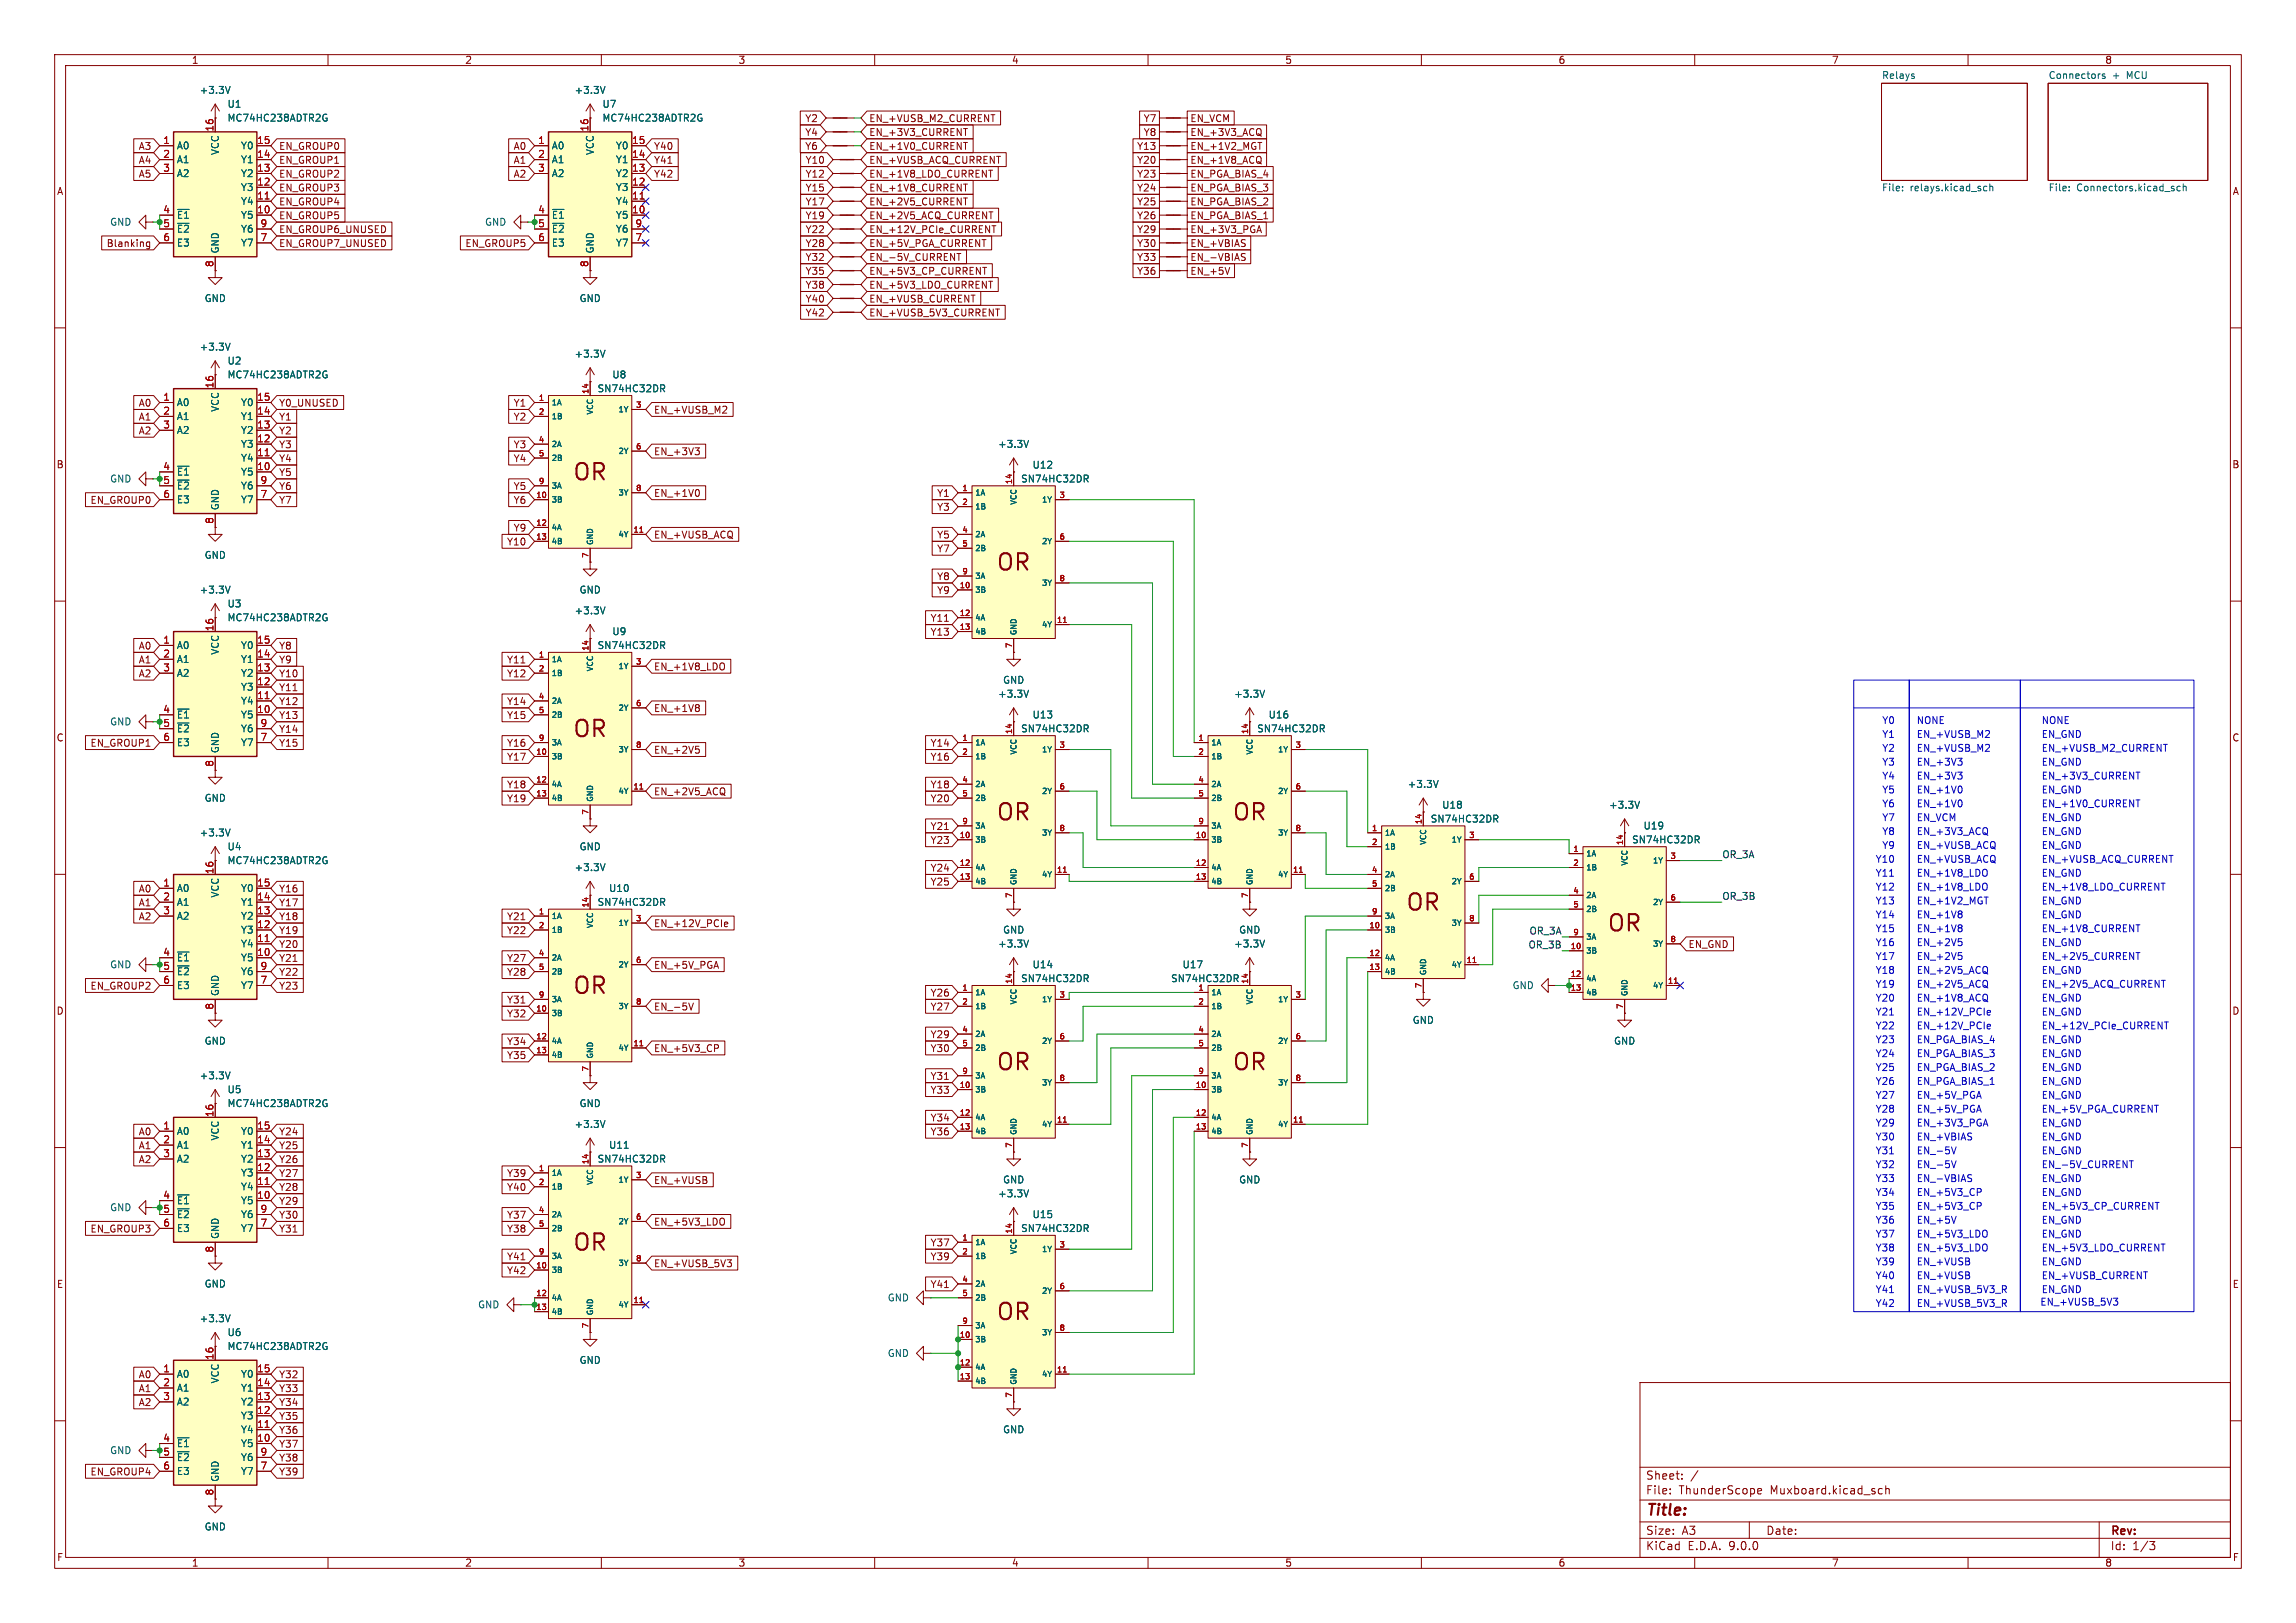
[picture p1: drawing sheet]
<svg xmlns="http://www.w3.org/2000/svg" width="420mm" height="297mm" viewBox="0 0 420 297" stroke-linecap="round" stroke-linejoin="round" font-family="sans-serif">
<defs><g id="words">
<g font-size="4.2" fill="#840000">
<text x="103.3" y="88.4">OR</text>
<text x="180.8" y="104.9">OR</text>
<text x="103.3" y="135.4">OR</text>
<text x="180.8" y="150.7">OR</text>
<text x="224" y="150.7">OR</text>
<text x="255.7" y="167.2">OR</text>
<text x="292.6" y="171">OR</text>
<text x="103.3" y="182.4">OR</text>
<text x="180.8" y="196.4">OR</text>
<text x="224" y="196.4">OR</text>
<text x="103.3" y="229.4">OR</text>
<text x="180.8" y="242.1">OR</text>
</g>
<text font-size="2.8" fill="#840000" x="301" y="277.9">Title:</text>
<g font-size="2.1" fill="#840000">
<text x="301" y="273.7">File:</text>
<text x="301" y="271">Sheet:</text>
<text x="307.1" y="273.7">ThunderScope</text>
<text x="323.9" y="273.7">Muxboard.kicad_sch</text>
<text x="301" y="281.1">Size:</text>
<text x="307.6" y="281.1">A3</text>
<text x="323" y="281.1">Date:</text>
<text x="386" y="281.3">Rev:</text>
<text x="301" y="283.9">KiCad</text>
<text x="308.7" y="283.9">E.D.A.</text>
<text x="316.3" y="283.9">9.0.0</text>
<text x="386" y="283.9">Id:</text>
<text x="390.1" y="283.9">1/3</text>
</g>
<g font-size="1.8" fill="#840000">
<text x="35" y="11.9">1</text>
<text x="85" y="11.9">2</text>
<text x="135" y="11.9">3</text>
<text x="185" y="11.9">4</text>
<text x="235" y="11.9">5</text>
<text x="285" y="11.9">6</text>
<text x="335" y="11.9">7</text>
<text x="385" y="11.9">8</text>
<text x="147.2" y="22.5">Y2</text>
<text x="158.9" y="22.5">EN_+VUSB_M2_CURRENT</text>
<text x="209.1" y="22.5">Y7</text>
<text x="217.6" y="22.5">EN_VCM</text>
<text x="25.3" y="27.6">A3</text>
<text x="51" y="27.6">EN_GROUP0</text>
<text x="93.9" y="27.6">A0</text>
<text x="119.5" y="27.6">Y40</text>
<text x="147.2" y="27.6">Y6</text>
<text x="147.2" y="25.1">Y4</text>
<text x="158.9" y="27.6">EN_+1V0_CURRENT</text>
<text x="158.9" y="25.1">EN_+3V3_CURRENT</text>
<text x="207.9" y="27.6">Y13</text>
<text x="209.1" y="25.1">Y8</text>
<text x="217.6" y="27.6">EN_+1V2_MGT</text>
<text x="217.6" y="25.1">EN_+3V3_ACQ</text>
<text x="10.3" y="35.9">A</text>
<text x="25.3" y="30.2">A4</text>
<text x="25.3" y="32.7">A5</text>
<text x="51" y="32.7">EN_GROUP2</text>
<text x="51" y="35.2">EN_GROUP3</text>
<text x="51" y="30.2">EN_GROUP1</text>
<text x="93.9" y="30.2">A1</text>
<text x="93.9" y="32.7">A2</text>
<text x="119.5" y="30.2">Y41</text>
<text x="119.5" y="32.7">Y42</text>
<text x="147.3" y="32.7">Y12</text>
<text x="147.3" y="30.2">Y10</text>
<text x="147.3" y="35.2">Y15</text>
<text x="158.9" y="32.7">EN_+1V8_LDO_CURRENT</text>
<text x="158.9" y="35.2">EN_+1V8_CURRENT</text>
<text x="158.9" y="30.2">EN_+VUSB_ACQ_CURRENT</text>
<text x="207.9" y="30.2">Y20</text>
<text x="207.9" y="32.7">Y23</text>
<text x="207.9" y="35.2">Y24</text>
<text x="217.6" y="30.2">EN_+1V8_ACQ</text>
<text x="217.6" y="35.2">EN_PGA_BIAS_3</text>
<text x="217.6" y="32.7">EN_PGA_BIAS_4</text>
<text x="408.3" y="35.9">A</text>
<text x="51" y="40.3">EN_GROUP5</text>
<text x="51" y="37.8">EN_GROUP4</text>
<text x="147.3" y="40.3">Y19</text>
<text x="147.3" y="37.8">Y17</text>
<text x="158.9" y="37.8">EN_+2V5_CURRENT</text>
<text x="158.9" y="40.3">EN_+2V5_ACQ_CURRENT</text>
<text x="207.9" y="37.8">Y25</text>
<text x="207.9" y="40.3">Y26</text>
<text x="217.6" y="37.8">EN_PGA_BIAS_2</text>
<text x="217.6" y="40.3">EN_PGA_BIAS_1</text>
<text x="19.4" y="45.4">Blanking</text>
<text x="51" y="42.9">EN_GROUP6_UNUSED</text>
<text x="51" y="45.4">EN_GROUP7_UNUSED</text>
<text x="85" y="45.4">EN_GROUP5</text>
<text x="147.3" y="42.9">Y22</text>
<text x="147.3" y="47.9">Y32</text>
<text x="147.3" y="45.4">Y28</text>
<text x="158.9" y="42.9">EN_+12V_PCIe_CURRENT</text>
<text x="158.9" y="47.9">EN_-5V_CURRENT</text>
<text x="158.9" y="45.4">EN_+5V_PGA_CURRENT</text>
<text x="207.9" y="45.4">Y30</text>
<text x="207.9" y="47.9">Y33</text>
<text x="207.9" y="42.9">Y29</text>
<text x="217.6" y="45.4">EN_+VBIAS</text>
<text x="217.6" y="42.9">EN_+3V3_PGA</text>
<text x="217.6" y="47.9">EN_-VBIAS</text>
<text x="147.3" y="50.5">Y35</text>
<text x="147.3" y="53">Y38</text>
<text x="158.9" y="50.5">EN_+5V3_CP_CURRENT</text>
<text x="158.9" y="53">EN_+5V3_LDO_CURRENT</text>
<text x="207.9" y="50.5">Y36</text>
<text x="217.6" y="50.5">EN_+5V</text>
<text x="147.3" y="55.6">Y40</text>
<text x="147.3" y="58.1">Y42</text>
<text x="158.9" y="55.6">EN_+VUSB_CURRENT</text>
<text x="158.9" y="58.1">EN_+VUSB_5V3_CURRENT</text>
<text x="25.3" y="74.6">A0</text>
<text x="25.3" y="77.2">A1</text>
<text x="51" y="77.2">Y1</text>
<text x="51" y="74.6">Y0_UNUSED</text>
<text x="93.9" y="77.2">Y2</text>
<text x="93.9" y="74.6">Y1</text>
<text x="119.5" y="75.9">EN_+VUSB_M2</text>
<text x="25.3" y="79.7">A2</text>
<text x="51" y="82.2">Y3</text>
<text x="51" y="79.7">Y2</text>
<text x="93.9" y="82.2">Y3</text>
<text x="119.5" y="83.5">EN_+3V3</text>
<text x="10.3" y="85.9">B</text>
<text x="51" y="89.9">Y6</text>
<text x="51" y="87.3">Y5</text>
<text x="51" y="84.8">Y4</text>
<text x="93.9" y="84.8">Y4</text>
<text x="93.9" y="89.9">Y5</text>
<text x="408.2" y="85.9">B</text>
<text x="16.5" y="92.4">EN_GROUP0</text>
<text x="51" y="92.4">Y7</text>
<text x="93.9" y="92.4">Y6</text>
<text x="119.5" y="91.1">EN_+1V0</text>
<text x="171.3" y="93.7">Y3</text>
<text x="171.3" y="91.1">Y1</text>
<text x="92.7" y="100">Y10</text>
<text x="93.9" y="97.5">Y9</text>
<text x="119.5" y="98.7">EN_+VUSB_ACQ</text>
<text x="171.3" y="101.3">Y7</text>
<text x="171.3" y="98.7">Y5</text>
<text x="171.3" y="106.4">Y8</text>
<text x="170.1" y="114">Y11</text>
<text x="171.3" y="108.9">Y9</text>
<text x="25.3" y="119.1">A0</text>
<text x="51" y="119.1">Y8</text>
<text x="170.1" y="116.5">Y13</text>
<text x="25.3" y="124.1">A2</text>
<text x="25.3" y="121.6">A1</text>
<text x="51" y="121.6">Y9</text>
<text x="51" y="124.1">Y10</text>
<text x="92.7" y="121.6">Y11</text>
<text x="92.7" y="124.1">Y12</text>
<text x="119.5" y="122.9">EN_+1V8_LDO</text>
<text x="51" y="126.7">Y11</text>
<text x="51" y="131.8">Y13</text>
<text x="51" y="129.2">Y12</text>
<text x="92.7" y="131.8">Y15</text>
<text x="92.7" y="129.2">Y14</text>
<text x="119.5" y="130.5">EN_+1V8</text>
<text x="10.3" y="135.9">C</text>
<text x="16.5" y="136.8">EN_GROUP1</text>
<text x="51" y="136.8">Y15</text>
<text x="51" y="134.3">Y14</text>
<text x="92.7" y="136.8">Y16</text>
<text x="170.1" y="136.8">Y14</text>
<text x="408.2" y="135.9">C</text>
<text x="92.7" y="139.4">Y17</text>
<text x="119.5" y="138.1">EN_+2V5</text>
<text x="170.1" y="139.4">Y16</text>
<text x="92.7" y="147">Y19</text>
<text x="92.7" y="144.5">Y18</text>
<text x="119.5" y="145.7">EN_+2V5_ACQ</text>
<text x="170.1" y="147">Y20</text>
<text x="170.1" y="144.5">Y18</text>
<text x="170.1" y="152.1">Y21</text>
<text x="170.1" y="154.6">Y23</text>
<text x="170.1" y="159.7">Y24</text>
<text x="25.3" y="166.1">A1</text>
<text x="25.3" y="163.5">A0</text>
<text x="51" y="166.1">Y17</text>
<text x="51" y="163.5">Y16</text>
<text x="170.1" y="162.2">Y25</text>
<text x="25.3" y="168.6">A2</text>
<text x="51" y="168.6">Y18</text>
<text x="51" y="171.1">Y19</text>
<text x="51" y="173.7">Y20</text>
<text x="92.7" y="168.6">Y21</text>
<text x="92.7" y="171.1">Y22</text>
<text x="119.5" y="169.9">EN_+12V_PCIe</text>
<text x="308.8" y="173.7">EN_GND</text>
<text x="51" y="176.2">Y21</text>
<text x="51" y="178.8">Y22</text>
<text x="92.7" y="176.2">Y27</text>
<text x="92.7" y="178.8">Y28</text>
<text x="119.5" y="177.5">EN_+5V_PGA</text>
<text x="10.3" y="185.9">D</text>
<text x="16.5" y="181.3">EN_GROUP2</text>
<text x="51" y="181.3">Y23</text>
<text x="92.7" y="183.8">Y31</text>
<text x="119.5" y="185.1">EN_-5V</text>
<text x="170.1" y="185.1">Y27</text>
<text x="170.1" y="182.6">Y26</text>
<text x="408.2" y="185.9">D</text>
<text x="92.7" y="191.5">Y34</text>
<text x="92.7" y="186.4">Y32</text>
<text x="170.1" y="190.2">Y29</text>
<text x="92.7" y="194">Y35</text>
<text x="119.5" y="192.7">EN_+5V3_CP</text>
<text x="170.1" y="192.7">Y30</text>
<text x="170.1" y="197.8">Y31</text>
<text x="170.1" y="200.3">Y33</text>
<text x="25.3" y="208">A0</text>
<text x="51" y="208">Y24</text>
<text x="170.1" y="205.4">Y34</text>
<text x="170.1" y="208">Y36</text>
<text x="25.3" y="210.5">A1</text>
<text x="25.3" y="213">A2</text>
<text x="51" y="215.6">Y27</text>
<text x="51" y="210.5">Y25</text>
<text x="51" y="213">Y26</text>
<text x="92.7" y="215.6">Y39</text>
<text x="51" y="220.7">Y29</text>
<text x="51" y="218.1">Y28</text>
<text x="92.7" y="218.1">Y40</text>
<text x="119.5" y="216.9">EN_+VUSB</text>
<text x="16.5" y="225.7">EN_GROUP3</text>
<text x="51" y="223.2">Y30</text>
<text x="51" y="225.7">Y31</text>
<text x="92.7" y="223.2">Y37</text>
<text x="92.7" y="225.7">Y38</text>
<text x="119.5" y="224.5">EN_+5V3_LDO</text>
<text x="92.7" y="233.4">Y42</text>
<text x="92.7" y="230.8">Y41</text>
<text x="119.5" y="232.1">EN_+VUSB_5V3</text>
<text x="170.1" y="228.3">Y37</text>
<text x="170.1" y="230.8">Y39</text>
<text x="10.3" y="235.9">E</text>
<text x="170.1" y="235.9">Y41</text>
<text x="408.3" y="235.9">E</text>
<text x="25.3" y="257.5">A2</text>
<text x="25.3" y="255">A1</text>
<text x="25.3" y="252.4">A0</text>
<text x="51" y="257.5">Y34</text>
<text x="51" y="255">Y33</text>
<text x="51" y="252.4">Y32</text>
<text x="51" y="260">Y35</text>
<text x="51" y="262.6">Y36</text>
<text x="51" y="265.1">Y37</text>
<text x="51" y="267.7">Y38</text>
<text x="16.5" y="270.2">EN_GROUP4</text>
<text x="51" y="270.2">Y39</text>
<text x="10.3" y="285.9">F</text>
<text x="35" y="286.9">1</text>
<text x="85" y="286.9">2</text>
<text x="135" y="286.9">3</text>
<text x="185" y="286.9">4</text>
<text x="235" y="286.9">5</text>
<text x="285" y="286.9">6</text>
<text x="335" y="286.9">7</text>
<text x="385" y="286.9">8</text>
<text x="408.3" y="285.9">F</text>
</g>
<g font-size="1.8" fill="#006464">
<text x="36.4" y="17.4">+3.3V</text>
<text x="105" y="17.4">+3.3V</text>
<text x="344.2" y="14.5">Relays</text>
<text x="374.6" y="14.5">Connectors</text>
<text x="386.4" y="14.5">+</text>
<text x="389.1" y="14.5">MCU</text>
<text x="41.5" y="22.5">MC74HC238ADTR2G</text>
<text x="41.5" y="19.9">U1</text>
<text x="110.1" y="22.5">MC74HC238ADTR2G</text>
<text x="110.1" y="19.9">U7</text>
<text x="32.3" y="27.5">A0</text>
<text x="40.2" y="28.5" transform="rotate(-90 40.2 28.5)">VCC</text>
<text x="44" y="27.5">Y0</text>
<text x="100.8" y="27.5">A0</text>
<text x="108.8" y="28.5" transform="rotate(-90 108.8 28.5)">VCC</text>
<text x="112.6" y="27.5">Y0</text>
<text x="32.3" y="30.1">A1</text>
<text x="32.3" y="32.6">A2</text>
<text x="44" y="30.1">Y1</text>
<text x="44" y="32.6">Y2</text>
<text x="44" y="35.2">Y3</text>
<text x="100.8" y="30.1">A1</text>
<text x="100.8" y="32.6">A2</text>
<text x="112.6" y="30.1">Y1</text>
<text x="112.6" y="32.6">Y2</text>
<text x="112.6" y="35.2">Y3</text>
<text x="344.2" y="35.3">File:</text>
<text x="349.4" y="35.3">relays.kicad_sch</text>
<text x="374.6" y="35.3">File:</text>
<text x="379.9" y="35.3">Connectors.kicad_sch</text>
<text x="20" y="41.5">GND</text>
<text x="32.3" y="40.2">~{E1}</text>
<text x="44" y="37.7">Y4</text>
<text x="44" y="40.2">Y5</text>
<text x="88.6" y="41.5">GND</text>
<text x="100.8" y="40.2">~{E1}</text>
<text x="112.6" y="37.7">Y4</text>
<text x="112.6" y="40.2">Y5</text>
<text x="32.3" y="42.8">~{E2}</text>
<text x="32.3" y="45.3">E3</text>
<text x="40.2" y="46.5" transform="rotate(-90 40.2 46.5)">GND</text>
<text x="44" y="42.8">Y6</text>
<text x="44" y="45.3">Y7</text>
<text x="100.8" y="42.8">~{E2}</text>
<text x="100.8" y="45.3">E3</text>
<text x="108.8" y="46.5" transform="rotate(-90 108.8 46.5)">GND</text>
<text x="112.6" y="42.8">Y6</text>
<text x="112.6" y="45.3">Y7</text>
<text x="37.3" y="55.5">GND</text>
<text x="105.9" y="55.5">GND</text>
<text x="36.4" y="64.4">+3.3V</text>
<text x="105" y="65.6">+3.3V</text>
<text x="41.5" y="69.4">MC74HC238ADTR2G</text>
<text x="41.5" y="66.9">U2</text>
<text x="109.2" y="72">SN74HC32DR</text>
<text x="111.9" y="69.4">U8</text>
<text x="32.3" y="74.5">A0</text>
<text x="32.3" y="77.1">A1</text>
<text x="40.2" y="75.5" transform="rotate(-90 40.2 75.5)">VCC</text>
<text x="44" y="74.5">Y0</text>
<text x="44" y="77.1">Y1</text>
<text x="32.3" y="79.6">A2</text>
<text x="44" y="79.6">Y2</text>
<text x="44" y="82.1">Y3</text>
<text x="182.5" y="82.1">+3.3V</text>
<text x="20" y="88.5">GND</text>
<text x="32.3" y="87.2">~{E1}</text>
<text x="32.3" y="89.8">~{E2}</text>
<text x="44" y="84.7">Y4</text>
<text x="44" y="87.2">Y5</text>
<text x="44" y="89.8">Y6</text>
<text x="186.7" y="88.5">SN74HC32DR</text>
<text x="188.8" y="86">U12</text>
<text x="32.3" y="92.3">E3</text>
<text x="40.2" y="93.5" transform="rotate(-90 40.2 93.5)">GND</text>
<text x="44" y="92.3">Y7</text>
<text x="37.3" y="102.5">GND</text>
<text x="36.4" y="108.8">+3.3V</text>
<text x="41.5" y="113.9">MC74HC238ADTR2G</text>
<text x="41.5" y="111.4">U3</text>
<text x="105" y="112.6">+3.3V</text>
<text x="105.9" y="108.8">GND</text>
<text x="32.3" y="119">A0</text>
<text x="40.2" y="119.9" transform="rotate(-90 40.2 119.9)">VCC</text>
<text x="44" y="119">Y0</text>
<text x="109.2" y="119">SN74HC32DR</text>
<text x="111.9" y="116.4">U9</text>
<text x="32.3" y="121.5">A1</text>
<text x="32.3" y="124.1">A2</text>
<text x="44" y="121.5">Y1</text>
<text x="44" y="124.1">Y2</text>
<text x="183.4" y="125.3">GND</text>
<text x="32.3" y="131.7">~{E1}</text>
<text x="44" y="126.6">Y3</text>
<text x="44" y="129.1">Y4</text>
<text x="44" y="131.7">Y5</text>
<text x="182.5" y="127.9">+3.3V</text>
<text x="188.8" y="131.7">U13</text>
<text x="225.7" y="127.9">+3.3V</text>
<text x="232" y="131.7">U16</text>
<text x="20" y="132.9">GND</text>
<text x="32.3" y="134.2">~{E2}</text>
<text x="32.3" y="136.8">E3</text>
<text x="40.2" y="137.9" transform="rotate(-90 40.2 137.9)">GND</text>
<text x="44" y="134.2">Y6</text>
<text x="44" y="136.8">Y7</text>
<text x="186.7" y="134.2">SN74HC32DR</text>
<text x="229.9" y="134.2">SN74HC32DR</text>
<text x="37.3" y="146.9">GND</text>
<text x="257.4" y="144.4">+3.3V</text>
<text x="263.7" y="148.2">U18</text>
<text x="294.2" y="148.2">+3.3V</text>
<text x="36.4" y="153.3">+3.3V</text>
<text x="41.5" y="155.8">U4</text>
<text x="105.9" y="155.8">GND</text>
<text x="261.6" y="150.7">SN74HC32DR</text>
<text x="298.4" y="154.5">SN74HC32DR</text>
<text x="300.5" y="152">U19</text>
<text x="41.5" y="158.3">MC74HC238ADTR2G</text>
<text x="105" y="159.6">+3.3V</text>
<text x="32.3" y="163.4">A0</text>
<text x="32.3" y="166">A1</text>
<text x="40.2" y="164.4" transform="rotate(-90 40.2 164.4)">VCC</text>
<text x="44" y="163.4">Y0</text>
<text x="44" y="166">Y1</text>
<text x="109.2" y="166">SN74HC32DR</text>
<text x="111.3" y="163.4">U10</text>
<text x="32.3" y="168.5">A2</text>
<text x="44" y="168.5">Y2</text>
<text x="44" y="171">Y3</text>
<text x="44" y="173.6">Y4</text>
<text x="182.5" y="173.6">+3.3V</text>
<text x="183.4" y="171">GND</text>
<text x="225.7" y="173.6">+3.3V</text>
<text x="226.6" y="171">GND</text>
<text x="20" y="177.4">GND</text>
<text x="32.3" y="176.1">~{E1}</text>
<text x="32.3" y="178.7">~{E2}</text>
<text x="44" y="176.1">Y5</text>
<text x="44" y="178.7">Y6</text>
<text x="186.7" y="179.9">SN74HC32DR</text>
<text x="188.8" y="177.4">U14</text>
<text x="214.1" y="179.9">SN74HC32DR</text>
<text x="216.2" y="177.4">U17</text>
<text x="32.3" y="181.2">E3</text>
<text x="40.2" y="182.4" transform="rotate(-90 40.2 182.4)">GND</text>
<text x="44" y="181.2">Y7</text>
<text x="276.6" y="181.2">GND</text>
<text x="37.3" y="191.4">GND</text>
<text x="258.3" y="187.6">GND</text>
<text x="295.1" y="191.4">GND</text>
<text x="36.4" y="197.7">+3.3V</text>
<text x="41.5" y="202.8">MC74HC238ADTR2G</text>
<text x="41.5" y="200.3">U5</text>
<text x="105.9" y="202.8">GND</text>
<text x="32.3" y="207.9">A0</text>
<text x="40.2" y="208.8" transform="rotate(-90 40.2 208.8)">VCC</text>
<text x="44" y="207.9">Y0</text>
<text x="105" y="206.6">+3.3V</text>
<text x="32.3" y="210.4">A1</text>
<text x="32.3" y="213">A2</text>
<text x="44" y="210.4">Y1</text>
<text x="44" y="213">Y2</text>
<text x="44" y="215.5">Y3</text>
<text x="109.2" y="213">SN74HC32DR</text>
<text x="111.3" y="210.4">U11</text>
<text x="20" y="221.8">GND</text>
<text x="32.3" y="220.6">~{E1}</text>
<text x="44" y="218">Y4</text>
<text x="44" y="220.6">Y5</text>
<text x="182.5" y="219.3">+3.3V</text>
<text x="183.4" y="216.8">GND</text>
<text x="226.6" y="216.8">GND</text>
<text x="32.3" y="223.1">~{E2}</text>
<text x="32.3" y="225.7">E3</text>
<text x="40.2" y="226.8" transform="rotate(-90 40.2 226.8)">GND</text>
<text x="44" y="223.1">Y6</text>
<text x="44" y="225.7">Y7</text>
<text x="186.7" y="225.7">SN74HC32DR</text>
<text x="188.8" y="223.1">U15</text>
<text x="37.3" y="235.8">GND</text>
<text x="87.4" y="239.6">GND</text>
<text x="162.3" y="238.4">GND</text>
<text x="36.4" y="242.2">+3.3V</text>
<text x="41.5" y="244.7">U6</text>
<text x="41.5" y="247.2">MC74HC238ADTR2G</text>
<text x="105.9" y="249.8">GND</text>
<text x="162.3" y="248.5">GND</text>
<text x="32.3" y="252.3">A0</text>
<text x="32.3" y="254.9">A1</text>
<text x="32.3" y="257.4">A2</text>
<text x="40.2" y="253.3" transform="rotate(-90 40.2 253.3)">VCC</text>
<text x="44" y="252.3">Y0</text>
<text x="44" y="254.9">Y1</text>
<text x="44" y="257.4">Y2</text>
<text x="44" y="259.9">Y3</text>
<text x="44" y="262.5">Y4</text>
<text x="183.4" y="262.5">GND</text>
<text x="20" y="266.3">GND</text>
<text x="32.3" y="265">~{E1}</text>
<text x="32.3" y="267.6">~{E2}</text>
<text x="44" y="265">Y5</text>
<text x="44" y="267.6">Y6</text>
<text x="32.3" y="270.1">E3</text>
<text x="40.2" y="271.3" transform="rotate(-90 40.2 271.3)">GND</text>
<text x="44" y="270.1">Y7</text>
<text x="37.3" y="280.3">GND</text>
</g>
<g font-size="1.8" fill="#a90000">
<text x="29.8" y="26.4">1</text>
<text x="29.8" y="29">2</text>
<text x="39.1" y="24.2" transform="rotate(-90 39.1 24.2)">16</text>
<text x="46.9" y="26.4">15</text>
<text x="46.9" y="29">14</text>
<text x="98.4" y="26.4">1</text>
<text x="98.4" y="29">2</text>
<text x="107.7" y="24.2" transform="rotate(-90 107.7 24.2)">16</text>
<text x="115.5" y="26.4">15</text>
<text x="115.5" y="29">14</text>
<text x="29.8" y="31.5">3</text>
<text x="46.9" y="31.5">13</text>
<text x="46.9" y="34">12</text>
<text x="98.4" y="31.5">3</text>
<text x="115.5" y="31.5">13</text>
<text x="115.5" y="34">12</text>
<text x="29.8" y="39.1">4</text>
<text x="29.8" y="41.7">5</text>
<text x="46.9" y="36.6">11</text>
<text x="46.9" y="39.1">10</text>
<text x="47.6" y="41.7">9</text>
<text x="98.4" y="39.1">4</text>
<text x="98.4" y="41.7">5</text>
<text x="115.5" y="36.6">11</text>
<text x="115.5" y="39.1">10</text>
<text x="116.1" y="41.7">9</text>
<text x="29.8" y="44.2">6</text>
<text x="47.6" y="44.2">7</text>
<text x="98.4" y="44.2">6</text>
<text x="116.1" y="44.2">7</text>
<text x="39.1" y="49" transform="rotate(-90 39.1 49)">8</text>
<text x="107.7" y="49" transform="rotate(-90 107.7 49)">8</text>
<text x="39.1" y="71.2" transform="rotate(-90 39.1 71.2)">16</text>
<text x="29.8" y="73.4">1</text>
<text x="29.8" y="75.9">2</text>
<text x="46.9" y="73.4">15</text>
<text x="46.9" y="75.9">14</text>
<text x="29.8" y="78.5">3</text>
<text x="46.9" y="78.5">13</text>
<text x="46.9" y="81">12</text>
<text x="46.9" y="83.6">11</text>
<text x="29.8" y="86.1">4</text>
<text x="29.8" y="88.6">5</text>
<text x="46.9" y="86.1">10</text>
<text x="47.6" y="88.6">9</text>
<text x="29.8" y="91.2">6</text>
<text x="39.1" y="96" transform="rotate(-90 39.1 96)">8</text>
<text x="47.6" y="91.2">7</text>
<text x="29.8" y="117.9">1</text>
<text x="39.1" y="115.6" transform="rotate(-90 39.1 115.6)">16</text>
<text x="46.9" y="117.9">15</text>
<text x="29.8" y="120.4">2</text>
<text x="29.8" y="122.9">3</text>
<text x="46.9" y="120.4">14</text>
<text x="46.9" y="122.9">13</text>
<text x="46.9" y="125.5">12</text>
<text x="29.8" y="130.6">4</text>
<text x="46.9" y="128">11</text>
<text x="46.9" y="130.6">10</text>
<text x="29.8" y="133.1">5</text>
<text x="29.8" y="135.6">6</text>
<text x="47.6" y="133.1">9</text>
<text x="47.6" y="135.6">7</text>
<text x="39.1" y="140.4" transform="rotate(-90 39.1 140.4)">8</text>
<text x="39.1" y="160.1" transform="rotate(-90 39.1 160.1)">16</text>
<text x="29.8" y="162.3">1</text>
<text x="29.8" y="164.8">2</text>
<text x="29.8" y="167.4">3</text>
<text x="46.9" y="162.3">15</text>
<text x="46.9" y="164.8">14</text>
<text x="46.9" y="167.4">13</text>
<text x="46.9" y="169.9">12</text>
<text x="46.9" y="172.5">11</text>
<text x="29.8" y="175">4</text>
<text x="29.8" y="177.5">5</text>
<text x="46.9" y="175">10</text>
<text x="47.6" y="177.5">9</text>
<text x="29.8" y="180.1">6</text>
<text x="39.1" y="184.9" transform="rotate(-90 39.1 184.9)">8</text>
<text x="47.6" y="180.1">7</text>
<text x="29.8" y="206.8">1</text>
<text x="29.8" y="209.3">2</text>
<text x="39.1" y="204.5" transform="rotate(-90 39.1 204.5)">16</text>
<text x="46.9" y="206.8">15</text>
<text x="46.9" y="209.3">14</text>
<text x="29.8" y="211.8">3</text>
<text x="46.9" y="211.8">13</text>
<text x="46.9" y="214.4">12</text>
<text x="29.8" y="219.5">4</text>
<text x="29.8" y="222">5</text>
<text x="46.9" y="216.9">11</text>
<text x="46.9" y="219.5">10</text>
<text x="47.6" y="222">9</text>
<text x="29.8" y="224.5">6</text>
<text x="47.6" y="224.5">7</text>
<text x="39.1" y="229.3" transform="rotate(-90 39.1 229.3)">8</text>
<text x="29.8" y="251.2">1</text>
<text x="39.1" y="249" transform="rotate(-90 39.1 249)">16</text>
<text x="46.9" y="251.2">15</text>
<text x="29.8" y="253.7">2</text>
<text x="29.8" y="256.3">3</text>
<text x="46.9" y="253.7">14</text>
<text x="46.9" y="256.3">13</text>
<text x="29.8" y="263.9">4</text>
<text x="46.9" y="258.8">12</text>
<text x="46.9" y="261.4">11</text>
<text x="46.9" y="263.9">10</text>
<text x="29.8" y="266.4">5</text>
<text x="29.8" y="269">6</text>
<text x="47.6" y="266.4">9</text>
<text x="47.6" y="269">7</text>
<text x="39.1" y="273.8" transform="rotate(-90 39.1 273.8)">8</text>
</g>
<g font-size="1.8" fill="#0000c2">
<text x="344.2" y="135.2">Y1</text>
<text x="344.2" y="137.8">Y2</text>
<text x="344.2" y="132.7">Y0</text>
<text x="350.5" y="132.7">NONE</text>
<text x="350.5" y="135.2">EN_+VUSB_M2</text>
<text x="350.5" y="137.8">EN_+VUSB_M2</text>
<text x="373.4" y="137.8">EN_+VUSB_M2_CURRENT</text>
<text x="373.4" y="132.7">NONE</text>
<text x="373.4" y="135.2">EN_GND</text>
<text x="344.2" y="142.9">Y4</text>
<text x="344.2" y="140.3">Y3</text>
<text x="350.5" y="142.9">EN_+3V3</text>
<text x="350.5" y="140.3">EN_+3V3</text>
<text x="373.4" y="140.3">EN_GND</text>
<text x="373.4" y="142.9">EN_+3V3_CURRENT</text>
<text x="344.2" y="145.4">Y5</text>
<text x="344.2" y="147.9">Y6</text>
<text x="350.5" y="147.9">EN_+1V0</text>
<text x="350.5" y="145.4">EN_+1V0</text>
<text x="373.4" y="147.9">EN_+1V0_CURRENT</text>
<text x="373.4" y="145.4">EN_GND</text>
<text x="344.2" y="155.6">Y9</text>
<text x="344.2" y="153">Y8</text>
<text x="344.2" y="150.5">Y7</text>
<text x="350.5" y="155.6">EN_+VUSB_ACQ</text>
<text x="350.5" y="150.5">EN_VCM</text>
<text x="350.5" y="153">EN_+3V3_ACQ</text>
<text x="373.4" y="150.5">EN_GND</text>
<text x="373.4" y="155.6">EN_GND</text>
<text x="373.4" y="153">EN_GND</text>
<text x="343" y="158.1">Y10</text>
<text x="343" y="160.6">Y11</text>
<text x="350.5" y="158.1">EN_+VUSB_ACQ</text>
<text x="350.5" y="160.6">EN_+1V8_LDO</text>
<text x="373.4" y="158.1">EN_+VUSB_ACQ_CURRENT</text>
<text x="373.4" y="160.6">EN_GND</text>
<text x="343" y="163.2">Y12</text>
<text x="343" y="165.7">Y13</text>
<text x="350.5" y="163.2">EN_+1V8_LDO</text>
<text x="350.5" y="165.7">EN_+1V2_MGT</text>
<text x="373.4" y="163.2">EN_+1V8_LDO_CURRENT</text>
<text x="373.4" y="165.7">EN_GND</text>
<text x="343" y="168.3">Y14</text>
<text x="343" y="173.3">Y16</text>
<text x="343" y="170.8">Y15</text>
<text x="350.5" y="173.3">EN_+2V5</text>
<text x="350.5" y="168.3">EN_+1V8</text>
<text x="350.5" y="170.8">EN_+1V8</text>
<text x="373.4" y="173.3">EN_GND</text>
<text x="373.4" y="168.3">EN_GND</text>
<text x="373.4" y="170.8">EN_+1V8_CURRENT</text>
<text x="343" y="175.9">Y17</text>
<text x="343" y="178.4">Y18</text>
<text x="350.5" y="178.4">EN_+2V5_ACQ</text>
<text x="350.5" y="175.9">EN_+2V5</text>
<text x="373.4" y="178.4">EN_GND</text>
<text x="373.4" y="175.9">EN_+2V5_CURRENT</text>
<text x="343" y="181">Y19</text>
<text x="343" y="183.5">Y20</text>
<text x="350.5" y="181">EN_+2V5_ACQ</text>
<text x="350.5" y="183.5">EN_+1V8_ACQ</text>
<text x="373.4" y="183.5">EN_GND</text>
<text x="373.4" y="181">EN_+2V5_ACQ_CURRENT</text>
<text x="343" y="191.1">Y23</text>
<text x="343" y="186">Y21</text>
<text x="343" y="188.6">Y22</text>
<text x="350.5" y="188.6">EN_+12V_PCIe</text>
<text x="350.5" y="191.1">EN_PGA_BIAS_4</text>
<text x="350.5" y="186">EN_+12V_PCIe</text>
<text x="373.4" y="186">EN_GND</text>
<text x="373.4" y="188.6">EN_+12V_PCIe_CURRENT</text>
<text x="373.4" y="191.1">EN_GND</text>
<text x="343" y="193.7">Y24</text>
<text x="343" y="196.2">Y25</text>
<text x="350.5" y="193.7">EN_PGA_BIAS_3</text>
<text x="350.5" y="196.2">EN_PGA_BIAS_2</text>
<text x="373.4" y="196.2">EN_GND</text>
<text x="373.4" y="193.7">EN_GND</text>
<text x="343" y="198.7">Y26</text>
<text x="343" y="203.8">Y28</text>
<text x="343" y="201.3">Y27</text>
<text x="350.5" y="198.7">EN_PGA_BIAS_1</text>
<text x="350.5" y="203.8">EN_+5V_PGA</text>
<text x="350.5" y="201.3">EN_+5V_PGA</text>
<text x="373.4" y="198.7">EN_GND</text>
<text x="373.4" y="203.8">EN_+5V_PGA_CURRENT</text>
<text x="373.4" y="201.3">EN_GND</text>
<text x="343" y="208.9">Y30</text>
<text x="343" y="206.4">Y29</text>
<text x="350.5" y="208.9">EN_+VBIAS</text>
<text x="350.5" y="206.4">EN_+3V3_PGA</text>
<text x="373.4" y="208.9">EN_GND</text>
<text x="373.4" y="206.4">EN_GND</text>
<text x="343" y="214">Y32</text>
<text x="343" y="211.4">Y31</text>
<text x="350.5" y="214">EN_-5V</text>
<text x="350.5" y="211.4">EN_-5V</text>
<text x="373.4" y="214">EN_-5V_CURRENT</text>
<text x="373.4" y="211.4">EN_GND</text>
<text x="343" y="219.1">Y34</text>
<text x="343" y="216.5">Y33</text>
<text x="343" y="221.6">Y35</text>
<text x="350.5" y="219.1">EN_+5V3_CP</text>
<text x="350.5" y="216.5">EN_-VBIAS</text>
<text x="350.5" y="221.6">EN_+5V3_CP</text>
<text x="373.4" y="221.6">EN_+5V3_CP_CURRENT</text>
<text x="373.4" y="219.1">EN_GND</text>
<text x="373.4" y="216.5">EN_GND</text>
<text x="343" y="226.7">Y37</text>
<text x="343" y="224.1">Y36</text>
<text x="350.5" y="224.1">EN_+5V</text>
<text x="350.5" y="226.7">EN_+5V3_LDO</text>
<text x="373.4" y="224.1">EN_GND</text>
<text x="373.4" y="226.7">EN_GND</text>
<text x="343" y="231.8">Y39</text>
<text x="343" y="229.2">Y38</text>
<text x="350.5" y="229.2">EN_+5V3_LDO</text>
<text x="350.5" y="231.8">EN_+VUSB</text>
<text x="373.4" y="229.2">EN_+5V3_LDO_CURRENT</text>
<text x="373.4" y="231.8">EN_GND</text>
<text x="343" y="236.8">Y41</text>
<text x="343" y="234.3">Y40</text>
<text x="343" y="239.4">Y42</text>
<text x="350.5" y="236.8">EN_+VUSB_5V3_R</text>
<text x="350.5" y="234.3">EN_+VUSB</text>
<text x="350.5" y="239.4">EN_+VUSB_5V3_R</text>
<text x="373.1" y="239.1">EN_+VUSB_5V3</text>
<text x="373.4" y="234.3">EN_+VUSB_CURRENT</text>
<text x="373.4" y="236.8">EN_GND</text>
</g>
<g font-size="1.8" fill="#0f0f0f">
<text x="315" y="157.1">OR_3A</text>
<text x="315" y="164.8">OR_3B</text>
<text x="279.5" y="173.6">OR_3B</text>
<text x="279.7" y="171.1">OR_3A</text>
</g>
<g font-size="1.4" fill="#a90000">
<text x="98.5" y="73.4">1</text>
<text x="98.5" y="75.9">2</text>
<text x="107.7" y="72.2" transform="rotate(-90 107.7 72.2)">14</text>
<text x="116.2" y="74.7">3</text>
<text x="98.5" y="81">4</text>
<text x="98.5" y="83.6">5</text>
<text x="116.2" y="82.3">6</text>
<text x="98.5" y="88.6">9</text>
<text x="116.2" y="89.9">8</text>
<text x="175.9" y="89.9">1</text>
<text x="185.2" y="88.7" transform="rotate(-90 185.2 88.7)">14</text>
<text x="98" y="91.2">10</text>
<text x="175.9" y="92.5">2</text>
<text x="193.7" y="91.2">3</text>
<text x="98" y="96.3">12</text>
<text x="98" y="98.8">13</text>
<text x="115.8" y="97.5">11</text>
<text x="175.9" y="97.5">4</text>
<text x="175.9" y="100.1">5</text>
<text x="193.7" y="98.8">6</text>
<text x="107.7" y="102.2" transform="rotate(-90 107.7 102.2)">7</text>
<text x="175.4" y="107.7">10</text>
<text x="175.9" y="105.2">9</text>
<text x="193.7" y="106.4">8</text>
<text x="175.4" y="112.8">12</text>
<text x="107.7" y="119.2" transform="rotate(-90 107.7 119.2)">14</text>
<text x="175.4" y="115.3">13</text>
<text x="185.2" y="118.7" transform="rotate(-90 185.2 118.7)">7</text>
<text x="193.2" y="114">11</text>
<text x="98.5" y="120.4">1</text>
<text x="98.5" y="122.9">2</text>
<text x="116.2" y="121.7">3</text>
<text x="98.5" y="128">4</text>
<text x="98.5" y="130.6">5</text>
<text x="116.2" y="129.3">6</text>
<text x="98.5" y="135.6">9</text>
<text x="116.2" y="136.9">8</text>
<text x="175.9" y="135.6">1</text>
<text x="185.2" y="134.4" transform="rotate(-90 185.2 134.4)">14</text>
<text x="193.7" y="136.9">3</text>
<text x="219.1" y="135.6">1</text>
<text x="228.3" y="134.4" transform="rotate(-90 228.3 134.4)">14</text>
<text x="236.9" y="136.9">3</text>
<text x="98" y="138.2">10</text>
<text x="98" y="143.3">12</text>
<text x="175.9" y="138.2">2</text>
<text x="175.9" y="143.3">4</text>
<text x="219.1" y="138.2">2</text>
<text x="219.1" y="143.3">4</text>
<text x="98" y="145.8">13</text>
<text x="107.7" y="149.2" transform="rotate(-90 107.7 149.2)">7</text>
<text x="115.8" y="144.5">11</text>
<text x="175.9" y="145.8">5</text>
<text x="193.7" y="144.5">6</text>
<text x="219.1" y="145.8">5</text>
<text x="236.9" y="144.5">6</text>
<text x="175.4" y="153.4">10</text>
<text x="175.9" y="150.9">9</text>
<text x="193.7" y="152.1">8</text>
<text x="218.6" y="153.4">10</text>
<text x="219.1" y="150.9">9</text>
<text x="236.9" y="152.1">8</text>
<text x="250.9" y="152.1">1</text>
<text x="250.9" y="154.7">2</text>
<text x="260.1" y="150.9" transform="rotate(-90 260.1 150.9)">14</text>
<text x="268.6" y="153.4">3</text>
<text x="287.7" y="156">1</text>
<text x="296.9" y="154.8" transform="rotate(-90 296.9 154.8)">14</text>
<text x="175.4" y="158.5">12</text>
<text x="175.4" y="161">13</text>
<text x="193.2" y="159.8">11</text>
<text x="218.6" y="158.5">12</text>
<text x="218.6" y="161">13</text>
<text x="236.4" y="159.8">11</text>
<text x="250.9" y="159.8">4</text>
<text x="268.6" y="161">6</text>
<text x="287.7" y="158.5">2</text>
<text x="305.5" y="157.2">3</text>
<text x="98.5" y="167.4">1</text>
<text x="107.7" y="166.2" transform="rotate(-90 107.7 166.2)">14</text>
<text x="185.2" y="164.4" transform="rotate(-90 185.2 164.4)">7</text>
<text x="228.3" y="164.4" transform="rotate(-90 228.3 164.4)">7</text>
<text x="250.9" y="162.3">5</text>
<text x="250.9" y="167.4">9</text>
<text x="287.7" y="163.6">4</text>
<text x="287.7" y="166.1">5</text>
<text x="305.5" y="164.8">6</text>
<text x="98.5" y="169.9">2</text>
<text x="116.2" y="168.7">3</text>
<text x="250.4" y="169.9">10</text>
<text x="268.6" y="168.7">8</text>
<text x="287.2" y="173.7">10</text>
<text x="287.7" y="171.2">9</text>
<text x="305.5" y="172.5">8</text>
<text x="98.5" y="175">4</text>
<text x="98.5" y="177.5">5</text>
<text x="116.2" y="176.3">6</text>
<text x="250.4" y="175">12</text>
<text x="250.4" y="177.5">13</text>
<text x="268.2" y="176.3">11</text>
<text x="287.2" y="178.8">12</text>
<text x="98" y="185.2">10</text>
<text x="98.5" y="182.6">9</text>
<text x="116.2" y="183.9">8</text>
<text x="175.9" y="181.4">1</text>
<text x="175.9" y="183.9">2</text>
<text x="185.2" y="180.2" transform="rotate(-90 185.2 180.2)">14</text>
<text x="193.7" y="182.6">3</text>
<text x="219.1" y="181.4">1</text>
<text x="219.1" y="183.9">2</text>
<text x="228.3" y="180.2" transform="rotate(-90 228.3 180.2)">14</text>
<text x="236.9" y="182.6">3</text>
<text x="260.1" y="180.9" transform="rotate(-90 260.1 180.9)">7</text>
<text x="287.2" y="181.4">13</text>
<text x="296.9" y="184.8" transform="rotate(-90 296.9 184.8)">7</text>
<text x="305" y="180.1">11</text>
<text x="98" y="190.2">12</text>
<text x="115.8" y="191.5">11</text>
<text x="175.9" y="189">4</text>
<text x="175.9" y="191.5">5</text>
<text x="193.7" y="190.2">6</text>
<text x="219.1" y="189">4</text>
<text x="219.1" y="191.5">5</text>
<text x="236.9" y="190.2">6</text>
<text x="98" y="192.8">13</text>
<text x="107.7" y="196.2" transform="rotate(-90 107.7 196.2)">7</text>
<text x="175.9" y="196.6">9</text>
<text x="193.7" y="197.9">8</text>
<text x="219.1" y="196.6">9</text>
<text x="236.9" y="197.9">8</text>
<text x="175.4" y="199.1">10</text>
<text x="218.6" y="199.1">10</text>
<text x="175.4" y="204.2">12</text>
<text x="175.4" y="206.8">13</text>
<text x="193.2" y="205.5">11</text>
<text x="218.6" y="204.2">12</text>
<text x="218.6" y="206.8">13</text>
<text x="236.4" y="205.5">11</text>
<text x="98.5" y="214.4">1</text>
<text x="107.7" y="213.2" transform="rotate(-90 107.7 213.2)">14</text>
<text x="116.2" y="215.6">3</text>
<text x="185.2" y="210.2" transform="rotate(-90 185.2 210.2)">7</text>
<text x="228.3" y="210.2" transform="rotate(-90 228.3 210.2)">7</text>
<text x="98.5" y="216.9">2</text>
<text x="98.5" y="222">4</text>
<text x="98.5" y="224.5">5</text>
<text x="116.2" y="223.3">6</text>
<text x="175.9" y="227.1">1</text>
<text x="185.2" y="225.9" transform="rotate(-90 185.2 225.9)">14</text>
<text x="98" y="232.2">10</text>
<text x="98.5" y="229.6">9</text>
<text x="116.2" y="230.9">8</text>
<text x="175.9" y="229.6">2</text>
<text x="193.7" y="228.3">3</text>
<text x="98" y="237.2">12</text>
<text x="98" y="239.8">13</text>
<text x="115.8" y="238.5">11</text>
<text x="175.9" y="234.7">4</text>
<text x="175.9" y="237.2">5</text>
<text x="193.7" y="236">6</text>
<text x="107.7" y="243.2" transform="rotate(-90 107.7 243.2)">7</text>
<text x="175.4" y="244.9">10</text>
<text x="175.9" y="242.3">9</text>
<text x="193.7" y="243.6">8</text>
<text x="175.4" y="249.9">12</text>
<text x="193.2" y="251.2">11</text>
<text x="175.4" y="252.5">13</text>
<text x="185.2" y="255.9" transform="rotate(-90 185.2 255.9)">7</text>
</g>
<g font-size="1.4" fill="#006464">
<text x="100.8" y="74.4">1A</text>
<text x="100.8" y="76.9">1B</text>
<text x="108.7" y="76" transform="rotate(-90 108.7 76)">VCC</text>
<text x="113" y="75.7">1Y</text>
<text x="100.8" y="82">2A</text>
<text x="113" y="83.3">2Y</text>
<text x="100.8" y="84.5">2B</text>
<text x="100.8" y="89.6">3A</text>
<text x="100.8" y="92.2">3B</text>
<text x="113" y="90.9">3Y</text>
<text x="178.3" y="90.9">1A</text>
<text x="178.3" y="93.4">1B</text>
<text x="186.1" y="92.5" transform="rotate(-90 186.1 92.5)">VCC</text>
<text x="190.5" y="92.2">1Y</text>
<text x="100.8" y="97.2">4A</text>
<text x="100.8" y="99.8">4B</text>
<text x="108.7" y="99.8" transform="rotate(-90 108.7 99.8)">GND</text>
<text x="113" y="98.5">4Y</text>
<text x="178.3" y="98.5">2A</text>
<text x="178.3" y="101.1">2B</text>
<text x="190.5" y="99.8">2Y</text>
<text x="178.3" y="106.1">3A</text>
<text x="190.5" y="107.4">3Y</text>
<text x="178.3" y="108.7">3B</text>
<text x="178.3" y="113.8">4A</text>
<text x="178.3" y="116.3">4B</text>
<text x="186.1" y="116.3" transform="rotate(-90 186.1 116.3)">GND</text>
<text x="190.5" y="115">4Y</text>
<text x="100.8" y="121.4">1A</text>
<text x="100.8" y="123.9">1B</text>
<text x="108.7" y="123" transform="rotate(-90 108.7 123)">VCC</text>
<text x="113" y="122.6">1Y</text>
<text x="100.8" y="129">2A</text>
<text x="100.8" y="131.5">2B</text>
<text x="113" y="130.3">2Y</text>
<text x="100.8" y="136.6">3A</text>
<text x="113" y="137.9">3Y</text>
<text x="178.3" y="136.6">1A</text>
<text x="190.5" y="137.9">1Y</text>
<text x="221.5" y="136.6">1A</text>
<text x="233.6" y="137.9">1Y</text>
<text x="100.8" y="139.2">3B</text>
<text x="178.3" y="139.2">1B</text>
<text x="186.1" y="138.2" transform="rotate(-90 186.1 138.2)">VCC</text>
<text x="221.5" y="139.2">1B</text>
<text x="229.3" y="138.2" transform="rotate(-90 229.3 138.2)">VCC</text>
<text x="100.8" y="144.2">4A</text>
<text x="100.8" y="146.8">4B</text>
<text x="108.7" y="146.8" transform="rotate(-90 108.7 146.8)">GND</text>
<text x="113" y="145.5">4Y</text>
<text x="178.3" y="144.2">2A</text>
<text x="178.3" y="146.8">2B</text>
<text x="190.5" y="145.5">2Y</text>
<text x="221.5" y="144.2">2A</text>
<text x="221.5" y="146.8">2B</text>
<text x="233.6" y="145.5">2Y</text>
<text x="178.3" y="151.9">3A</text>
<text x="178.3" y="154.4">3B</text>
<text x="190.5" y="153.1">3Y</text>
<text x="221.5" y="151.9">3A</text>
<text x="221.5" y="154.4">3B</text>
<text x="233.6" y="153.1">3Y</text>
<text x="253.2" y="153.1">1A</text>
<text x="253.2" y="155.7">1B</text>
<text x="261.1" y="154.8" transform="rotate(-90 261.1 154.8)">VCC</text>
<text x="265.4" y="154.4">1Y</text>
<text x="178.3" y="159.5">4A</text>
<text x="190.5" y="160.7">4Y</text>
<text x="221.5" y="159.5">4A</text>
<text x="233.6" y="160.7">4Y</text>
<text x="253.2" y="160.7">2A</text>
<text x="290.1" y="156.9">1A</text>
<text x="290.1" y="159.5">1B</text>
<text x="297.9" y="158.6" transform="rotate(-90 297.9 158.6)">VCC</text>
<text x="302.2" y="158.2">1Y</text>
<text x="178.3" y="162">4B</text>
<text x="186.1" y="162.1" transform="rotate(-90 186.1 162.1)">GND</text>
<text x="221.5" y="162">4B</text>
<text x="229.3" y="162.1" transform="rotate(-90 229.3 162.1)">GND</text>
<text x="253.2" y="163.3">2B</text>
<text x="265.4" y="162">2Y</text>
<text x="290.1" y="164.6">2A</text>
<text x="290.1" y="167.1">2B</text>
<text x="302.2" y="165.8">2Y</text>
<text x="100.8" y="168.4">1A</text>
<text x="100.8" y="170.9">1B</text>
<text x="108.7" y="170" transform="rotate(-90 108.7 170)">VCC</text>
<text x="113" y="169.6">1Y</text>
<text x="253.2" y="168.4">3A</text>
<text x="253.2" y="170.9">3B</text>
<text x="265.4" y="169.6">3Y</text>
<text x="290.1" y="172.2">3A</text>
<text x="302.2" y="173.4">3Y</text>
<text x="100.8" y="176">2A</text>
<text x="100.8" y="178.5">2B</text>
<text x="113" y="177.3">2Y</text>
<text x="253.2" y="176">4A</text>
<text x="253.2" y="178.5">4B</text>
<text x="261.1" y="178.6" transform="rotate(-90 261.1 178.6)">GND</text>
<text x="265.4" y="177.3">4Y</text>
<text x="290.1" y="174.7">3B</text>
<text x="290.1" y="179.8">4A</text>
<text x="100.8" y="183.6">3A</text>
<text x="113" y="184.9">3Y</text>
<text x="178.3" y="182.3">1A</text>
<text x="178.3" y="184.9">1B</text>
<text x="186.1" y="184" transform="rotate(-90 186.1 184)">VCC</text>
<text x="190.5" y="183.6">1Y</text>
<text x="221.5" y="182.3">1A</text>
<text x="221.5" y="184.9">1B</text>
<text x="229.3" y="184" transform="rotate(-90 229.3 184)">VCC</text>
<text x="233.6" y="183.6">1Y</text>
<text x="290.1" y="182.3">4B</text>
<text x="297.9" y="182.4" transform="rotate(-90 297.9 182.4)">GND</text>
<text x="302.2" y="181.1">4Y</text>
<text x="100.8" y="186.1">3B</text>
<text x="100.8" y="191.2">4A</text>
<text x="178.3" y="190">2A</text>
<text x="190.5" y="191.2">2Y</text>
<text x="221.5" y="190">2A</text>
<text x="233.6" y="191.2">2Y</text>
<text x="100.8" y="193.8">4B</text>
<text x="108.7" y="193.8" transform="rotate(-90 108.7 193.8)">GND</text>
<text x="113" y="192.5">4Y</text>
<text x="178.3" y="192.5">2B</text>
<text x="178.3" y="197.6">3A</text>
<text x="221.5" y="192.5">2B</text>
<text x="221.5" y="197.6">3A</text>
<text x="178.3" y="200.1">3B</text>
<text x="190.5" y="198.8">3Y</text>
<text x="221.5" y="200.1">3B</text>
<text x="233.6" y="198.8">3Y</text>
<text x="178.3" y="205.2">4A</text>
<text x="178.3" y="207.7">4B</text>
<text x="186.1" y="207.8" transform="rotate(-90 186.1 207.8)">GND</text>
<text x="190.5" y="206.5">4Y</text>
<text x="221.5" y="205.2">4A</text>
<text x="221.5" y="207.7">4B</text>
<text x="229.3" y="207.8" transform="rotate(-90 229.3 207.8)">GND</text>
<text x="233.6" y="206.5">4Y</text>
<text x="100.8" y="215.4">1A</text>
<text x="100.8" y="217.9">1B</text>
<text x="108.7" y="217" transform="rotate(-90 108.7 217)">VCC</text>
<text x="113" y="216.6">1Y</text>
<text x="100.8" y="223">2A</text>
<text x="100.8" y="225.5">2B</text>
<text x="113" y="224.2">2Y</text>
<text x="100.8" y="230.6">3A</text>
<text x="100.8" y="233.1">3B</text>
<text x="113" y="231.9">3Y</text>
<text x="178.3" y="228.1">1A</text>
<text x="178.3" y="230.6">1B</text>
<text x="186.1" y="229.7" transform="rotate(-90 186.1 229.7)">VCC</text>
<text x="190.5" y="229.3">1Y</text>
<text x="100.8" y="238.2">4A</text>
<text x="113" y="239.5">4Y</text>
<text x="178.3" y="235.7">2A</text>
<text x="178.3" y="238.2">2B</text>
<text x="190.5" y="236.9">2Y</text>
<text x="100.8" y="240.8">4B</text>
<text x="108.7" y="240.8" transform="rotate(-90 108.7 240.8)">GND</text>
<text x="178.3" y="243.3">3A</text>
<text x="178.3" y="245.8">3B</text>
<text x="190.5" y="244.6">3Y</text>
<text x="178.3" y="250.9">4A</text>
<text x="178.3" y="253.5">4B</text>
<text x="186.1" y="253.5" transform="rotate(-90 186.1 253.5)">GND</text>
<text x="190.5" y="252.2">4Y</text>
</g>
</g></defs>
<g fill="none" stroke="#840000" stroke-width=".18">
<path d="M10 10h400v277h-400zM12 12h396v273h-396zM60 10v2M110 10v2M160 10v2M210 10v2M260 10v2M310 10v2M344.2 15.2h26.6v17.8h-26.6zM360 10v2M374.6 15.2h29.3v17.8h-29.3zM10 60h2"/>
<path d="M408 60h2M10 110h2M408 110h2M10 160h2M408 160h2M297.2 185.4v1.3h1.2l-1.2 1.3-1.3-1.3h1.3M297.2 185.4h.1M10 210h2M408 210h2M300 253h108v32h-108zM10 260h2M300 278.5h108"/>
<path d="M300 274.5h108M300 268.5h108M305.5 273.2v.2M305.5 272.5v.1M307.7 270.5v.2M307.7 269.8v.1M310.6 269.1l-1.3 1.9M320 278.5v3M321.5 272.9l.7-.2v-.2l-.5-.1-.2 .2 .1 .7h.6M343.6 273.1l.3 .3 .4-.1M344.3 272.5l-.4-.1-.3 .3M344.9 272.5l.3-.1 .3 .1 .1 .9"/>
<path d="M344.9 271.9v1.5M384 278.5v6.5M408 260h2M60 285v2M110 285v2M160 285v2M210 285v2M260 285v2M300 281.5h108M310 285v2M360 285v2M393.2 282.1h1l-.5 .6 .4 .1 .1 .5-.3 .3h-.5"/>
</g>
<g fill="none" stroke="#006464" stroke-width=".18">
<path d="M350 13.9l.2 .2-.2 .3M350 13.5l.1 .1M385 13.6l-.3-.1-.2 .2 .1 .2 .4 .1v.3h-.5M348 34.8v.1M348 34.1v.2M363 34.9h.4M363 34.1h.4M364 34.2l.2-.1h.3v.8M364 33.7v1.2M378.5 34.8v.1M378.5 34.1v.2M398.8 34.1h-.3l-.3 .2 .1 .6h.5"/>
<path d="M399.4 34.2l.1-.1h.3l.1 .8M399.4 33.7v1.2"/>
</g>
<path d="M31.7 160h15.3v22.9h-15.3z" fill="#ffffc2"/>
<path d="M31.7 160h15.3v22.9h-15.3z" fill="none" stroke="#840000" stroke-width=".25"/>
<g fill="none" stroke="#840000" stroke-width=".18">
<path d="M39.4 113h.1M39.4 110.5v2.5M39.4 110.5l-.8 1.3M39.4 110.5l.7 1.3M26.7 132.1v-1.3l-1.3 1.3 1.3 1.3v-1.3h1.2M27.9 132.1h.1M228.6 132.1h.1M228.6 129.5l-.8 1.3M228.6 129.5l.8 1.3M228.6 129.5v2.6M39.4 157.5v2.5M107.9 149.9v1.2h1.3l-1.3 1.3-1.2-1.3h1.2"/>
<path d="M107.9 149.9h.1M26.7 176.5v-1.2l-1.3 1.2 1.3 1.3v-1.3h1.2M27.9 176.5h.1M29.2 162.6h2.5M29.2 165.1h2.5M29.2 167.6h2.5M29.2 175.3h2.5M29.2 177.8h2.5M47 162.6h2.5M47 165.1h2.5M47 167.6h2.5M47 175.3h2.5"/>
<path d="M47 177.8h2.5M47 170.2h2.5M47 172.7h2.5M29.2 180.3h2.5M39.4 185.4v1.3h1.2l-1.2 1.3-1.3-1.3h1.3M39.4 185.4h.1M39.4 182.9v2.5M47 180.3h2.5"/>
</g>
<path d="M42.1 107.3l-.4 1.2M231.3 126.3l-.4 1.3M59.3 156.9h.5M59.6 157.5h.2v.4l-.2 .2-.3-.1M32.5 174.2h2.1" fill="none" stroke="#006464" stroke-width=".18"/>
<path d="M48.5 172.3h.7" fill="none" stroke="#a90000" stroke-width=".18"/>
<path d="M100.3 119.4h15.3v27.9h-15.3z" fill="#ffffc2"/>
<g fill="none" stroke="#840000" stroke-width=".18">
<path d="M100.3 119.4h15.3v27.9h-15.3zM107.9 116.8h.1M107.9 102.9v1.2h1.3l-1.3 1.3-1.2-1.3h1.2M107.9 102.9h.1M107.9 114.3v5.1M107.9 114.3l-.7 1.3M107.9 114.3l.8 1.3M97.8 120.7h2.5M97.8 123.2h2.5M97.8 128.3h2.5M97.8 130.8h2.5M97.8 135.9h2.5"/>
<path d="M97.8 138.4h2.5M115.6 121.9h2.5M115.6 129.5h2.5M115.6 137.2h2.5M97.8 143.5h2.5M97.8 146.1h2.5M107.9 147.3v2.6M115.6 144.8h2.5M107.9 163.8h.1M107.9 161.3v2.5M107.9 161.3l-.7 1.3M107.9 161.3l.8 1.3"/>
<path d="M39.4 274.3v1.3h1.2l-1.2 1.3-1.3-1.3h1.3M39.4 274.3h.1"/>
</g>
<path d="M117 144.4h.6" fill="none" stroke="#a90000" stroke-width=".18"/>
<path d="M110.7 111.1l-.5 1.2M120.9 117.4h.4l.3 .3-.1 .3-.6 .1M121.2 118.1l.4 .6M110.7 158.1l-.5 1.2" fill="none" stroke="#006464" stroke-width=".18"/>
<path d="M31.7 115.6h15.3v22.8h-15.3z" fill="#ffffc2"/>
<path d="M31.7 115.6h15.3v22.8h-15.3z" fill="none" stroke="#840000" stroke-width=".25"/>
<g fill="none" stroke="#840000" stroke-width=".18">
<path d="M29.2 118.1h2.5M39.4 113v2.6M47 118.1h2.5M29.2 120.7h2.5M29.2 123.2h2.5M29.2 130.8h2.5M29.2 133.4h2.5M29.2 135.9h2.5M39.4 138.4v2.6M47 120.7h2.5M47 123.2h2.5M47 130.8h2.5"/>
<path d="M47 133.4h2.5M47 135.9h2.5M47 125.7h2.5M47 128.3h2.5M39.4 141v1.2h1.2l-1.2 1.3-1.3-1.3h1.3M39.4 141h.1M185.4 177.8h.1M185.4 165.1v1.3h1.3l-1.3 1.2-1.3-1.2h1.3M185.4 165.1h.1M185.4 175.3l-.7 1.2M185.4 175.3l.8 1.2M185.4 175.3v2.5"/>
<path d="M107.9 196.9v1.2h1.3l-1.3 1.3-1.2-1.3h1.2M107.9 196.9h.1M107.9 210.8h.1M107.9 208.3l-.7 1.3M107.9 208.3l.8 1.3M107.9 208.3v2.5M168.9 247.6v-1.2l-1.3 1.2 1.3 1.3v-1.3h1.3M170.2 247.6h.1"/>
</g>
<path d="M59.3 112.4h.5M59.6 113.1h.2v.4l-.2 .1-.3-.1M32.5 129.8h2.1M188.1 172l-.4 1.3M110.7 205l-.5 1.3" fill="none" stroke="#006464" stroke-width=".18"/>
<path d="M48.5 127.9h.7" fill="none" stroke="#a90000" stroke-width=".18"/>
<path d="M252.7 151.1h15.3v28h-15.3z" fill="#ffffc2"/>
<g fill="none" stroke="#840000" stroke-width=".18">
<path d="M39.4 157.5h.1M39.4 154.9l-.8 1.3M39.4 154.9l.7 1.3M39.4 154.9v2.6M250.2 152.4h2.5M250.2 154.9h2.5M252.7 151.1h15.3v28h-15.3zM260.3 148.6v2.5M268 153.7h2.5M250.2 160h2.5M250.2 162.6h2.5M250.2 167.6h2.5"/>
<path d="M250.2 170.2h2.5M250.2 175.3h2.5M250.2 177.8h2.5M260.3 179.1v2.5M268 161.3h2.5M268 168.9h2.5M268 176.5h2.5"/>
</g>
<path d="M269.4 176.1h.6" fill="none" stroke="#a90000" stroke-width=".18"/>
<path d="M42.1 151.7l-.4 1.3M273.3 149.2h.4l.3 .2-.1 .4h-.6M273.6 149.8l.4 .6" fill="none" stroke="#006464" stroke-width=".18"/>
<path d="M177.8 134.6h15.2v28h-15.2z" fill="#ffffc2"/>
<g fill="none" stroke="#840000" stroke-width=".18">
<path d="M175.3 135.9h2.5M175.3 138.4h2.5M177.8 134.6h15.2v28h-15.2zM185.4 132.1v2.5M193 137.2h2.6M175.3 143.5h2.5M175.3 146.1h2.5M175.3 151.1h2.5M175.3 153.7h2.5M175.3 158.8h2.5M193 144.8h2.6M193 152.4h2.6"/>
<path d="M175.3 161.3h2.5M185.4 162.6v2.5M193 160h2.6"/>
</g>
<path d="M194.5 159.6h.6" fill="none" stroke="#a90000" stroke-width=".18"/>
<path d="M198.3 132.7h.5l.3 .2-.2 .4h-.6M198.6 133.3l.5 .6" fill="none" stroke="#006464" stroke-width=".18"/>
<path d="M221 134.6h15.2v28h-15.2z" fill="#ffffc2"/>
<g fill="none" stroke="#840000" stroke-width=".18">
<path d="M185.4 86.4h.1M185.4 83.8l-.7 1.3M185.4 83.8l.8 1.3M185.4 83.8v2.6M218.4 135.9h2.6M218.4 138.4h2.6M221 134.6h15.2v28h-15.2zM228.6 132.1v2.5M236.2 137.2h2.6M218.4 143.5h2.6M218.4 146.1h2.6M218.4 151.1h2.6"/>
<path d="M218.4 153.7h2.6M218.4 158.8h2.6M236.2 144.8h2.6M236.2 152.4h2.6M218.4 161.3h2.6M228.6 162.6v2.5M236.2 160h2.6"/>
</g>
<path d="M237.7 159.6h.6" fill="none" stroke="#a90000" stroke-width=".18"/>
<path d="M188.1 80.6l-.4 1.3M241.5 132.7h.5l.2 .2-.1 .4h-.6M241.8 133.3l.4 .6" fill="none" stroke="#006464" stroke-width=".18"/>
<path d="M100.3 213.4h15.3v27.9h-15.3z" fill="#ffffc2"/>
<g fill="none" stroke="#840000" stroke-width=".18">
<path d="M97.8 214.6h2.5M97.8 217.2h2.5M100.3 213.4h15.3v27.9h-15.3zM107.9 210.8v2.6M115.6 215.9h2.5M26.7 221v-1.3l-1.3 1.3 1.3 1.2v-1.2h1.2M27.9 221h.1M97.8 222.2h2.5M97.8 224.8h2.5M97.8 229.9h2.5M97.8 232.4h2.5M97.8 237.5h2.5"/>
<path d="M115.6 223.5h2.5M115.6 231.1h2.5M115.6 238.8h2.5M97.8 240h2.5M107.9 241.3v2.5"/>
</g>
<path d="M117 238.4h.6" fill="none" stroke="#a90000" stroke-width=".18"/>
<path d="M114.2 210.1h.7M120.9 211.4h.4l.3 .2-.1 .4-.6 .1M121.2 212.1l.4 .6" fill="none" stroke="#006464" stroke-width=".18"/>
<path d="M289.6 154.9h15.2v28h-15.2z" fill="#ffffc2"/>
<g fill="none" stroke="#840000" stroke-width=".18">
<path d="M287 156.2h2.6M287 158.8h2.6M289.6 154.9h15.2v28h-15.2zM297.2 152.4h.1M297.2 149.9v5M297.2 149.9l-.8 1.2M297.2 149.9l.7 1.2M304.8 157.5h2.5M287 163.8h2.6M287 166.4h2.6M287 171.5h2.6M287 174h2.6"/>
<path d="M287 179.1h2.6M304.8 165.1h2.5M304.8 172.7h2.5M287 181.6h2.6M297.2 182.9v2.5M304.8 180.3h2.5"/>
</g>
<path d="M306.3 180h.5" fill="none" stroke="#a90000" stroke-width=".18"/>
<path d="M299.9 146.6l-.4 1.3M310.1 153h.5l.2 .2-.1 .4h-.6M310.4 153.6l.4 .6" fill="none" stroke="#006464" stroke-width=".18"/>
<path d="M177.8 180.3h15.2v28h-15.2z" fill="#ffffc2"/>
<g fill="none" stroke="#840000" stroke-width=".18">
<path d="M185.4 119.4v1.3h1.3l-1.3 1.2-1.3-1.2h1.3M185.4 119.4h.1M185.4 132.1h.1M185.4 129.5v2.6M185.4 129.5l-.7 1.3M185.4 129.5l.8 1.3M185.4 177.8v2.5M175.3 181.6h2.5M175.3 184.2h2.5M175.3 189.2h2.5M175.3 191.8h2.5M175.3 196.9h2.5"/>
<path d="M175.3 199.4h2.5M177.8 180.3h15.2v28h-15.2zM193 182.9h2.6M193 190.5h2.6M193 198.1h2.6M175.3 204.5h2.5M175.3 207h2.5M185.4 208.3v2.5M193 205.7h2.6M168.9 237.5v-1.3l-1.3 1.3 1.3 1.3v-1.3h1.3M170.2 237.5h.1"/>
</g>
<path d="M194.5 205.4h.6" fill="none" stroke="#a90000" stroke-width=".18"/>
<path d="M188.1 126.3l-.4 1.3M198.3 178.4h.5l.3 .2-.2 .4h-.6M198.6 179l.5 .6" fill="none" stroke="#006464" stroke-width=".18"/>
<path d="M177.8 88.9h15.2v27.9h-15.2z" fill="#ffffc2"/>
<g fill="none" stroke="#840000" stroke-width=".18">
<path d="M175.3 90.2h2.5M175.3 92.7h2.5M175.3 97.8h2.5M177.8 88.9h15.2v27.9h-15.2zM185.4 86.4v2.5M193 91.4h2.6M193 99.1h2.6M175.3 100.3h2.5M175.3 105.4h2.5M175.3 108h2.5M175.3 113h2.5M175.3 115.6h2.5"/>
<path d="M185.4 116.8v2.6M193 106.7h2.6M193 114.3h2.6"/>
</g>
<path d="M194.5 113.9h.6" fill="none" stroke="#a90000" stroke-width=".18"/>
<path d="M198.3 86.9h.5l.3 .3-.2 .3-.6 .1M198.6 87.6l.5 .6" fill="none" stroke="#006464" stroke-width=".18"/>
<path d="M177.8 226.1h15.2v27.9h-15.2z" fill="#ffffc2"/>
<g fill="none" stroke="#840000" stroke-width=".18">
<path d="M39.4 96.5v1.3h1.2l-1.2 1.3-1.3-1.3h1.3M39.4 96.5h.1M94 238.8v-1.3l-1.3 1.3 1.3 1.2v-1.2h1.2M95.2 238.8h.1M175.3 227.3h2.5M175.3 229.9h2.5M175.3 234.9h2.5M175.3 237.5h2.5M177.8 226.1h15.2v27.9h-15.2zM185.4 223.5h.1M185.4 221v5.1M185.4 221l-.7 1.2"/>
<path d="M185.4 221l.8 1.2M193 228.6h2.6M193 236.2h2.6M107.9 243.8v1.3h1.3l-1.3 1.3-1.2-1.3h1.2M107.9 243.8h.1M175.3 242.6h2.5M175.3 245.1h2.5M175.3 250.2h2.5M175.3 252.7h2.5M185.4 254v2.5M193 243.8h2.6M193 251.5h2.6"/>
</g>
<path d="M194.5 251.1h.6" fill="none" stroke="#a90000" stroke-width=".18"/>
<path d="M188.1 217.7l-.4 1.3M198.3 224.1h.5l.3 .2-.2 .4-.6 .1M198.6 224.8l.5 .6" fill="none" stroke="#006464" stroke-width=".18"/>
<path d="M31.7 71.1h15.3v22.9h-15.3z" fill="#ffffc2"/>
<path d="M31.7 71.1h15.3v22.9h-15.3z" fill="none" stroke="#840000" stroke-width=".25"/>
<g fill="none" stroke="#840000" stroke-width=".18">
<path d="M95.2 40.6v-1.2l-1.2 1.2 1.2 1.3v-1.3h1.3M96.5 40.6h.1M29.2 73.7h2.5M29.2 76.2h2.5M29.2 78.7h2.5M39.4 68.6v2.5M47 73.7h2.5M47 76.2h2.5M47 78.7h2.5M29.2 86.4h2.5M29.2 88.9h2.5M29.2 91.4h2.5"/>
<path d="M39.4 94v2.5M47 86.4h2.5M47 88.9h2.5M47 91.4h2.5M47 81.3h2.5M47 83.8h2.5M185.4 210.8v1.3h1.3l-1.3 1.3-1.3-1.3h1.3M185.4 210.8h.1"/>
</g>
<path d="M59.3 68h.5M59.6 68.6h.2v.4l-.2 .2-.3-.1M32.5 85.3h2.1" fill="none" stroke="#006464" stroke-width=".18"/>
<path d="M48.5 83.4h.7" fill="none" stroke="#a90000" stroke-width=".18"/>
<path d="M100.3 166.4h15.3v27.9h-15.3z" fill="#ffffc2"/>
<g fill="none" stroke="#840000" stroke-width=".18">
<path d="M260.3 148.6h.1M260.3 146.1l-.7 1.2M260.3 146.1l.8 1.2M260.3 146.1v2.5M97.8 167.6h2.5M97.8 170.2h2.5M97.8 175.3h2.5M97.8 177.8h2.5M100.3 166.4h15.3v27.9h-15.3zM107.9 163.8v2.6M115.6 168.9h2.5M115.6 176.5h2.5"/>
<path d="M39.4 199.4l-.8 1.3M39.4 199.4l.7 1.3M39.4 199.4v2.5M97.8 182.9h2.5M97.8 185.4h2.5M97.8 190.5h2.5M97.8 193h2.5M107.9 194.3v2.6M115.6 184.2h2.5M115.6 191.8h2.5M39.4 201.9h.1M185.4 256.5v1.3h1.3l-1.3 1.3-1.3-1.3h1.3"/>
<path d="M185.4 256.5h.1"/>
</g>
<path d="M117 191.4h.6" fill="none" stroke="#a90000" stroke-width=".18"/>
<path d="M263.1 142.8l-.5 1.3M120.9 164.4h.4l.3 .3-.1 .3-.6 .1M121.2 165.1l.4 .6M42.1 196.2l-.4 1.2" fill="none" stroke="#006464" stroke-width=".18"/>
<path d="M31.7 204.5h15.3v22.8h-15.3z" fill="#ffffc2"/>
<path d="M31.7 204.5h15.3v22.8h-15.3z" fill="none" stroke="#840000" stroke-width=".25"/>
<g fill="none" stroke="#840000" stroke-width=".18">
<path d="M228.6 165.1v1.3h1.3l-1.3 1.2-1.3-1.2h1.3M228.6 165.1h.1M228.6 177.8h.1M228.6 175.3l-.8 1.2M228.6 175.3l.8 1.2M228.6 175.3v2.5M260.3 181.6v1.3h1.3l-1.3 1.3-1.2-1.3h1.2M260.3 181.6h.1M283.2 180.3v-1.2l-1.3 1.2 1.3 1.3v-1.3h1.3M284.5 180.3h.1M29.2 207h2.5M29.2 209.6h2.5"/>
<path d="M29.2 212.1h2.5M29.2 219.7h2.5M39.4 201.9v2.6M47 207h2.5M47 209.6h2.5M47 212.1h2.5M47 219.7h2.5M47 214.6h2.5M47 217.2h2.5M228.6 210.8v1.3h1.3l-1.3 1.3-1.3-1.3h1.3M228.6 210.8h.1M29.2 222.2h2.5"/>
<path d="M29.2 224.8h2.5M39.4 229.9v1.2h1.2l-1.2 1.3-1.3-1.3h1.3M39.4 229.9h.1M39.4 227.3v2.6M47 222.2h2.5M47 224.8h2.5M39.4 246.4h.1M39.4 243.8v2.6M39.4 243.8l-.8 1.3M39.4 243.8l.7 1.3"/>
</g>
<path d="M231.3 172l-.4 1.3M32.5 218.7h2.1M59.3 201.3h.5M59.6 202h.2v.4l-.2 .1-.3-.1M42.1 240.6l-.4 1.3" fill="none" stroke="#006464" stroke-width=".18"/>
<path d="M48.5 216.8h.7" fill="none" stroke="#a90000" stroke-width=".18"/>
<path d="M221 180.3h15.2v28h-15.2z" fill="#ffffc2"/>
<g fill="none" stroke="#840000" stroke-width=".18">
<path d="M212.1 29.2h5.1M212.1 31.8h5.1M212.1 39.4h5.1M212.1 36.8h5.1M212.1 34.3h5.1M212.1 26.7h5.1M212.1 21.6h5.1M212.1 24.1h5.1M212.1 47h5.1M212.1 44.5h5.1M212.1 49.5h5.1M212.1 41.9h5.1"/>
<path d="M228.6 177.8v2.5M218.4 181.6h2.6M218.4 184.2h2.6M218.4 189.2h2.6M218.4 191.8h2.6M218.4 196.9h2.6M218.4 199.4h2.6M221 180.3h15.2v28h-15.2zM236.2 182.9h2.6M236.2 190.5h2.6M236.2 198.1h2.6M218.4 204.5h2.6"/>
<path d="M218.4 207h2.6M228.6 208.3v2.5M236.2 205.7h2.6"/>
</g>
<path d="M237.7 205.4h.6" fill="none" stroke="#a90000" stroke-width=".18"/>
<path d="M225.8 178.4h.4l.3 .2-.1 .4h-.6M226.1 179l.4 .6" fill="none" stroke="#006464" stroke-width=".18"/>
<path d="M213.4 29.2h2.5M213.4 31.8h2.5M213.4 39.4h2.5M213.4 36.8h2.5M213.4 34.3h2.5M213.4 26.7h2.5M213.4 21.6h2.5M213.4 24.1h2.5M213.4 47h2.5M213.4 44.5h2.5M213.4 49.5h2.5M213.4 41.9h2.5" fill="none" stroke="#840000" stroke-width=".25"/>
<path d="M31.7 248.9h15.3v22.9h-15.3z" fill="#ffffc2"/>
<path d="M31.7 248.9h15.3v22.9h-15.3z" fill="none" stroke="#840000" stroke-width=".25"/>
<g fill="none" stroke="#840000" stroke-width=".18">
<path d="M107.9 69.9h.1M107.9 67.3l-.7 1.3M107.9 67.3l.8 1.3M107.9 67.3v2.6M29.2 251.5h2.5M29.2 254h2.5M29.2 256.5h2.5M39.4 246.4v2.5M47 251.5h2.5M47 254h2.5M47 256.5h2.5M47 259.1h2.5"/>
<path d="M26.7 265.4v-1.2l-1.3 1.2 1.3 1.3v-1.3h1.2M27.9 265.4h.1M29.2 264.2h2.5M29.2 266.7h2.5M29.2 269.2h2.5M39.4 271.8v2.5M47 264.2h2.5M47 266.7h2.5M47 269.2h2.5M47 261.6h2.5"/>
</g>
<path d="M110.7 64.1l-.5 1.2M59.3 245.8h.5M59.6 246.4h.2v.4l-.2 .2-.3-.1M32.5 263.1h2.1" fill="none" stroke="#006464" stroke-width=".18"/>
<path d="M48.5 261.2h.7" fill="none" stroke="#a90000" stroke-width=".18"/>
<path d="M100.3 72.4h15.3v27.9h-15.3z" fill="#ffffc2"/>
<g fill="none" stroke="#840000" stroke-width=".18">
<path d="M39.4 19.1v2.5M39.4 19.1l-.8 1.2M39.4 19.1l.7 1.2M39.4 21.6h.1M151.1 26.7h5.1M151.1 24.1h5.1M152.4 31.8h5.1M152.4 36.8h5.1M152.4 29.2h5.1M152.4 34.3h5.1M152.4 39.4h5.1M39.4 49.5v1.3h1.2l-1.2 1.3-1.3-1.3h1.3"/>
<path d="M39.4 49.5h.1M152.4 41.9h5.1M152.4 47h5.1M152.4 44.5h5.1M152.4 49.5h5.1M152.4 57.2h5.1M152.4 52.1h5.1M152.4 54.6h5.1M39.4 68.6h.1M39.4 66l-.8 1.3M39.4 66l.7 1.3M39.4 66v2.6"/>
<path d="M97.8 73.7h2.5M97.8 76.2h2.5M100.3 72.4h15.3v27.9h-15.3zM107.9 69.9v2.5M115.6 74.9h2.5M97.8 81.3h2.5M97.8 83.8h2.5M97.8 88.9h2.5M97.8 91.4h2.5M97.8 96.5h2.5M97.8 99.1h2.5M115.6 82.6h2.5"/>
<path d="M115.6 90.2h2.5M115.6 97.8h2.5M107.9 100.3v2.6"/>
</g>
<path d="M117 97.4h.6" fill="none" stroke="#a90000" stroke-width=".18"/>
<path d="M42.1 15.8l-.4 1.3M42.1 62.8l-.4 1.3M120.9 70.4h.4l.3 .3-.1 .3-.6 .1M121.2 71.1l.4 .6" fill="none" stroke="#006464" stroke-width=".18"/>
<g fill="none" stroke="#840000" stroke-width=".25">
<path d="M152.4 26.7h2.5M152.4 24.1h2.5M153.7 31.8h2.5M153.7 36.8h2.5M153.7 29.2h2.5M153.7 34.3h2.5M153.7 39.4h2.5M153.7 41.9h2.5M153.7 47h2.5M153.7 44.5h2.5M153.7 49.5h2.5M153.7 57.2h2.5"/>
<path d="M153.7 52.1h2.5M153.7 54.6h2.5"/>
</g>
<path d="M31.7 24.1h15.3v22.9h-15.3z" fill="#ffffc2"/>
<path d="M31.7 24.1h15.3v22.9h-15.3zM152.4 21.6h2.5" fill="none" stroke="#840000" stroke-width=".25"/>
<g fill="none" stroke="#840000" stroke-width=".18">
<path d="M29.2 26.7h2.5M29.2 29.2h2.5M29.2 31.8h2.5M29.2 39.4h2.5M39.4 21.6v2.5M47 26.7h2.5M47 29.2h2.5M47 31.8h2.5M47 39.4h2.5M47 34.3h2.5M47 36.8h2.5M151.1 21.6h5.1"/>
<path d="M26.7 40.6v-1.2l-1.3 1.2 1.3 1.3v-1.3h1.2M27.9 40.6h.1M29.2 41.9h2.5M29.2 44.5h2.5M39.4 47v2.5M47 41.9h2.5M47 44.5h2.5M26.7 87.6v-1.2l-1.3 1.2 1.3 1.3v-1.3h1.2M27.9 87.6h.1"/>
</g>
<path d="M32.5 38.3h2.1M59.3 21h.5M59.6 21.6h.2v.4l-.2 .2-.3-.1" fill="none" stroke="#006464" stroke-width=".18"/>
<path d="M48.5 36.4h.7" fill="none" stroke="#a90000" stroke-width=".18"/>
<path d="M100.3 24.1h15.3v22.9h-15.3z" fill="#ffffc2"/>
<path d="M100.3 24.1h15.3v22.9h-15.3z" fill="none" stroke="#840000" stroke-width=".25"/>
<g fill="none" stroke="#840000" stroke-width=".18">
<path d="M107.9 19.1v5M107.9 19.1l-.7 1.2M107.9 19.1l.8 1.2M24.5 27.9h3.6l1.1 1.3-1.1 1.3h-3.6zM24.5 30.5h3.6l1.1 1.3-1.1 1.2h-3.6zM24.5 25.4h3.6l1.1 1.3-1.1 1.2h-3.6zM29.2 26.7h2.5M29.2 29.2h2.5M29.2 31.8h2.5M29.2 39.4h2.5M39.4 21.6h.1M39.4 21.6v2.5"/>
<path d="M47 26.7h2.5M47 29.2h2.5M47 31.8h2.5M47 39.4h2.5M47 34.3h2.5M47 36.8h2.5M50.6 30.5h12.5v2.5h-12.5l-1.1-1.2zM50.6 38.1h12.5v2.5h-12.5l-1.1-1.2zM50.6 35.6h12.5v2.5h-12.5l-1.1-1.3zM50.6 33h12.5v2.6h-12.5l-1.1-1.3zM50.6 25.4h12.5v2.5h-12.5l-1.1-1.2zM50.6 27.9h12.5v2.6h-12.5l-1.1-1.3z"/>
<path d="M93 27.9h3.7l1.1 1.3-1.1 1.3h-3.7zM93 30.5h3.7l1.1 1.3-1.1 1.2h-3.7zM93 25.4h3.7l1.1 1.3-1.1 1.2h-3.7zM97.8 26.7h2.5M97.8 29.2h2.5M97.8 31.8h2.5M97.8 39.4h2.5M107.9 21.6h.1M115.6 26.7h2.5M115.6 29.2h2.5M115.6 31.8h2.5M115.6 39.4h2.5"/>
<path d="M115.6 34.3h2.5M115.6 36.8h2.5M119.2 27.9h4.9v2.6h-4.9l-1.1-1.3zM119.2 30.5h4.9v2.5h-4.9l-1.1-1.2zM119.2 25.4h4.9v2.5h-4.9l-1.1-1.2zM146.4 25.4h3.6l1.1 1.3-1.1 1.2h-3.6zM146.4 20.3h3.6l1.1 1.3-1.1 1.3h-3.6zM146.4 22.9h3.6l1.1 1.2-1.1 1.3h-3.6zM146.4 38.1h4.9l1.1 1.3-1.1 1.2h-4.9zM146.4 30.5h4.9l1.1 1.3-1.1 1.2h-4.9zM146.4 27.9h4.9l1.1 1.3-1.1 1.3h-4.9zM146.4 33h4.9l1.1 1.3-1.1 1.3h-4.9z"/>
<path d="M146.4 35.6h4.9l1.1 1.2-1.1 1.3h-4.9zM158.6 25.4h19.4v2.5h-19.4l-1.1-1.2zM158.6 35.6h19.4v2.5h-19.4l-1.1-1.3zM158.6 22.9h19.4v2.5h-19.4l-1.1-1.3zM158.6 30.5h24v2.5h-24l-1.1-1.2zM158.6 33h19.4v2.6h-19.4l-1.1-1.3zM158.6 20.3h24.4v2.6h-24.4l-1.1-1.3zM158.6 27.9h25.5v2.6h-25.5l-1.1-1.3zM158.6 38.1h24.1v2.5h-24.1l-1.1-1.2zM176.2 26.1h.8M176.2 36.2h.8M176.2 23.5h.8"/>
<path d="M176.2 33.7h.8M180.8 31.2h.8M180.9 38.8h.7M181.3 21h.7M207.2 25.4h4.9v2.5h-4.9zM207.2 27.9h4.9v2.6h-4.9zM207.2 30.5h4.9v2.5h-4.9zM207.2 35.6h4.9v2.5h-4.9zM207.2 38.1h4.9v2.5h-4.9zM207.2 33h4.9v2.6h-4.9zM208.5 20.3h3.6v2.6h-3.6zM208.5 22.9h3.6v2.5h-3.6z"/>
<path d="M217.2 27.9h14.5v2.6h-14.5zM217.2 33h15.7v2.6h-15.7zM217.2 20.3h8.6v2.6h-8.6zM217.2 25.4h14.5v2.5h-14.5zM217.2 30.5h15.7v2.5h-15.7zM217.2 22.9h14.5v2.5h-14.5zM217.2 35.6h15.7v2.5h-15.7zM217.2 38.1h15.7v2.5h-15.7zM230.1 26.1h.7M230.6 29.9l.1 .1M230.6 28.8v.9M230.6 23.7v.9"/>
<path d="M230.6 24.9h.1M18.6 43.2h9.5l1.1 1.3-1.1 1.2h-9.5zM27.4 44.3v1l-.3 .2h-.3M27.4 44.3h-.4l-.2 .2 .1 .6h.5M29.2 41.9h2.5M29.2 44.5h2.5M39.4 49.5h.1M39.4 47v2.5M47 41.9h2.5M47 44.5h2.5M50.6 40.6h21.1v2.6h-21.1l-1.1-1.3zM50.6 43.2h21.1v2.5h-21.1l-1.1-1.2z"/>
<path d="M84.2 43.2h12.5l1.1 1.3-1.1 1.2h-12.5zM97.8 41.9h2.5M97.8 44.5h2.5M107.9 49.5v1.3h1.3l-1.3 1.3-1.2-1.3h1.2M107.9 49.5h.1M107.9 47v2.5M115.6 41.9h2.5M115.6 44.5h2.5M146.4 48.3h4.9l1.1 1.2-1.1 1.3h-4.9zM146.4 50.8h4.9l1.1 1.3-1.1 1.2h-4.9zM146.4 53.3h4.9l1.1 1.3-1.1 1.3h-4.9zM146.4 55.9h4.9l1.1 1.3-1.1 1.2h-4.9z"/>
<path d="M146.4 40.6h4.9l1.1 1.3-1.1 1.3h-4.9zM146.4 45.7h4.9l1.1 1.3-1.1 1.3h-4.9zM146.4 43.2h4.9l1.1 1.3-1.1 1.2h-4.9zM158.6 53.3h20.8v2.6h-20.8l-1.1-1.3zM158.6 40.6h24.6v2.6h-24.6l-1.1-1.3zM158.6 45.7h18.2v2.6h-18.2l-1.1-1.3zM158.6 48.3h22.9v2.5h-22.9l-1.1-1.3zM158.6 50.8h24v2.5h-24l-1.1-1.2zM158.6 43.2h22.8v2.5h-22.8l-1.1-1.2zM158.6 55.9h25.3v2.5h-25.3l-1.1-1.2zM175 46.4h.8M175.4 46.4v1.3"/>
<path d="M179.8 48.9h.7M180.8 51.5h.8M181.4 41.3h.8M181.8 41.3v1.3M182.1 56.6h.7M207.2 43.2h4.9v2.5h-4.9zM207.2 45.7h4.9v2.6h-4.9zM207.2 48.3h4.9v2.5h-4.9zM207.2 40.6h4.9v2.6h-4.9zM217.2 43.2h11.6v2.5h-11.6zM217.2 40.6h14.4v2.6h-14.4zM217.2 45.7h11.6v2.6h-11.6z"/>
<path d="M217.2 48.3h8.6v2.5h-8.6zM224.9 48.9l-.4 1.3M227.3 47l.4 .1 .1 .3-.3 .3h-.3M227.3 46.4l.5 .1M230 42.2h.6M230.3 41.3l.4 1.3M24.5 72.4h3.6l1.1 1.3-1.1 1.2h-3.6zM24.5 77.5h3.6l1.1 1.2-1.1 1.3h-3.6zM24.5 74.9h3.6l1.1 1.3-1.1 1.3h-3.6zM29.2 73.7h2.5M29.2 76.2h2.5M29.2 78.7h2.5"/>
<path d="M39.4 68.6h.1M39.4 68.6v2.5M47 73.7h2.5M47 76.2h2.5M47 78.7h2.5M50.6 74.9h3.7v2.6h-3.7l-1.1-1.3zM50.6 72.4h12.3v2.5h-12.3l-1.1-1.2zM50.6 77.5h3.7v2.5h-3.7l-1.1-1.3zM93 74.9h3.7l1.1 1.3-1.1 1.3h-3.7zM93 72.4h3.7l1.1 1.3-1.1 1.2h-3.7zM97.8 73.7h2.5M97.8 76.2h2.5"/>
<path d="M107.9 69.9h.1M107.9 69.9v2.5M115.6 74.9h2.5M119.2 73.7h14.9v2.5h-14.9l-1.1-1.3zM132.7 74.3l.2 .3v.3l-.7 .7h.7M15.6 90.2h12.5l1.1 1.2-1.1 1.3h-12.5zM29.2 91.4h2.5M29.2 86.4h2.5M29.2 88.9h2.5M39.4 96.5h.1M39.4 94v2.5M47 91.4h2.5"/>
<path d="M47 86.4h2.5M47 88.9h2.5M47 81.3h2.5M47 83.8h2.5M50.6 87.6h3.7v2.6h-3.7l-1.1-1.3zM50.6 90.2h3.7v2.5h-3.7l-1.1-1.3zM50.6 80h3.7v2.6h-3.7l-1.1-1.3zM50.6 85.1h3.7v2.5h-3.7l-1.1-1.2zM50.6 82.5h3.7v2.6h-3.7l-1.1-1.3zM91.8 97.8h4.9l1.1 1.3-1.1 1.2h-4.9zM93 82.5h3.7l1.1 1.3-1.1 1.3h-3.7zM93 87.6h3.7l1.1 1.3-1.1 1.3h-3.7z"/>
<path d="M93 80h3.7l1.1 1.3-1.1 1.3h-3.7zM93 95.2h3.7l1.1 1.3-1.1 1.3h-3.7zM93 90.2h3.7l1.1 1.2-1.1 1.3h-3.7zM97.8 91.4h2.5M97.8 99.1h2.5M97.8 88.9h2.5M97.8 81.3h2.5M97.8 83.8h2.5M97.8 96.5h2.5M115.6 90.2h2.5M115.6 97.8h2.5M115.6 82.6h2.5"/>
<path d="M119.2 88.9h9.9v2.5h-9.9l-1.1-1.2zM119.2 96.5h15.9v2.6h-15.9l-1.1-1.3zM119.2 81.3h9.9v2.5h-9.9l-1.1-1.2zM127.1 82h.8l-.4 .4M127.6 89.6a.79 .79 0 0 1 0 1.2M127.7 82.4l.2 .3v.3l-.2 .2M170.5 91.4h3.6l1.2 1.3-1.2 1.3h-3.6zM170.5 99.1h3.6l1.2 1.2-1.2 1.3h-3.6zM170.5 88.9h3.6l1.2 1.3-1.2 1.2h-3.6zM170.5 96.5h3.6l1.2 1.3-1.2 1.3h-3.6zM175.3 90.2h2.5M175.3 92.7h2.5"/>
<path d="M175.3 97.8h2.5M185.4 86.4h.1M185.4 86.4v2.5M193 91.4h2.6M193 99.1h2.6M24.5 119.4h3.6l1.1 1.3-1.1 1.2h-3.6zM24.5 116.8h3.6l1.1 1.3-1.1 1.3h-3.6zM29.2 118.1h2.5M39.4 113h.1M39.4 113v2.6M47 118.1h2.5M50.6 119.4h3.7v2.5h-3.7l-1.1-1.2z"/>
<path d="M50.6 116.8h3.7v2.6h-3.7l-1.1-1.3zM91.8 119.4h4.9l1.1 1.3-1.1 1.2h-4.9zM107.9 102.9h.1M107.9 116.8h.1M107.9 100.3v2.6M107.9 116.8v2.6M169.3 111.8h4.8l1.2 1.2-1.2 1.3h-4.8zM169.3 114.3h4.8l1.2 1.3-1.2 1.2h-4.8zM170.5 106.7h3.6l1.2 1.3-1.2 1.2h-3.6zM170.5 104.1h3.6l1.2 1.3-1.2 1.3h-3.6zM175.3 100.3h2.5M175.3 105.4h2.5"/>
<path d="M175.3 108h2.5M175.3 113h2.5M175.3 115.6h2.5M185.4 119.4h.1M185.4 116.8v2.6M193 106.7h2.6M193 114.3h2.6M15.6 134.6h12.5l1.1 1.3-1.1 1.3h-12.5zM24.5 121.9h3.6l1.1 1.3-1.1 1.3h-3.6zM29.2 135.9h2.5M29.2 120.7h2.5M29.2 123.2h2.5"/>
<path d="M29.2 130.8h2.5M29.2 133.4h2.5M39.4 138.4v2.6M47 135.9h2.5M47 120.7h2.5M47 123.2h2.5M47 128.3h2.5M47 130.8h2.5M47 133.4h2.5M47 125.7h2.5M50.6 124.5h4.9v2.5h-4.9l-1.1-1.3zM50.6 121.9h4.9v2.6h-4.9l-1.1-1.3z"/>
<path d="M50.6 129.5h4.9v2.6h-4.9l-1.1-1.3zM50.6 134.6h4.9v2.6h-4.9l-1.1-1.3zM50.6 132.1h4.9v2.5h-4.9l-1.1-1.2zM50.6 127h4.9v2.5h-4.9l-1.1-1.2zM91.8 137.2h4.9l1.1 1.2-1.1 1.3h-4.9zM91.8 129.5h4.9l1.1 1.3-1.1 1.3h-4.9zM91.8 121.9h4.9l1.1 1.3-1.1 1.3h-4.9zM91.8 127h4.9l1.1 1.3-1.1 1.2h-4.9zM91.8 134.6h4.9l1.1 1.3-1.1 1.3h-4.9zM97.8 135.9h2.5M97.8 138.4h2.5M97.8 120.7h2.5"/>
<path d="M97.8 123.2h2.5M97.8 128.3h2.5M97.8 130.8h2.5M115.6 137.2h2.5M115.6 121.9h2.5M115.6 129.5h2.5M119.2 135.9h9.9v2.5h-9.9l-1.1-1.2zM119.2 128.3h9.9v2.5h-9.9l-1.1-1.3zM119.2 120.6h14.5v2.6h-14.5l-1.1-1.3zM127.3 136.6h.6M127.7 137l.2 .3v.3l-.2 .2M127.7 128.9l.2 .3-.2 .3 .2 .2v.3l-.2 .2"/>
<path d="M132.2 121.3l.1 .1a.81 .81 0 0 1-.1 1.2M169.3 137.2h4.8l1.2 1.2-1.2 1.3h-4.8zM169.3 134.6h4.8l1.2 1.3-1.2 1.3h-4.8zM175.3 135.9h2.5M175.3 138.4h2.5M185.4 132.1h.1M185.4 132.1v2.5M193 137.2h2.6M218.4 135.9h2.6M218.4 138.4h2.6M228.6 132.1h.1M228.6 132.1v2.5"/>
<path d="M236.2 137.2h2.6M39.4 157.5h.1M39.4 141h.1M39.4 157.5v2.5M91.8 144.8h4.9l1.1 1.3-1.1 1.2h-4.9zM91.8 142.2h4.9l1.1 1.3-1.1 1.3h-4.9zM97.8 143.5h2.5M97.8 146.1h2.5M107.9 149.9h.1M107.9 147.3v2.6M115.6 144.8h2.5M119.2 143.5h14.5v2.6h-14.5l-1.1-1.3z"/>
<path d="M132.5 145.5l.1 .1M132.5 144.4v.9M169.3 144.8h4.8l1.2 1.3-1.2 1.2h-4.8zM169.3 157.5h4.8l1.2 1.3-1.2 1.2h-4.8zM169.3 149.9h4.8l1.2 1.2-1.2 1.3h-4.8zM169.3 152.4h4.8l1.2 1.3-1.2 1.2h-4.8zM169.3 142.2h4.8l1.2 1.3-1.2 1.3h-4.8zM175.3 158.8h2.5M175.3 143.5h2.5M175.3 146.1h2.5M175.3 151.1h2.5M175.3 153.7h2.5"/>
<path d="M193 144.8h2.6M193 152.4h2.6M218.4 158.8h2.6M218.4 143.5h2.6M218.4 146.1h2.6M218.4 151.1h2.6M218.4 153.7h2.6M236.2 144.8h2.6M236.2 152.4h2.6M250.2 152.4h2.5M250.2 154.9h2.5M260.3 148.6h.1"/>
<path d="M260.3 148.6v2.5M268 153.7h2.5M287 156.2h2.6M287 158.8h2.6M297.2 152.4h.1M297.2 152.4v2.5M304.8 157.5h2.5M15.6 179.1h12.5l1.1 1.2-1.1 1.3h-12.5zM24.5 163.8h3.6l1.1 1.3-1.1 1.3h-3.6zM24.5 166.4h3.6l1.1 1.2-1.1 1.3h-3.6zM24.5 161.3h3.6l1.1 1.3-1.1 1.2h-3.6zM29.2 165.1h2.5"/>
<path d="M29.2 162.6h2.5M29.2 167.6h2.5M29.2 175.3h2.5M29.2 177.8h2.5M47 165.1h2.5M47 172.7h2.5M47 162.6h2.5M47 167.6h2.5M47 170.2h2.5M47 175.3h2.5M47 177.8h2.5M50.6 166.4h4.9v2.5h-4.9l-1.1-1.3z"/>
<path d="M50.6 163.8h4.9v2.6h-4.9l-1.1-1.3zM50.6 168.9h4.9v2.6h-4.9l-1.1-1.3zM50.6 161.3h4.9v2.5h-4.9l-1.1-1.2zM50.6 174h4.9v2.5h-4.9l-1.1-1.2zM50.6 171.4h4.9v2.6h-4.9l-1.1-1.3zM50.6 176.5h4.9v2.6h-4.9l-1.1-1.3zM50.6 179.1h4.9v2.5h-4.9l-1.1-1.3zM91.8 166.4h4.9l1.1 1.2-1.1 1.3h-4.9zM91.8 174h4.9l1.1 1.3-1.1 1.2h-4.9zM91.8 168.9h4.9l1.1 1.3-1.1 1.3h-4.9zM91.8 176.5h4.9l1.1 1.3-1.1 1.3h-4.9zM97.8 167.6h2.5"/>
<path d="M97.8 170.2h2.5M97.8 175.3h2.5M97.8 177.8h2.5M107.9 163.8h.1M107.9 163.8v2.6M115.6 168.9h2.5M115.6 176.5h2.5M119.2 167.6h15.1v2.6h-15.1l-1.1-1.3zM119.2 175.3h13.3v2.5h-13.3l-1.1-1.3zM132.6 169.5h.5M132.6 168.8l.3-.1 .2 .3-.6 .2M169.3 160h4.8l1.2 1.3-1.2 1.3h-4.8z"/>
<path d="M175.3 161.3h2.5M185.4 165.1h.1M185.4 177.8h.1M185.4 162.6v2.5M185.4 177.8v2.5M193 160h2.6M218.4 161.3h2.6M228.6 165.1h.1M228.6 177.8h.1M228.6 162.6v2.5M228.6 177.8v2.5M236.2 160h2.6"/>
<path d="M250.2 160h2.5M250.2 162.6h2.5M250.2 167.6h2.5M250.2 170.2h2.5M250.2 175.3h2.5M250.2 177.8h2.5M260.3 179.1v2.5M268 161.3h2.5M268 168.9h2.5M268 176.5h2.5M287 163.8h2.6M287 166.4h2.6"/>
<path d="M287 171.5h2.6M287 174h2.6M287 179.1h2.6M304.8 165.1h2.5M304.8 172.7h2.5M308.5 171.4h8.6v2.6h-8.6l-1.2-1.3zM29.2 180.3h2.5M39.4 185.4h.1M39.4 182.9v2.5M47 180.3h2.5M91.8 181.6h4.9l1.1 1.3-1.1 1.3h-4.9zM91.8 189.2h4.9l1.1 1.3-1.1 1.3h-4.9z"/>
<path d="M91.8 191.8h4.9l1.1 1.2-1.1 1.3h-4.9zM91.8 184.1h4.9l1.1 1.3-1.1 1.3h-4.9zM97.8 182.9h2.5M97.8 190.5h2.5M97.8 185.4h2.5M97.8 193h2.5M107.9 196.9h.1M107.9 194.3v2.6M115.6 184.2h2.5M115.6 191.8h2.5M119.2 182.9h8.7v2.5h-8.7l-1.1-1.2zM119.2 190.5h13.4v2.5h-13.4l-1.1-1.2z"/>
<path d="M126 183.6l.4 1.2 .4-1.2M130.7 191.2h.5l.2 .2-.1 .4h-.6M169.3 198.1h4.8l1.2 1.3-1.2 1.3h-4.8zM169.3 188h4.8l1.2 1.2-1.2 1.3h-4.8zM169.3 190.5h4.8l1.2 1.3-1.2 1.2h-4.8zM169.3 182.9h4.8l1.2 1.3-1.2 1.2h-4.8zM169.3 195.6h4.8l1.2 1.3-1.2 1.2h-4.8zM169.3 180.3h4.8l1.2 1.3-1.2 1.3h-4.8zM175.3 181.6h2.5M175.3 184.2h2.5M175.3 189.2h2.5M175.3 191.8h2.5"/>
<path d="M175.3 196.9h2.5M175.3 199.4h2.5M193 182.9h2.6M193 190.5h2.6M193 198.1h2.6M218.4 181.6h2.6M218.4 184.2h2.6M218.4 189.2h2.6M218.4 191.8h2.6M218.4 196.9h2.6M218.4 199.4h2.6M236.2 182.9h2.6"/>
<path d="M236.2 190.5h2.6M236.2 198.1h2.6M260.3 181.6h.1M287 181.6h2.6M297.2 185.4h.1M297.2 182.9v2.5M304.8 180.3h2.5M24.5 208.3h3.6l1.1 1.3-1.1 1.2h-3.6zM24.5 210.8h3.6l1.1 1.3-1.1 1.3h-3.6zM24.5 205.7h3.6l1.1 1.3-1.1 1.3h-3.6zM29.2 207h2.5M29.2 209.6h2.5"/>
<path d="M29.2 212.1h2.5M29.2 219.7h2.5M39.4 201.9h.1M39.4 201.9v2.6M47 207h2.5M47 209.6h2.5M47 212.1h2.5M47 219.7h2.5M47 214.6h2.5M47 217.2h2.5M50.6 213.4h4.9v2.5h-4.9l-1.1-1.3zM50.6 208.3h4.9v2.5h-4.9l-1.1-1.2z"/>
<path d="M50.6 205.7h4.9v2.6h-4.9l-1.1-1.3zM50.6 210.8h4.9v2.6h-4.9l-1.1-1.3zM50.6 218.4h4.9v2.6h-4.9l-1.1-1.3zM50.6 215.9h4.9v2.5h-4.9l-1.1-1.2zM91.8 213.4h4.9l1.1 1.2-1.1 1.3h-4.9zM91.8 215.9h4.9l1.1 1.3-1.1 1.2h-4.9zM97.8 214.6h2.5M97.8 217.2h2.5M107.9 210.8h.1M107.9 210.8v2.6M115.6 215.9h2.5M119.2 214.6h11.3v2.6h-11.3l-1.1-1.3z"/>
<path d="M169.3 203.2h4.8l1.2 1.3-1.2 1.2h-4.8zM169.3 205.7h4.8l1.2 1.3-1.2 1.3h-4.8zM175.3 204.5h2.5M175.3 207h2.5M185.4 210.8h.1M185.4 208.3v2.5M193 205.7h2.6M218.4 204.5h2.6M218.4 207h2.6M228.6 210.8h.1M228.6 208.3v2.5M236.2 205.7h2.6"/>
<path d="M15.6 223.5h12.5l1.1 1.3-1.1 1.3h-12.5zM29.2 222.2h2.5M29.2 224.8h2.5M39.4 229.9h.1M39.4 227.3v2.6M47 222.2h2.5M47 224.8h2.5M50.6 221h4.9v2.5h-4.9l-1.1-1.3zM50.6 223.5h4.9v2.6h-4.9l-1.1-1.3zM91.8 221h4.9l1.1 1.2-1.1 1.3h-4.9zM91.8 231.1h4.9l1.1 1.3-1.1 1.3h-4.9zM91.8 228.6h4.9l1.1 1.3-1.1 1.2h-4.9z"/>
<path d="M91.8 223.5h4.9l1.1 1.3-1.1 1.3h-4.9zM97.8 222.2h2.5M97.8 224.8h2.5M97.8 229.9h2.5M97.8 232.4h2.5M97.8 237.5h2.5M115.6 223.5h2.5M115.6 231.1h2.5M115.6 238.8h2.5M119.2 222.2h14.5v2.6h-14.5l-1.1-1.3zM119.2 229.9h15.7v2.5h-15.7l-1.1-1.3zM132.2 222.9l.1 .1a.81 .81 0 0 1-.1 1.2"/>
<path d="M133 230.5h.8l-.4 .5 .3 .1 .1 .5-.3 .2h-.3M169.3 226.1h4.8l1.2 1.2-1.2 1.3h-4.8zM169.3 233.7h4.8l1.2 1.2-1.2 1.3h-4.8zM169.3 228.6h4.8l1.2 1.3-1.2 1.2h-4.8zM175.3 229.9h2.5M175.3 237.5h2.5M175.3 227.3h2.5M175.3 234.9h2.5M185.4 223.5h.1M185.4 223.5v2.6M193 228.6h2.6M193 236.2h2.6"/>
<path d="M24.5 255.3h3.6l1.1 1.2-1.1 1.3h-3.6zM24.5 252.7h3.6l1.1 1.3-1.1 1.3h-3.6zM24.5 250.2h3.6l1.1 1.3-1.1 1.2h-3.6zM29.2 251.5h2.5M29.2 254h2.5M29.2 256.5h2.5M39.4 246.4h.1M39.4 246.4v2.5M47 251.5h2.5M47 254h2.5M47 256.5h2.5M47 259.1h2.5"/>
<path d="M50.6 255.3h4.9v2.5h-4.9l-1.1-1.3zM50.6 252.7h4.9v2.6h-4.9l-1.1-1.3zM50.6 250.2h4.9v2.5h-4.9l-1.1-1.2zM50.6 257.8h4.9v2.6h-4.9l-1.1-1.3zM97.8 240h2.5M107.9 243.8h.1M107.9 241.3v2.5M175.3 242.6h2.5M175.3 245.1h2.5M175.3 250.2h2.5M175.3 252.7h2.5M185.4 256.5h.1"/>
<path d="M185.4 254v2.5M193 251.5h2.6M193 243.8h2.6M15.6 268h12.5l1.1 1.2-1.1 1.3h-12.5zM29.2 264.2h2.5M29.2 266.7h2.5M29.2 269.2h2.5M39.4 274.3h.1M39.4 271.8v2.5M47 264.2h2.5M47 266.7h2.5M47 269.2h2.5"/>
<path d="M47 261.6h2.5M50.6 262.9h4.9v2.5h-4.9l-1.1-1.2zM50.6 265.4h4.9v2.6h-4.9l-1.1-1.3zM50.6 260.3h4.9v2.6h-4.9l-1.1-1.3zM50.6 268h4.9v2.5h-4.9l-1.1-1.3z"/>
</g>
<g fill="none" stroke="#006464" stroke-width=".18">
<path d="M42.1 15.8l-.4 1.3M110.7 15.8l-.5 1.3M32.5 38.3h2.1M59.3 21h.5M59.6 21.6h.2v.4l-.2 .2-.3-.1M101.1 38.3h2.1M127.9 21h.4M128.2 21.6h.2v.4l-.2 .2-.3-.1M42.1 62.8l-.4 1.3M59.3 68h.5M59.6 68.6h.2v.4l-.2 .2-.3-.1M110.7 64.1l-.5 1.2"/>
<path d="M120.9 70.4h.4l.3 .3-.1 .3-.6 .1M121.2 71.1l.4 .6M32.5 85.3h2.1M188.1 80.6l-.4 1.3M198.3 86.9h.5l.3 .3-.2 .3-.6 .1M198.6 87.6l.5 .6M42.1 107.3l-.4 1.2M59.3 112.4h.5M59.6 113.1h.2v.4l-.2 .1-.3-.1M110.7 111.1l-.5 1.2M120.9 117.4h.4l.3 .3-.1 .3-.6 .1M121.2 118.1l.4 .6"/>
<path d="M32.5 129.8h2.1M188.1 126.3l-.4 1.3M198.3 132.7h.5l.3 .2-.2 .4h-.6M198.6 133.3l.5 .6M231.3 126.3l-.4 1.3M241.5 132.7h.5l.2 .2-.1 .4h-.6M241.8 133.3l.4 .6M42.1 151.7l-.4 1.3M59.3 156.9h.5M59.6 157.5h.2v.4l-.2 .2-.3-.1M110.7 158.1l-.5 1.2M263.1 142.8l-.5 1.3"/>
<path d="M273.3 149.2h.4l.3 .2-.1 .4h-.6M273.6 149.8l.4 .6M299.9 146.6l-.4 1.3M310.1 153h.5l.2 .2-.1 .4h-.6M310.4 153.6l.4 .6M32.5 174.2h2.1M120.9 164.4h.4l.3 .3-.1 .3-.6 .1M121.2 165.1l.4 .6M188.1 172l-.4 1.3M198.3 178.4h.5l.3 .2-.2 .4h-.6M198.6 179l.5 .6M225.8 178.4h.4l.3 .2-.1 .4h-.6"/>
<path d="M226.1 179l.4 .6M231.3 172l-.4 1.3M42.1 196.2l-.4 1.2M32.5 218.7h2.1M59.3 201.3h.5M59.6 202h.2v.4l-.2 .1-.3-.1M110.7 205l-.5 1.3M114.2 210.1h.7M120.9 211.4h.4l.3 .2-.1 .4-.6 .1M121.2 212.1l.4 .6M188.1 217.7l-.4 1.3M198.3 224.1h.5l.3 .2-.2 .4-.6 .1"/>
<path d="M198.6 224.8l.5 .6M42.1 240.6l-.4 1.3M59.3 245.8h.5M59.6 246.4h.2v.4l-.2 .2-.3-.1M32.5 263.1h2.1"/>
</g>
<g fill="none" stroke="#a90000" stroke-width=".18">
<path d="M48.5 36.4h.7M117.1 36.4h.7M48.5 83.4h.7M117 97.4h.6M194.5 113.9h.6M48.5 127.9h.7M117 144.4h.6M194.5 159.6h.6M237.7 159.6h.6M48.5 172.3h.7M269.4 176.1h.6M306.3 180h.5"/>
<path d="M117 191.4h.6M48.5 216.8h.7M194.5 205.4h.6M237.7 205.4h.6M117 238.4h.6M194.5 251.1h.6M48.5 261.2h.7"/>
</g>
<g fill="none" stroke="#0000c2" stroke-width=".18">
<path d="M339.1 124.5h62.2v115.5h-62.2zM339.1 129.5h62.2M349.2 124.5v115.5zM358.1 138.8h.8l-.4 .4M358.7 139.2l.2 .3v.3l-.2 .2M363.7 133.7l.2 .2v.3l-.8 .7h.8M363.7 136.2l.2 .3v.3l-.8 .7h.8M369.6 124.5v115.5zM395.7 136.2h.8M358.1 141.3h.8l-.4 .5M358.6 143.8a.79 .79 0 0 1 0 1.3M358.6 146.4a.79 .79 0 0 1 0 1.2"/>
<path d="M358.7 141.8l.2 .2v.3l-.2 .3M363.2 159.1h.1a.81 .81 0 0 1-.1 1.2M363.5 151.6v.9M363.5 152.8l.1 .1M390.7 146.4h.7M390.7 141.3h.7M358.2 171.8h.6M358.2 174.3h.6M358.7 172.3l.2 .2v.3l-.2 .2M358.7 166.7l.2 .2-.2 .3 .2 .3v.2l-.2 .3M358.7 169.2l.2 .3-.2 .3 .2 .2v.3l-.2 .2M358.7 174.8l.2 .2v.3l-.2 .3"/>
<path d="M363 164.2h.7M363.2 161.6l.1 .1a.81 .81 0 0 1-.1 1.2M363.5 179.6v.9M363.5 177v.9M363.5 178.2l.1 .1M390.7 174.3h.7M390.7 169.2h.7M395.3 161.6h.7M395.4 179.4h.7M363.5 180.7l.1 .1M363.5 182.1v.9M363.5 183.3h.1"/>
<path d="M363.6 188.2h.4M363.6 187.5l.3-.1 .2 .3-.6 .2M363.6 185l.3-.1 .2 .3-.6 .1M363.6 185.7h.4M395.9 187h.7M396.3 187v1.3M357 212.4l.4 1.3 .4-1.3M357 209.9l.4 1.2 .4-1.2M360.2 215.6l.3 .1 .2 .3-.3 .2h-.3M360.2 215h.5M361.7 217.5h.5l.2 .2-.1 .4-.6 .1M362.9 205.7h.6"/>
<path d="M363.2 204.8l.4 1.3M389.5 212.4h.7M389.9 212.4v1.3M357.8 222.6l-.4 1.2M361.7 220h.5l.2 .3-.1 .3-.6 .1M363.2 227.7h.1a.81 .81 0 0 1-.1 1.2M363.2 225.1l.1 .1a.81 .81 0 0 1-.1 1.2M366.3 235.3h.5l.2 .2-.1 .4h-.6M366.3 237.8h.5l.2 .3-.1 .3-.6 .1M366.6 235.9l.4 .6M366.6 238.5l.4 .6M386.6 237.6h.8l-.4 .4 .3 .2 .1 .4-.3 .2h-.3"/>
<path d="M394.2 220h.7M395.3 227.7h.7"/>
</g>
<g fill="none" stroke="#009600" stroke-width=".18">
<path d="M29.2 39.4v2.5M97.8 39.4v2.5M156.2 26.7h1.3M156.2 21.6h1.3M156.2 24.1h1.3M27.9 40.6h1.3M96.5 40.6h1.3M27.9 87.6h1.3M29.2 86.4v2.5M195.6 99.1h19v39.3h3.8M195.6 91.4h22.8v44.5M195.6 106.7h15.2v36.8h7.6"/>
<path d="M195.6 114.3h11.4v31.8h11.4M27.9 132.1h1.3M29.2 130.8v2.6M195.6 137.2h7.6v13.9h15.2M238.8 137.2h11.4v15.2M195.6 144.8h5.1v8.9h17.7M195.6 152.4h2.5v6.4h20.3M238.8 144.8h7.6v10.1h3.8M238.8 152.4h3.8v7.6h7.6M270.5 153.7h16.5v2.5M287 158.8h-16.5v2.5M307.3 157.5h7.7"/>
<path d="M27.9 176.5h1.3M29.2 175.3v2.5M195.6 160v1.3h22.8M238.8 160v2.6h11.4M250.2 177.8v27.9h-11.4M250.2 175.3h-3.8v22.8h-7.6M250.2 167.6h-11.4v15.3M250.2 170.2h-7.6v20.3h-3.8M285.7 171.5h1.3M285.7 174h1.3M287 179.1v1.2h-2.5M287 163.8h-16.5v5.1"/>
<path d="M287 166.4h-14v10.1h-2.5M307.3 165.1h7.7M218.4 199.4h-7.6v36.8h-15.2M218.4 196.9h-11.4v31.7h-11.4M218.4 191.8h-15.2v13.9h-7.6M218.4 189.2h-17.7v8.9h-5.1M218.4 184.2h-20.3v6.3h-2.5M218.4 181.6h-22.8v1.3M29.2 219.7v2.5M218.4 204.5h-3.8v39.3h-19M218.4 207v44.5h-22.8M27.9 221h1.3"/>
<path d="M97.8 237.5v1.3h-2.6M170.2 237.5h5.1M170.2 247.6h5.1M175.3 242.6v10.1M27.9 265.4h1.3M29.2 264.2v2.5"/>
</g>
<g fill="none" stroke="#000084" stroke-width=".18">
<path d="M117.5 33.7l1.2 1.2M117.5 38.8l1.2 1.2M117.5 36.2l1.2 1.2M118.7 33.7l-1.2 1.2M118.7 38.8l-1.2 1.2M118.7 36.2l-1.2 1.2M117.5 43.8l1.2 1.3M117.5 41.3l1.2 1.2M118.7 43.8l-1.2 1.3M118.7 41.3l-1.2 1.2M306.7 179.7l1.2 1.2M307.9 179.7l-1.2 1.2"/>
<path d="M117.5 238.2l1.2 1.2M118.7 238.2l-1.2 1.2"/>
</g>
<g fill="#009600" stroke="#009600" stroke-width=".18">
<circle cx="287" cy="180.3" r=".46"/>
<circle cx="29.2" cy="265.4" r=".46"/>
<circle cx="29.2" cy="221" r=".46"/>
<circle cx="29.2" cy="132.1" r=".46"/>
<circle cx="29.2" cy="176.5" r=".46"/>
<circle cx="97.8" cy="238.8" r=".46"/>
<circle cx="175.3" cy="247.6" r=".46"/>
<circle cx="175.3" cy="250.2" r=".46"/>
<circle cx="175.3" cy="245.1" r=".46"/>
<circle cx="97.8" cy="40.6" r=".46"/>
<circle cx="29.2" cy="40.6" r=".46"/>
<circle cx="29.2" cy="87.6" r=".46"/>
</g>
<use href="#words"/>
</svg>
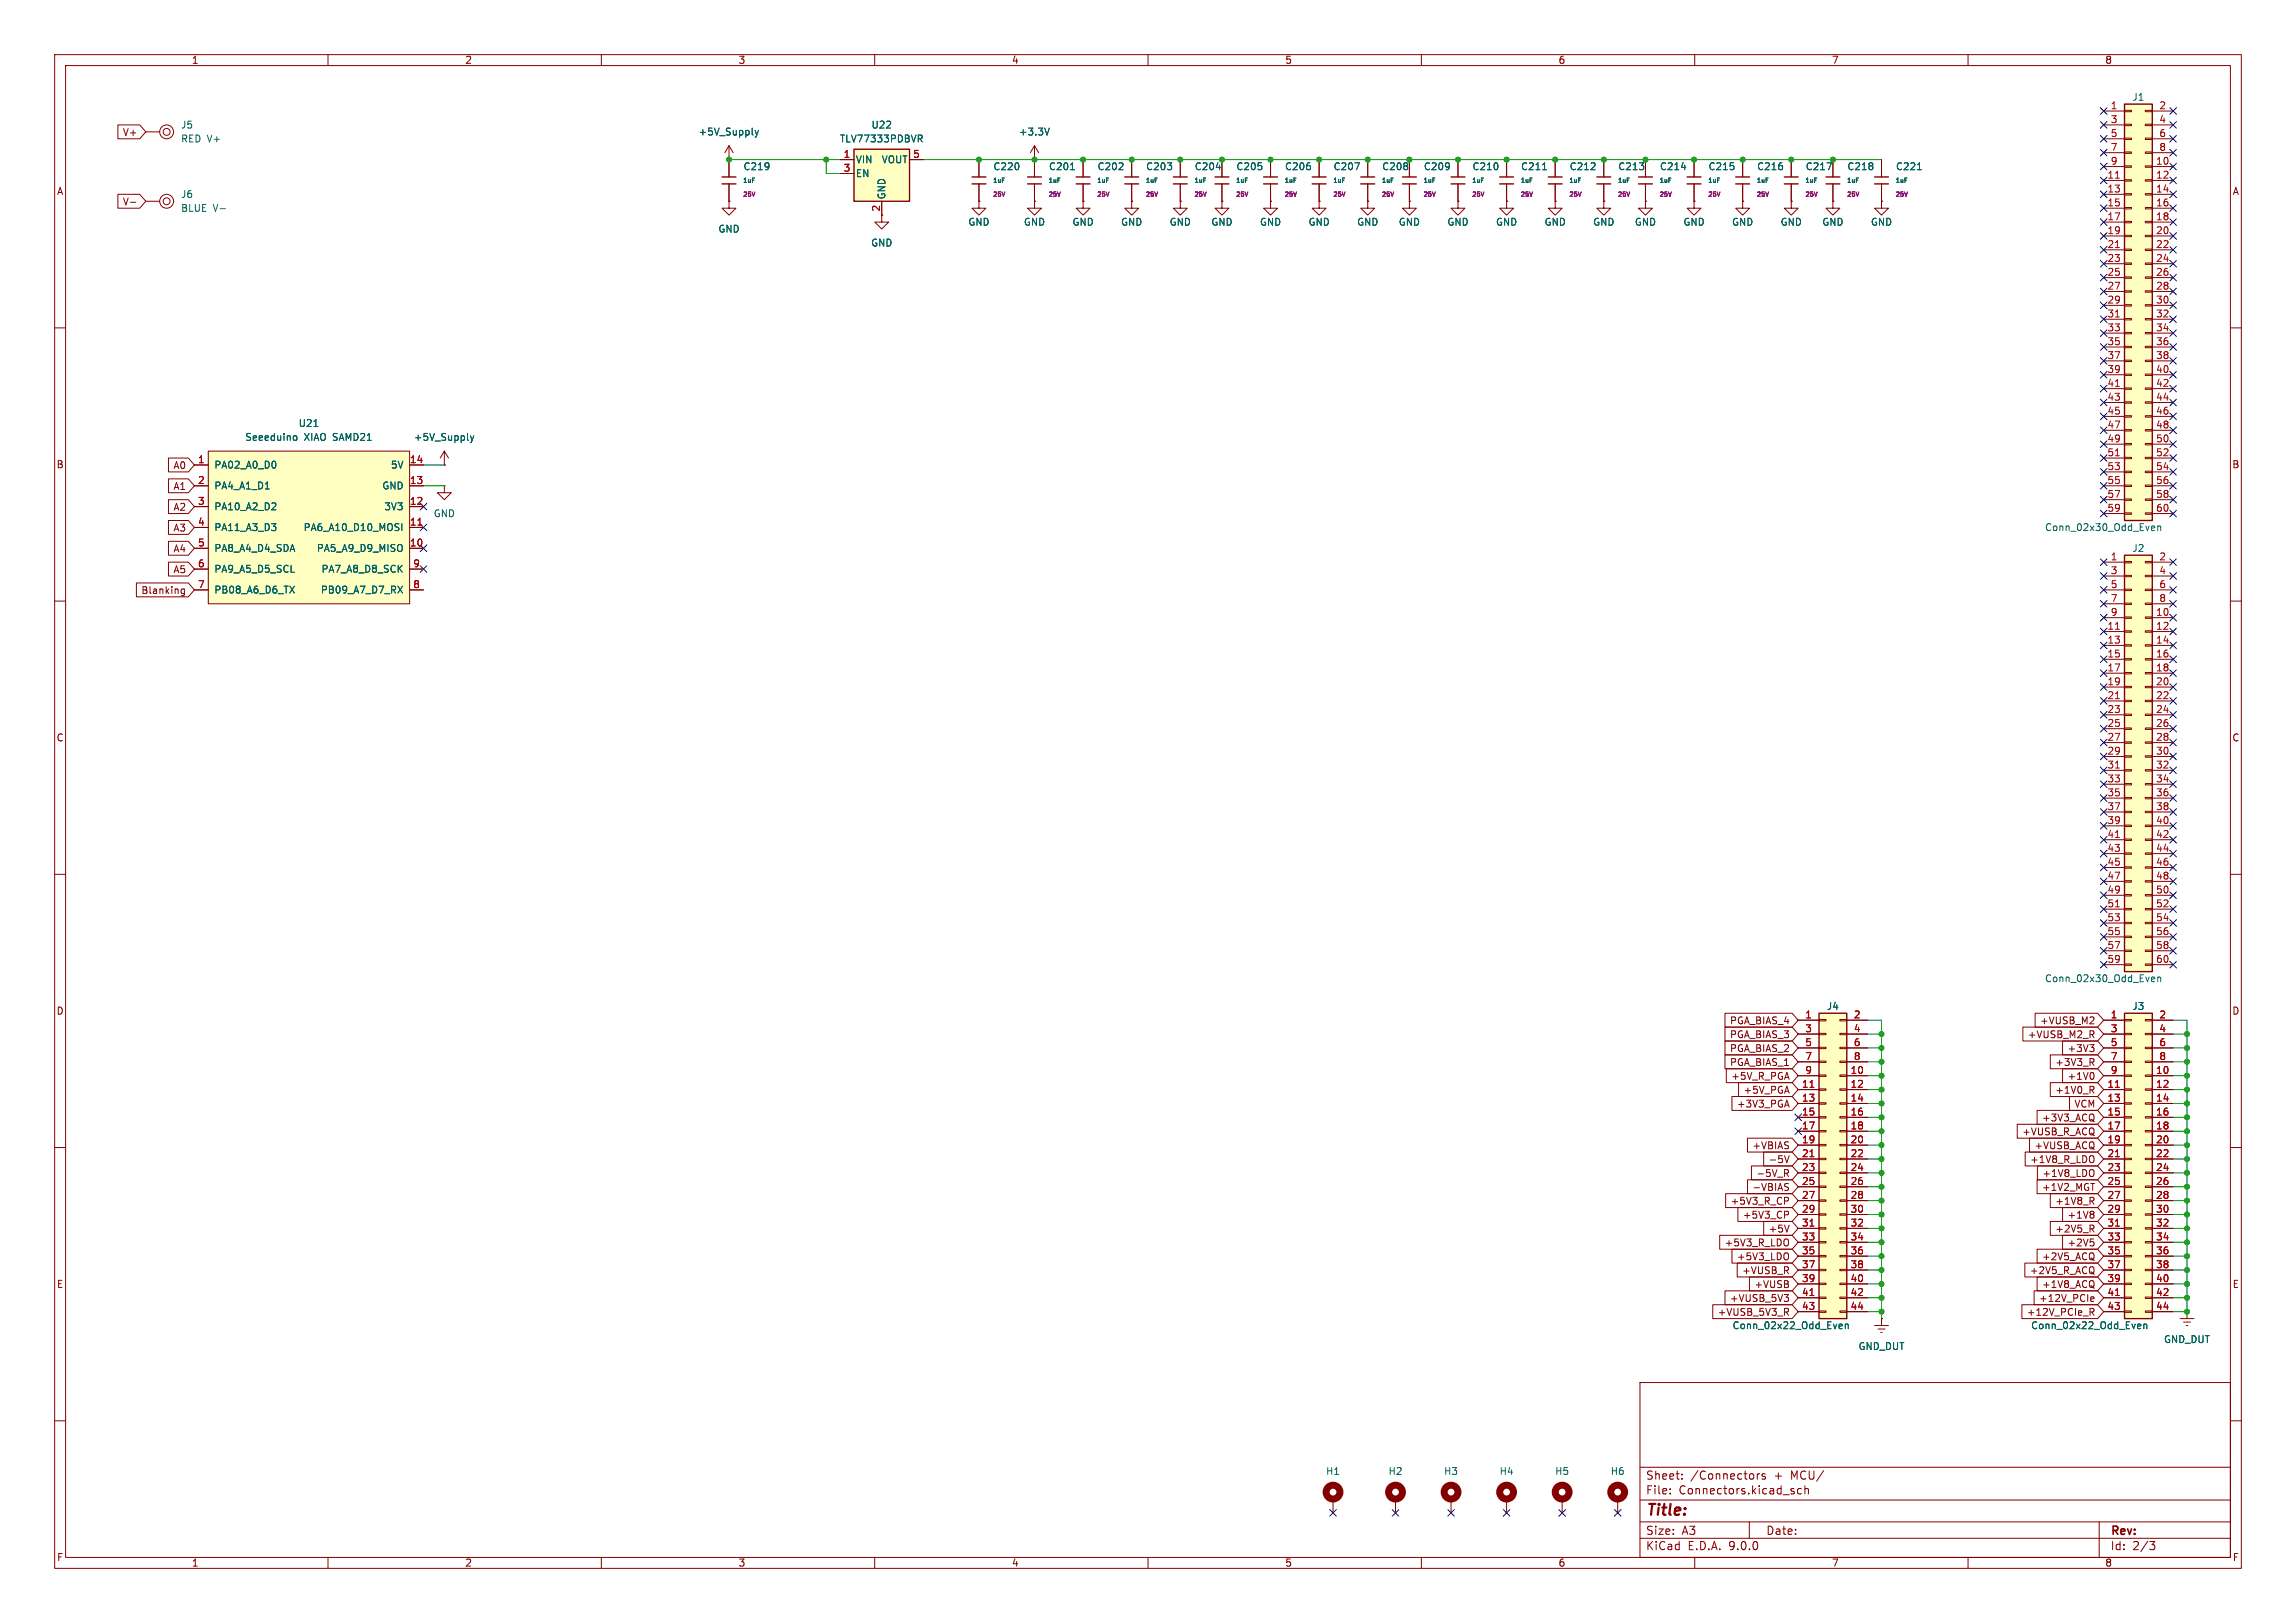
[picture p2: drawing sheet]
<svg xmlns="http://www.w3.org/2000/svg" width="420mm" height="297mm" viewBox="0 0 420 297" stroke-linecap="round" stroke-linejoin="round" font-family="sans-serif">
<defs><g id="words">
<text font-size="2.8" fill="#840000" x="301" y="277.9">Title:</text>
<g font-size="2.1" fill="#840000">
<text x="301" y="273.7">File:</text>
<text x="301" y="271">Sheet:</text>
<text x="307.1" y="273.7">Connectors.kicad_sch</text>
<text x="309.2" y="271">/Connectors</text>
<text x="324.6" y="271">+</text>
<text x="327.7" y="271">MCU/</text>
<text x="301" y="281.1">Size:</text>
<text x="307.6" y="281.1">A3</text>
<text x="323" y="281.1">Date:</text>
<text x="386" y="281.3">Rev:</text>
<text x="301" y="283.9">KiCad</text>
<text x="308.7" y="283.9">E.D.A.</text>
<text x="316.3" y="283.9">9.0.0</text>
<text x="386" y="283.9">Id:</text>
<text x="390.1" y="283.9">2/3</text>
</g>
<g font-size="1.8" fill="#840000">
<text x="35" y="11.9">1</text>
<text x="85" y="11.9">2</text>
<text x="135" y="11.9">3</text>
<text x="185" y="11.9">4</text>
<text x="235" y="11.9">5</text>
<text x="285" y="11.9">6</text>
<text x="335" y="11.9">7</text>
<text x="385" y="11.9">8</text>
<text x="22.4" y="25.1">V+</text>
<text x="10.3" y="35.9">A</text>
<text x="408.3" y="35.9">A</text>
<text x="22.4" y="37.8">V-</text>
<text x="10.3" y="85.9">B</text>
<text x="31.6" y="86">A0</text>
<text x="31.6" y="89.9">A1</text>
<text x="408.2" y="85.9">B</text>
<text x="31.6" y="93.7">A2</text>
<text x="31.6" y="101.3">A4</text>
<text x="31.6" y="97.5">A3</text>
<text x="31.6" y="105.1">A5</text>
<text x="25.8" y="108.9">Blanking</text>
<text x="10.3" y="135.9">C</text>
<text x="408.2" y="135.9">C</text>
<text x="10.3" y="185.9">D</text>
<text x="408.2" y="185.9">D</text>
<text x="316.4" y="190.2">PGA_BIAS_3</text>
<text x="316.4" y="187.6">PGA_BIAS_4</text>
<text x="370.8" y="190.2">+VUSB_M2_R</text>
<text x="373.1" y="187.6">+VUSB_M2</text>
<text x="316.4" y="195.3">PGA_BIAS_1</text>
<text x="316.4" y="192.7">PGA_BIAS_2</text>
<text x="316.6" y="197.8">+5V_R_PGA</text>
<text x="375.9" y="195.3">+3V3_R</text>
<text x="378.1" y="192.7">+3V3</text>
<text x="378.1" y="197.8">+1V0</text>
<text x="317.6" y="202.9">+3V3_PGA</text>
<text x="318.8" y="200.3">+5V_PGA</text>
<text x="375.9" y="200.3">+1V0_R</text>
<text x="379.4" y="202.9">VCM</text>
<text x="369.8" y="208">+VUSB_R_ACQ</text>
<text x="373.4" y="205.4">+3V3_ACQ</text>
<text x="320.5" y="210.5">+VBIAS</text>
<text x="321.2" y="215.6">-5V_R</text>
<text x="323.4" y="213">-5V</text>
<text x="371.3" y="213">+1V8_R_LDO</text>
<text x="372.1" y="210.5">+VUSB_ACQ</text>
<text x="373.5" y="215.6">+1V8_LDO</text>
<text x="316.5" y="220.7">+5V3_R_CP</text>
<text x="320.5" y="218.1">-VBIAS</text>
<text x="373.4" y="218.1">+1V2_MGT</text>
<text x="375.9" y="220.7">+1V8_R</text>
<text x="318.7" y="223.2">+5V3_CP</text>
<text x="323.4" y="225.7">+5V</text>
<text x="375.9" y="225.7">+2V5_R</text>
<text x="378.1" y="223.2">+1V8</text>
<text x="315.4" y="228.3">+5V3_R_LDO</text>
<text x="317.6" y="230.8">+5V3_LDO</text>
<text x="318.6" y="233.4">+VUSB_R</text>
<text x="371.2" y="233.4">+2V5_R_ACQ</text>
<text x="373.4" y="230.8">+2V5_ACQ</text>
<text x="378.1" y="228.3">+2V5</text>
<text x="10.3" y="235.9">E</text>
<text x="316.4" y="238.4">+VUSB_5V3</text>
<text x="320.8" y="235.9">+VUSB</text>
<text x="372.9" y="238.4">+12V_PCIe</text>
<text x="373.4" y="235.9">+1V8_ACQ</text>
<text x="408.3" y="235.9">E</text>
<text x="314.1" y="241">+VUSB_5V3_R</text>
<text x="370.7" y="241">+12V_PCIe_R</text>
<text x="10.3" y="285.9">F</text>
<text x="35" y="286.9">1</text>
<text x="85" y="286.9">2</text>
<text x="135" y="286.9">3</text>
<text x="185" y="286.9">4</text>
<text x="235" y="286.9">5</text>
<text x="285" y="286.9">6</text>
<text x="335" y="286.9">7</text>
<text x="385" y="286.9">8</text>
<text x="408.3" y="285.9">F</text>
</g>
<g font-size="1.8" fill="#006464">
<text x="33" y="23.7">J5</text>
<text x="159.3" y="23.7">U22</text>
<text x="390" y="18.6">J1</text>
<text x="33" y="26.3">RED V+</text>
<text x="127.7" y="25">+5V_Supply</text>
<text x="153.5" y="26.3">TLV77333PDBVR</text>
<text x="186.3" y="25">+3.3V</text>
<text x="135.9" y="31.3">C219</text>
<text x="156.5" y="30.1">VIN</text>
<text x="156.5" y="32.6">EN</text>
<text x="161.2" y="30.1">VOUT</text>
<text x="181.6" y="31.3">C220</text>
<text x="191.8" y="31.3">C201</text>
<text x="200.7" y="31.3">C202</text>
<text x="209.6" y="31.3">C203</text>
<text x="218.4" y="31.3">C204</text>
<text x="226.1" y="31.3">C205</text>
<text x="235" y="31.3">C206</text>
<text x="243.8" y="31.3">C207</text>
<text x="252.7" y="31.3">C208</text>
<text x="260.4" y="31.3">C209</text>
<text x="269.2" y="31.3">C210</text>
<text x="278.1" y="31.3">C211</text>
<text x="287" y="31.3">C212</text>
<text x="295.9" y="31.3">C213</text>
<text x="303.5" y="31.3">C214</text>
<text x="312.4" y="31.3">C215</text>
<text x="321.3" y="31.3">C216</text>
<text x="330.2" y="31.3">C217</text>
<text x="337.8" y="31.3">C218</text>
<text x="346.7" y="31.3">C221</text>
<text x="33" y="36.4">J6</text>
<text x="33" y="39">BLUE</text>
<text x="39" y="39">V-</text>
<text x="162.2" y="36.6" transform="rotate(-90 162.2 36.6)">GND</text>
<text x="177" y="41.5">GND</text>
<text x="187.2" y="41.5">GND</text>
<text x="196.1" y="41.5">GND</text>
<text x="205" y="41.5">GND</text>
<text x="213.9" y="41.5">GND</text>
<text x="221.5" y="41.5">GND</text>
<text x="230.4" y="41.5">GND</text>
<text x="239.3" y="41.5">GND</text>
<text x="248.2" y="41.5">GND</text>
<text x="255.8" y="41.5">GND</text>
<text x="264.7" y="41.5">GND</text>
<text x="273.6" y="41.5">GND</text>
<text x="282.4" y="41.5">GND</text>
<text x="291.3" y="41.5">GND</text>
<text x="299" y="41.5">GND</text>
<text x="307.8" y="41.5">GND</text>
<text x="316.7" y="41.5">GND</text>
<text x="325.6" y="41.5">GND</text>
<text x="333.2" y="41.5">GND</text>
<text x="342.1" y="41.5">GND</text>
<text x="131.3" y="42.8">GND</text>
<text x="159.3" y="45.3">GND</text>
<text x="44.8" y="80.9">Seeeduino</text>
<text x="54.5" y="78.3">U21</text>
<text x="55.6" y="80.9">XIAO SAMD21</text>
<text x="75.6" y="80.9">+5V_Supply</text>
<text x="39.1" y="86">PA02_A0_D0</text>
<text x="39.1" y="89.8">PA4_A1_D1</text>
<text x="69.8" y="89.8">GND</text>
<text x="71.4" y="86">5V</text>
<text x="39.1" y="93.6">PA10_A2_D2</text>
<text x="70.2" y="93.6">3V3</text>
<text x="79.2" y="94.8">GND</text>
<text x="39.1" y="97.4">PA11_A3_D3</text>
<text x="39.1" y="101.2">PA8_A4_D4_SDA</text>
<text x="55.4" y="97.4">PA6_A10_D10_MOSI</text>
<text x="57.9" y="101.2">PA5_A9_D9_MISO</text>
<text x="374" y="97.4">Conn_02x30_Odd_Even</text>
<text x="390" y="101.2">J2</text>
<text x="39.1" y="105">PA9_A5_D5_SCL</text>
<text x="58.7" y="105">PA7_A8_D8_SCK</text>
<text x="39.1" y="108.8">PB08_A6_D6_TX</text>
<text x="58.6" y="108.8">PB09_A7_D7_RX</text>
<text x="374" y="179.9">Conn_02x30_Odd_Even</text>
<text x="334.1" y="185">J4</text>
<text x="390" y="185">J3</text>
<text x="316.8" y="243.4">Conn_02x22_Odd_Even</text>
<text x="371.4" y="243.4">Conn_02x22_Odd_Even</text>
<text x="395.7" y="246">GND_DUT</text>
<text x="339.9" y="247.2">GND_DUT</text>
<text x="242.5" y="270.1">H1</text>
<text x="253.9" y="270.1">H2</text>
<text x="264.1" y="270.1">H3</text>
<text x="274.2" y="270.1">H4</text>
<text x="284.4" y="270.1">H5</text>
<text x="294.5" y="270.1">H6</text>
</g>
<g font-size="1.8" fill="#a90000">
<text x="386" y="20.1">1</text>
<text x="386" y="22.6">3</text>
<text x="394.9" y="20.1">2</text>
<text x="394.9" y="22.6">4</text>
<text x="154.2" y="29">1</text>
<text x="166.9" y="29">5</text>
<text x="386" y="25.1">5</text>
<text x="386" y="27.7">7</text>
<text x="394.9" y="25.1">6</text>
<text x="394.9" y="27.7">8</text>
<text x="154.2" y="31.5">3</text>
<text x="385.4" y="32.8">11</text>
<text x="385.4" y="35.3">13</text>
<text x="386" y="30.2">9</text>
<text x="394.3" y="30.2">10</text>
<text x="394.3" y="32.8">12</text>
<text x="394.3" y="35.3">14</text>
<text x="161" y="38.8" transform="rotate(-90 161 38.8)">2</text>
<text x="385.4" y="37.8">15</text>
<text x="385.4" y="40.4">17</text>
<text x="394.3" y="37.8">16</text>
<text x="394.3" y="40.4">18</text>
<text x="385.4" y="42.9">19</text>
<text x="385.4" y="45.5">21</text>
<text x="394.3" y="42.9">20</text>
<text x="394.3" y="45.5">22</text>
<text x="385.4" y="48">23</text>
<text x="385.4" y="50.5">25</text>
<text x="385.4" y="53.1">27</text>
<text x="394.3" y="48">24</text>
<text x="394.3" y="50.5">26</text>
<text x="394.3" y="53.1">28</text>
<text x="385.4" y="55.6">29</text>
<text x="385.4" y="58.2">31</text>
<text x="394.3" y="55.6">30</text>
<text x="394.3" y="58.2">32</text>
<text x="385.4" y="60.7">33</text>
<text x="385.4" y="63.2">35</text>
<text x="385.4" y="65.8">37</text>
<text x="394.3" y="60.7">34</text>
<text x="394.3" y="63.2">36</text>
<text x="394.3" y="65.8">38</text>
<text x="385.4" y="68.3">39</text>
<text x="385.4" y="70.9">41</text>
<text x="394.3" y="68.3">40</text>
<text x="394.3" y="70.9">42</text>
<text x="385.4" y="73.4">43</text>
<text x="385.4" y="75.9">45</text>
<text x="394.3" y="73.4">44</text>
<text x="394.3" y="75.9">46</text>
<text x="385.4" y="78.5">47</text>
<text x="385.4" y="81">49</text>
<text x="385.4" y="83.6">51</text>
<text x="394.3" y="78.5">48</text>
<text x="394.3" y="81">50</text>
<text x="394.3" y="83.6">52</text>
<text x="36.1" y="84.8">1</text>
<text x="36.1" y="88.6">2</text>
<text x="74.9" y="84.8">14</text>
<text x="74.9" y="88.6">13</text>
<text x="385.4" y="86.1">53</text>
<text x="385.4" y="88.6">55</text>
<text x="394.3" y="86.1">54</text>
<text x="394.3" y="88.6">56</text>
<text x="36.1" y="92.5">3</text>
<text x="74.9" y="92.5">12</text>
<text x="385.4" y="91.2">57</text>
<text x="385.4" y="93.7">59</text>
<text x="394.3" y="91.2">58</text>
<text x="394.3" y="93.7">60</text>
<text x="36.1" y="96.3">4</text>
<text x="36.1" y="100.1">5</text>
<text x="74.9" y="96.3">11</text>
<text x="74.9" y="100.1">10</text>
<text x="36.1" y="103.9">6</text>
<text x="36.1" y="107.7">7</text>
<text x="75.5" y="103.9">9</text>
<text x="75.5" y="107.7">8</text>
<text x="386" y="102.6">1</text>
<text x="386" y="105.2">3</text>
<text x="386" y="107.7">5</text>
<text x="394.9" y="102.6">2</text>
<text x="394.9" y="105.2">4</text>
<text x="394.9" y="107.7">6</text>
<text x="386" y="110.2">7</text>
<text x="386" y="112.8">9</text>
<text x="394.3" y="112.8">10</text>
<text x="394.9" y="110.2">8</text>
<text x="385.4" y="115.3">11</text>
<text x="385.4" y="117.9">13</text>
<text x="394.3" y="115.3">12</text>
<text x="394.3" y="117.9">14</text>
<text x="385.4" y="120.4">15</text>
<text x="385.4" y="122.9">17</text>
<text x="385.4" y="125.5">19</text>
<text x="394.3" y="120.4">16</text>
<text x="394.3" y="122.9">18</text>
<text x="394.3" y="125.5">20</text>
<text x="385.4" y="128">21</text>
<text x="385.4" y="130.6">23</text>
<text x="394.3" y="128">22</text>
<text x="394.3" y="130.6">24</text>
<text x="385.4" y="133.1">25</text>
<text x="385.4" y="135.6">27</text>
<text x="394.3" y="133.1">26</text>
<text x="394.3" y="135.6">28</text>
<text x="385.4" y="138.2">29</text>
<text x="385.4" y="140.7">31</text>
<text x="385.4" y="143.3">33</text>
<text x="394.3" y="138.2">30</text>
<text x="394.3" y="140.7">32</text>
<text x="394.3" y="143.3">34</text>
<text x="385.4" y="145.8">35</text>
<text x="385.4" y="148.3">37</text>
<text x="394.3" y="145.8">36</text>
<text x="394.3" y="148.3">38</text>
<text x="385.4" y="150.9">39</text>
<text x="385.4" y="153.4">41</text>
<text x="385.4" y="156">43</text>
<text x="394.3" y="150.9">40</text>
<text x="394.3" y="153.4">42</text>
<text x="394.3" y="156">44</text>
<text x="385.4" y="158.5">45</text>
<text x="385.4" y="161">47</text>
<text x="394.3" y="158.5">46</text>
<text x="394.3" y="161">48</text>
<text x="385.4" y="163.6">49</text>
<text x="385.4" y="166.1">51</text>
<text x="394.3" y="163.6">50</text>
<text x="394.3" y="166.1">52</text>
<text x="385.4" y="168.7">53</text>
<text x="385.4" y="171.2">55</text>
<text x="385.4" y="173.7">57</text>
<text x="394.3" y="168.7">54</text>
<text x="394.3" y="171.2">56</text>
<text x="394.3" y="173.7">58</text>
<text x="385.4" y="176.3">59</text>
<text x="394.3" y="176.3">60</text>
<text x="330.1" y="186.4">1</text>
<text x="330.1" y="189">3</text>
<text x="330.1" y="191.5">5</text>
<text x="339" y="186.4">2</text>
<text x="339" y="189">4</text>
<text x="339" y="191.5">6</text>
<text x="386" y="186.4">1</text>
<text x="386" y="189">3</text>
<text x="386" y="191.5">5</text>
<text x="394.9" y="186.4">2</text>
<text x="394.9" y="189">4</text>
<text x="394.9" y="191.5">6</text>
<text x="330.1" y="194.1">7</text>
<text x="330.1" y="196.6">9</text>
<text x="338.4" y="196.6">10</text>
<text x="339" y="194.1">8</text>
<text x="386" y="194.1">7</text>
<text x="386" y="196.6">9</text>
<text x="394.3" y="196.6">10</text>
<text x="394.9" y="194.1">8</text>
<text x="329.5" y="199.1">11</text>
<text x="329.5" y="201.7">13</text>
<text x="338.4" y="199.1">12</text>
<text x="338.4" y="201.7">14</text>
<text x="385.4" y="199.1">11</text>
<text x="385.4" y="201.7">13</text>
<text x="394.3" y="199.1">12</text>
<text x="394.3" y="201.7">14</text>
<text x="329.5" y="204.2">15</text>
<text x="329.5" y="206.8">17</text>
<text x="329.5" y="209.3">19</text>
<text x="338.4" y="204.2">16</text>
<text x="338.4" y="206.8">18</text>
<text x="338.4" y="209.3">20</text>
<text x="385.4" y="204.2">15</text>
<text x="385.4" y="206.8">17</text>
<text x="385.4" y="209.3">19</text>
<text x="394.3" y="204.2">16</text>
<text x="394.3" y="206.8">18</text>
<text x="394.3" y="209.3">20</text>
<text x="329.5" y="211.8">21</text>
<text x="329.5" y="214.4">23</text>
<text x="338.4" y="211.8">22</text>
<text x="338.4" y="214.4">24</text>
<text x="385.4" y="211.8">21</text>
<text x="385.4" y="214.4">23</text>
<text x="394.3" y="211.8">22</text>
<text x="394.3" y="214.4">24</text>
<text x="329.5" y="216.9">25</text>
<text x="329.5" y="219.5">27</text>
<text x="329.5" y="222">29</text>
<text x="338.4" y="216.9">26</text>
<text x="338.4" y="219.5">28</text>
<text x="338.4" y="222">30</text>
<text x="385.4" y="216.9">25</text>
<text x="385.4" y="219.5">27</text>
<text x="385.4" y="222">29</text>
<text x="394.3" y="216.9">26</text>
<text x="394.3" y="219.5">28</text>
<text x="394.3" y="222">30</text>
<text x="329.5" y="224.5">31</text>
<text x="329.5" y="227.1">33</text>
<text x="338.4" y="224.5">32</text>
<text x="338.4" y="227.1">34</text>
<text x="385.4" y="224.5">31</text>
<text x="385.4" y="227.1">33</text>
<text x="394.3" y="224.5">32</text>
<text x="394.3" y="227.1">34</text>
<text x="329.5" y="229.6">35</text>
<text x="329.5" y="232.2">37</text>
<text x="338.4" y="229.6">36</text>
<text x="338.4" y="232.2">38</text>
<text x="385.4" y="229.6">35</text>
<text x="385.4" y="232.2">37</text>
<text x="394.3" y="229.6">36</text>
<text x="394.3" y="232.2">38</text>
<text x="329.5" y="234.7">39</text>
<text x="329.5" y="237.2">41</text>
<text x="329.5" y="239.8">43</text>
<text x="338.4" y="234.7">40</text>
<text x="338.4" y="237.2">42</text>
<text x="338.4" y="239.8">44</text>
<text x="385.4" y="234.7">39</text>
<text x="385.4" y="237.2">41</text>
<text x="385.4" y="239.8">43</text>
<text x="394.3" y="234.7">40</text>
<text x="394.3" y="237.2">42</text>
<text x="394.3" y="239.8">44</text>
</g>
<g font-size="1.1" fill="#006464">
<text x="135.8" y="33.6">1uF</text>
<text x="181.5" y="33.6">1uF</text>
<text x="191.7" y="33.6">1uF</text>
<text x="200.6" y="33.6">1uF</text>
<text x="209.5" y="33.6">1uF</text>
<text x="218.4" y="33.6">1uF</text>
<text x="226" y="33.6">1uF</text>
<text x="234.9" y="33.6">1uF</text>
<text x="243.8" y="33.6">1uF</text>
<text x="252.7" y="33.6">1uF</text>
<text x="260.3" y="33.6">1uF</text>
<text x="269.2" y="33.6">1uF</text>
<text x="278.1" y="33.6">1uF</text>
<text x="286.9" y="33.6">1uF</text>
<text x="295.8" y="33.6">1uF</text>
<text x="303.5" y="33.6">1uF</text>
<text x="312.3" y="33.6">1uF</text>
<text x="321.2" y="33.6">1uF</text>
<text x="330.1" y="33.6">1uF</text>
<text x="337.7" y="33.6">1uF</text>
<text x="346.6" y="33.6">1uF</text>
</g>
<g font-size="1.1" fill="#840084">
<text x="135.8" y="36.2">25V</text>
<text x="181.5" y="36.2">25V</text>
<text x="191.7" y="36.2">25V</text>
<text x="200.6" y="36.2">25V</text>
<text x="209.5" y="36.2">25V</text>
<text x="218.4" y="36.2">25V</text>
<text x="226" y="36.2">25V</text>
<text x="234.9" y="36.2">25V</text>
<text x="243.8" y="36.2">25V</text>
<text x="252.7" y="36.2">25V</text>
<text x="260.3" y="36.2">25V</text>
<text x="269.2" y="36.2">25V</text>
<text x="278.1" y="36.2">25V</text>
<text x="286.9" y="36.2">25V</text>
<text x="295.8" y="36.2">25V</text>
<text x="303.5" y="36.2">25V</text>
<text x="312.3" y="36.2">25V</text>
<text x="321.2" y="36.2">25V</text>
<text x="330.1" y="36.2">25V</text>
<text x="337.7" y="36.2">25V</text>
<text x="346.6" y="36.2">25V</text>
</g>
</g></defs>
<g fill="none" stroke="#840000" stroke-width=".18">
<path d="M10 10h400v277h-400zM12 12h396v273h-396zM60 10v2M110 10v2M160 10v2M210 10v2M260 10v2M310 10v2M360 10v2M241.3 29.2v3.2M241.3 33.7v3.1M10 60h2"/>
<path d="M408 60h2M10 110h2M408 110h2M10 160h2M408 160h2M10 210h2M408 210h2M300 253h108v32h-108zM10 260h2M300 278.5h108M300 274.5h108M300 268.5h108"/>
<path d="M305.5 273.2v.2M305.5 272.5v.1M307.7 270.5v.2M307.7 269.8v.1M320 278.5v3M321.4 269.7v1M321.9 269.7l-.3 .1-.2 .2M322.9 269.8l-.4-.1-.2 .2 .1 .2 .5 .2v.3h-.6M328.2 273v.3M329.5 272.5l-.4-.1-.3 .3v.4l.1 .2h.6M330.2 272.5l.2-.1 .3 .1 .1 .9M330.2 271.9v1.5"/>
<path d="M384 278.5v6.5M408 260h2M60 285v2M110 285v2M160 285v2M210 285v2M260 285v2M300 281.5h108M310 285v2M360 285v2M393.2 282.1h1l-.5 .6 .4 .1 .1 .5-.3 .3h-.5"/>
</g>
<path d="M240 32.4h2.6M240 33.7h2.6" fill="none" stroke="#840000" stroke-width=".25"/>
<path d="M247.8 29.8h.9l-.6 1.3" fill="none" stroke="#006464" stroke-width=".18"/>
<path d="M332.7 185.4h5.1v55.9h-5.1z" fill="#ffffc2"/>
<path d="M283.2 32.4h2.5M283.2 33.7h2.5M299.7 32.4h2.6M299.7 33.7h2.6M326.4 32.4h2.5M326.4 33.7h2.5M334 32.4h2.5M334 33.7h2.5M332.7 185.4h5.1v55.9h-5.1z" fill="none" stroke="#840000" stroke-width=".25"/>
<g fill="none" stroke="#840000" stroke-width=".18">
<path d="M284.5 29.2v3.2M284.5 33.7v3.1M293.4 36.8v1.3h1.2l-1.2 1.3-1.3-1.3h1.3M293.4 36.8h.1M301 36.8v1.3h1.3l-1.3 1.3-1.3-1.3h1.3M301 36.8h.1M301 29.2v3.2M301 33.7v3.1M327.7 36.8v1.3h1.2l-1.2 1.3-1.3-1.3h1.3M327.7 36.8h.1M327.7 29.2v3.2M327.7 33.7v3.1"/>
<path d="M335.3 36.8v1.3h1.2l-1.2 1.3-1.3-1.3h1.3M335.3 36.8h.1M335.3 29.2v3.2M335.3 33.7v3.1M328.9 186.7h3.8M328.9 189.2h3.8M328.9 191.8h3.8M328.9 194.3h3.8M328.9 196.9h3.8M328.9 199.4h3.8M332.7 186.6h1.3v.2h-1.3zM332.7 189.1h1.3v.3h-1.3z"/>
<path d="M332.7 191.6h1.3v.3h-1.3zM332.7 194.2h1.3v.2h-1.3zM332.7 196.7h1.3v.3h-1.3zM332.7 199.3h1.3v.2h-1.3zM336.5 186.6h1.3v.2h-1.3zM336.5 189.1h1.3v.3h-1.3zM336.5 191.6h1.3v.3h-1.3zM336.5 194.2h1.3v.2h-1.3zM336.5 196.7h1.3v.3h-1.3zM336.5 199.3h1.3v.2h-1.3zM337.8 186.7h3.8M337.8 189.2h3.8"/>
<path d="M337.8 191.8h3.8M337.8 194.3h3.8M337.8 196.9h3.8M337.8 199.4h3.8M328.9 201.9h3.8M328.9 204.5h3.8M328.9 207h3.8M328.9 209.6h3.8M328.9 212.1h3.8M328.9 214.6h3.8M328.9 217.2h3.8M328.9 219.7h3.8"/>
<path d="M332.7 201.8h1.3v.3h-1.3zM332.7 204.3h1.3v.3h-1.3zM332.7 206.9h1.3v.2h-1.3zM332.7 209.4h1.3v.3h-1.3zM332.7 212h1.3v.2h-1.3zM332.7 214.5h1.3v.3h-1.3zM332.7 217h1.3v.3h-1.3zM332.7 219.6h1.3v.2h-1.3zM336.5 201.8h1.3v.3h-1.3zM336.5 204.3h1.3v.3h-1.3zM336.5 206.9h1.3v.2h-1.3zM336.5 209.4h1.3v.3h-1.3z"/>
<path d="M336.5 212h1.3v.2h-1.3zM336.5 214.5h1.3v.3h-1.3zM336.5 217h1.3v.3h-1.3zM336.5 219.6h1.3v.2h-1.3zM337.8 201.9h3.8M337.8 204.5h3.8M337.8 207h3.8M337.8 209.6h3.8M337.8 212.1h3.8M337.8 214.6h3.8M337.8 217.2h3.8M337.8 219.7h3.8"/>
<path d="M328.9 222.2h3.8M328.9 224.8h3.8M328.9 227.3h3.8M328.9 229.9h3.8M328.9 232.4h3.8M328.9 234.9h3.8M328.9 237.5h3.8M332.7 222.1h1.3v.3h-1.3zM332.7 224.7h1.3v.2h-1.3zM332.7 227.2h1.3v.3h-1.3zM332.7 229.7h1.3v.3h-1.3zM332.7 232.3h1.3v.2h-1.3z"/>
<path d="M332.7 234.8h1.3v.3h-1.3zM332.7 237.4h1.3v.2h-1.3zM332.7 239.9h1.3v.3h-1.3zM336.5 222.1h1.3v.3h-1.3zM336.5 224.7h1.3v.2h-1.3zM336.5 227.2h1.3v.3h-1.3zM336.5 229.7h1.3v.3h-1.3zM336.5 232.3h1.3v.2h-1.3zM336.5 234.8h1.3v.3h-1.3zM336.5 237.4h1.3v.2h-1.3zM336.5 239.9h1.3v.3h-1.3zM337.8 222.2h3.8"/>
<path d="M337.8 224.8h3.8M337.8 227.3h3.8M337.8 229.9h3.8M337.8 232.4h3.8M337.8 234.9h3.8M337.8 237.5h3.8M328.9 240h3.8M337.8 240h3.8M342.9 242.6h2.5M343.5 243.2h1.3M344 243.8h.3M344.2 241.3h.1"/>
<path d="M344.2 241.3v1.3M398.8 241.3h2.5M399.4 241.9h1.3M399.9 242.6h.3M400 240h.1M400 240v1.3"/>
</g>
<path d="M331.1 199h.7M331.1 211.7h.7M331.1 224.4h.7M331.1 237.1h.7" fill="none" stroke="#a90000" stroke-width=".18"/>
<path d="M307.6 30.6h.8M334.2 29.8h.8l-.5 1.3M336.6 242.3l.3 .1 .1 .2-.6 .1M336.9 243.1h-.3M337.5 242.4l.2-.1 .3 .1 .1 .7M337.5 242.3v.8" fill="none" stroke="#006464" stroke-width=".18"/>
<path d="M388.6 101.6h5.1v76.2h-5.1z" fill="#ffffc2"/>
<path d="M388.6 101.6h5.1v76.2h-5.1z" fill="none" stroke="#840000" stroke-width=".25"/>
<g fill="none" stroke="#840000" stroke-width=".18">
<path d="M26.7 36.8h2.5M26.7 24.1h2.5M384.8 102.9h3.8M384.8 105.4h3.8M384.8 108h3.8M384.8 110.5h3.8M384.8 113h3.8M384.8 115.6h3.8M384.8 118.1h3.8M388.6 102.7h1.3v.3h-1.3zM388.6 105.3h1.3v.2h-1.3zM388.6 107.8h1.3v.3h-1.3z"/>
<path d="M388.6 110.4h1.3v.2h-1.3zM388.6 112.9h1.3v.3h-1.3zM388.6 115.4h1.3v.3h-1.3zM388.6 118h1.3v.2h-1.3zM392.4 102.7h1.3v.3h-1.3zM392.4 105.3h1.3v.2h-1.3zM392.4 107.8h1.3v.3h-1.3zM392.4 110.4h1.3v.2h-1.3zM392.4 112.9h1.3v.3h-1.3zM392.4 115.4h1.3v.3h-1.3zM392.4 118h1.3v.2h-1.3zM393.7 102.9h3.8"/>
<path d="M393.7 105.4h3.8M393.7 108h3.8M393.7 110.5h3.8M393.7 113h3.8M393.7 115.6h3.8M393.7 118.1h3.8M384.8 120.7h3.8M384.8 123.2h3.8M384.8 125.7h3.8M384.8 128.3h3.8M384.8 130.8h3.8M384.8 133.4h3.8"/>
<path d="M384.8 135.9h3.8M384.8 138.4h3.8M388.6 120.5h1.3v.3h-1.3zM388.6 123.1h1.3v.2h-1.3zM388.6 125.6h1.3v.3h-1.3zM388.6 128.1h1.3v.3h-1.3zM388.6 130.7h1.3v.2h-1.3zM388.6 133.2h1.3v.3h-1.3zM388.6 135.8h1.3v.2h-1.3zM388.6 138.3h1.3v.3h-1.3zM392.4 120.5h1.3v.3h-1.3zM392.4 123.1h1.3v.2h-1.3z"/>
<path d="M392.4 125.6h1.3v.3h-1.3zM392.4 128.1h1.3v.3h-1.3zM392.4 130.7h1.3v.2h-1.3zM392.4 133.2h1.3v.3h-1.3zM392.4 135.8h1.3v.2h-1.3zM392.4 138.3h1.3v.3h-1.3zM393.7 120.7h3.8M393.7 123.2h3.8M393.7 125.7h3.8M393.7 128.3h3.8M393.7 130.8h3.8M393.7 133.4h3.8"/>
<path d="M393.7 135.9h3.8M393.7 138.4h3.8M384.8 141h3.8M384.8 143.5h3.8M384.8 146.1h3.8M384.8 148.6h3.8M384.8 151.1h3.8M384.8 153.7h3.8M384.8 156.2h3.8M384.8 158.8h3.8M388.6 140.8h1.3v.3h-1.3zM388.6 143.4h1.3v.2h-1.3z"/>
<path d="M388.6 145.9h1.3v.3h-1.3zM388.6 148.5h1.3v.2h-1.3zM388.6 151h1.3v.3h-1.3zM388.6 153.5h1.3v.3h-1.3zM388.6 156.1h1.3v.2h-1.3zM388.6 158.6h1.3v.3h-1.3zM392.4 140.8h1.3v.3h-1.3zM392.4 143.4h1.3v.2h-1.3zM392.4 145.9h1.3v.3h-1.3zM392.4 148.5h1.3v.2h-1.3zM392.4 151h1.3v.3h-1.3zM392.4 153.5h1.3v.3h-1.3z"/>
<path d="M392.4 156.1h1.3v.2h-1.3zM392.4 158.6h1.3v.3h-1.3zM393.7 141h3.8M393.7 143.5h3.8M393.7 146.1h3.8M393.7 148.6h3.8M393.7 151.1h3.8M393.7 153.7h3.8M393.7 156.2h3.8M393.7 158.8h3.8M384.8 161.3h3.8M384.8 163.8h3.8"/>
<path d="M384.8 166.4h3.8M384.8 168.9h3.8M384.8 171.5h3.8M384.8 174h3.8M384.8 176.5h3.8M388.6 161.2h1.3v.2h-1.3zM388.6 163.7h1.3v.3h-1.3zM388.6 166.2h1.3v.3h-1.3zM388.6 168.8h1.3v.2h-1.3zM388.6 171.3h1.3v.3h-1.3zM388.6 173.9h1.3v.2h-1.3zM388.6 176.4h1.3v.3h-1.3z"/>
<path d="M392.4 161.2h1.3v.2h-1.3zM392.4 163.7h1.3v.3h-1.3zM392.4 166.2h1.3v.3h-1.3zM392.4 168.8h1.3v.2h-1.3zM392.4 171.3h1.3v.3h-1.3zM392.4 173.9h1.3v.2h-1.3zM392.4 176.4h1.3v.3h-1.3zM393.7 161.3h3.8M393.7 163.8h3.8M393.7 166.4h3.8M393.7 168.9h3.8M393.7 171.5h3.8"/>
<path d="M393.7 174h3.8M393.7 176.5h3.8M265.4 274.3v2.6M285.7 274.3v2.6M295.9 274.3v2.6"/>
<circle cx="30.5" cy="36.8" r=".63"/>
<circle cx="30.5" cy="24.1" r=".63"/>
<circle cx="30.5" cy="24.1" r="1.27"/>
<circle cx="30.5" cy="36.8" r="1.27"/>
</g>
<path d="M387 115.2h.7M387 127.9h.7M387 140.6h.7M387 153.3h.7M387 166h.7" fill="none" stroke="#a90000" stroke-width=".18"/>
<path d="M393.7 178.8l.4 .1 .1 .2-.7 .1M394.1 179.6h-.4M394.7 178.9l.2-.1 .3 .1v.7M394.7 178.8v.8" fill="none" stroke="#006464" stroke-width=".18"/>
<g fill="none" stroke="#840000" stroke-width="1.3">
<circle cx="265.4" cy="273" r="1.27"/>
<circle cx="285.8" cy="273" r="1.27"/>
<circle cx="295.9" cy="273" r="1.27"/>
</g>
<path d="M38.1 82.6h36.8v27.9h-36.8z" fill="#ffffc2"/>
<g fill="none" stroke="#840000" stroke-width=".18">
<path d="M133.3 36.8v1.3h1.3l-1.3 1.3-1.2-1.3h1.2M133.3 36.8h.1M133.3 29.2h.1M133.3 26.7v5.7M133.3 33.7v3.1M133.3 26.7l-.7 1.2M133.3 26.7l.8 1.2M344.2 36.8v1.3h1.2l-1.2 1.3-1.3-1.3h1.3M344.2 36.8h.1M344.2 29.2v3.2M344.2 33.7v3.1M35.6 85.1h2.5"/>
<path d="M35.6 88.9h2.5M35.6 92.7h2.5M35.6 96.5h2.5M38.1 82.6h36.8v27.9h-36.8zM74.9 85.1h2.6M74.9 88.9h2.6M74.9 92.7h2.6M74.9 96.5h2.6M81.3 85.1h.1M81.3 82.6l-.8 1.2M81.3 82.6l.7 1.2M81.3 82.6v2.5"/>
<path d="M35.6 100.3h2.5M35.6 104.1h2.5M35.6 108h2.5M74.9 100.3h2.6M74.9 104.1h2.6M74.9 108h2.6M275.6 274.3v2.6"/>
</g>
<g fill="none" stroke="#006464" stroke-width=".18">
<path d="M138.1 23.9l.3 .8M138.4 24.7l-.3 .4M138.7 23.9l-.3 .8M350.8 31.1h.7M53.8 79.8l.3-.1 .2 .3-.1 .5-.1 .1-.3-.1M57.4 78h.7M86.1 79.7l.3 .9M86.7 79.7l-.3 .9M48.5 89.5h.8M49.7 95.8h.8l-.5 .5M50.3 84.5l.2 .4-.2 .6M50.3 92.1l.2 .2-.1 .3-.7 .7h.8"/>
<path d="M50.3 96.4l.2 .2-.2 .4M73.5 95.8v1.3M86.4 80.6l-.3 .4M53 107.3l.9 1.2M53.9 107.3l-.9 1.2M72.8 107.3l.8 1.2M73.6 107.3l-.8 1.2"/>
</g>
<path d="M76.4 96.1h.8" fill="none" stroke="#a90000" stroke-width=".18"/>
<circle cx="275.6" cy="273" r="1.27" fill="none" stroke="#840000" stroke-width="1.3"/>
<path d="M132.1 32.4h2.5M132.1 33.7h2.5M342.9 32.4h2.5M342.9 33.7h2.5" fill="none" stroke="#840000" stroke-width=".25"/>
<path d="M388.6 19.1h5.1v76.2h-5.1z" fill="#ffffc2"/>
<path d="M388.6 19.1h5.1v76.2h-5.1z" fill="none" stroke="#840000" stroke-width=".25"/>
<g fill="none" stroke="#840000" stroke-width=".18">
<path d="M384.8 20.3h3.8M384.8 22.9h3.8M384.8 25.4h3.8M384.8 27.9h3.8M384.8 30.5h3.8M384.8 33h3.8M384.8 35.6h3.8M384.8 38.1h3.8M388.6 20.2h1.3v.2h-1.3zM388.6 22.7h1.3v.3h-1.3zM388.6 25.3h1.3v.2h-1.3zM388.6 27.8h1.3v.3h-1.3z"/>
<path d="M388.6 30.4h1.3v.2h-1.3zM388.6 32.9h1.3v.2h-1.3zM388.6 35.4h1.3v.3h-1.3zM388.6 38h1.3v.2h-1.3zM392.4 20.2h1.3v.2h-1.3zM392.4 22.7h1.3v.3h-1.3zM392.4 25.3h1.3v.2h-1.3zM392.4 27.8h1.3v.3h-1.3zM392.4 30.4h1.3v.2h-1.3zM392.4 32.9h1.3v.2h-1.3zM392.4 35.4h1.3v.3h-1.3zM392.4 38h1.3v.2h-1.3z"/>
<path d="M393.7 20.3h3.8M393.7 22.9h3.8M393.7 25.4h3.8M393.7 27.9h3.8M393.7 30.5h3.8M393.7 33h3.8M393.7 35.6h3.8M393.7 38.1h3.8M384.8 40.6h3.8M384.8 43.2h3.8M384.8 45.7h3.8M384.8 48.3h3.8"/>
<path d="M384.8 50.8h3.8M384.8 53.3h3.8M384.8 55.9h3.8M384.8 58.4h3.8M388.6 40.5h1.3v.3h-1.3zM388.6 43.1h1.3v.2h-1.3zM388.6 45.6h1.3v.2h-1.3zM388.6 48.1h1.3v.3h-1.3zM388.6 50.7h1.3v.2h-1.3zM388.6 53.2h1.3v.3h-1.3zM388.6 55.8h1.3v.2h-1.3zM388.6 58.3h1.3v.2h-1.3z"/>
<path d="M392.4 40.5h1.3v.3h-1.3zM392.4 43.1h1.3v.2h-1.3zM392.4 45.6h1.3v.2h-1.3zM392.4 48.1h1.3v.3h-1.3zM392.4 50.7h1.3v.2h-1.3zM392.4 53.2h1.3v.3h-1.3zM392.4 55.8h1.3v.2h-1.3zM392.4 58.3h1.3v.2h-1.3zM393.7 40.6h3.8M393.7 43.2h3.8M393.7 45.7h3.8M393.7 48.3h3.8"/>
<path d="M393.7 50.8h3.8M393.7 53.3h3.8M393.7 55.9h3.8M393.7 58.4h3.8M384.8 61h3.8M384.8 63.5h3.8M384.8 66h3.8M384.8 68.6h3.8M384.8 71.1h3.8M384.8 73.7h3.8M384.8 76.2h3.8M384.8 78.7h3.8"/>
<path d="M388.6 60.8h1.3v.3h-1.3zM388.6 63.4h1.3v.2h-1.3zM388.6 65.9h1.3v.3h-1.3zM388.6 68.5h1.3v.2h-1.3zM388.6 71h1.3v.2h-1.3zM388.6 73.5h1.3v.3h-1.3zM388.6 76.1h1.3v.2h-1.3zM388.6 78.6h1.3v.3h-1.3zM392.4 60.8h1.3v.3h-1.3zM392.4 63.4h1.3v.2h-1.3zM392.4 65.9h1.3v.3h-1.3zM392.4 68.5h1.3v.2h-1.3z"/>
<path d="M392.4 71h1.3v.2h-1.3zM392.4 73.5h1.3v.3h-1.3zM392.4 76.1h1.3v.2h-1.3zM392.4 78.6h1.3v.3h-1.3zM393.7 61h3.8M393.7 63.5h3.8M393.7 66h3.8M393.7 68.6h3.8M393.7 71.1h3.8M393.7 73.7h3.8M393.7 76.2h3.8M393.7 78.7h3.8"/>
<path d="M384.8 81.3h3.8M384.8 83.8h3.8M384.8 86.4h3.8M384.8 88.9h3.8M384.8 91.4h3.8M384.8 94h3.8M388.6 81.2h1.3v.2h-1.3zM388.6 83.7h1.3v.2h-1.3zM388.6 86.2h1.3v.3h-1.3zM388.6 88.8h1.3v.2h-1.3zM388.6 91.3h1.3v.3h-1.3zM388.6 93.9h1.3v.2h-1.3z"/>
<path d="M392.4 81.2h1.3v.2h-1.3zM392.4 83.7h1.3v.2h-1.3zM392.4 86.2h1.3v.3h-1.3zM392.4 88.8h1.3v.2h-1.3zM392.4 91.3h1.3v.3h-1.3zM392.4 93.9h1.3v.2h-1.3zM393.7 81.3h3.8M393.7 83.8h3.8M393.7 86.4h3.8M393.7 88.9h3.8M393.7 91.4h3.8M393.7 94h3.8"/>
</g>
<path d="M387 32.6h.7M387 45.3h.7M387 58h.7M387 70.7h.7M387 83.4h.7" fill="none" stroke="#a90000" stroke-width=".18"/>
<path d="M393.7 96.3h.4l.1 .3-.7 .1M394.1 97l-.4 .1M394.7 96.4l.2-.1h.3v.8M394.7 96.3v.8" fill="none" stroke="#006464" stroke-width=".18"/>
<path d="M388.6 185.4h5.1v55.9h-5.1z" fill="#ffffc2"/>
<path d="M205.7 32.4h2.6M205.7 33.7h2.6M214.6 32.4h2.6M214.6 33.7h2.6M388.6 185.4h5.1v55.9h-5.1z" fill="none" stroke="#840000" stroke-width=".25"/>
<g fill="none" stroke="#840000" stroke-width=".18">
<path d="M207 36.8v1.3h1.3l-1.3 1.3-1.3-1.3h1.3M207 36.8h.1M207 29.2v3.2M207 33.7v3.1M215.9 36.8v1.3h1.3l-1.3 1.3-1.3-1.3h1.3M215.9 36.8h.1M215.9 29.2v3.2M215.9 33.7v3.1M223.5 36.8v1.3h1.3l-1.3 1.3-1.3-1.3h1.3M223.5 36.8h.1M81.3 88.9v1.3h1.2l-1.2 1.2-1.3-1.2h1.3M81.3 88.9h.1"/>
<path d="M384.8 186.7h3.8M384.8 189.2h3.8M384.8 191.8h3.8M384.8 194.3h3.8M384.8 196.9h3.8M384.8 199.4h3.8M388.6 186.6h1.3v.2h-1.3zM388.6 189.1h1.3v.3h-1.3zM388.6 191.6h1.3v.3h-1.3zM388.6 194.2h1.3v.2h-1.3zM388.6 196.7h1.3v.3h-1.3zM388.6 199.3h1.3v.2h-1.3z"/>
<path d="M392.4 186.6h1.3v.2h-1.3zM392.4 189.1h1.3v.3h-1.3zM392.4 191.6h1.3v.3h-1.3zM392.4 194.2h1.3v.2h-1.3zM392.4 196.7h1.3v.3h-1.3zM392.4 199.3h1.3v.2h-1.3zM393.7 186.7h3.8M393.7 189.2h3.8M393.7 191.8h3.8M393.7 194.3h3.8M393.7 196.9h3.8M393.7 199.4h3.8"/>
<path d="M384.8 201.9h3.8M384.8 204.5h3.8M384.8 207h3.8M384.8 209.6h3.8M384.8 212.1h3.8M384.8 214.6h3.8M384.8 217.2h3.8M384.8 219.7h3.8M388.6 201.8h1.3v.3h-1.3zM388.6 204.3h1.3v.3h-1.3zM388.6 206.9h1.3v.2h-1.3zM388.6 209.4h1.3v.3h-1.3z"/>
<path d="M388.6 212h1.3v.2h-1.3zM388.6 214.5h1.3v.3h-1.3zM388.6 217h1.3v.3h-1.3zM388.6 219.6h1.3v.2h-1.3zM392.4 201.8h1.3v.3h-1.3zM392.4 204.3h1.3v.3h-1.3zM392.4 206.9h1.3v.2h-1.3zM392.4 209.4h1.3v.3h-1.3zM392.4 212h1.3v.2h-1.3zM392.4 214.5h1.3v.3h-1.3zM392.4 217h1.3v.3h-1.3zM392.4 219.6h1.3v.2h-1.3z"/>
<path d="M393.7 201.9h3.8M393.7 204.5h3.8M393.7 207h3.8M393.7 209.6h3.8M393.7 212.1h3.8M393.7 214.6h3.8M393.7 217.2h3.8M393.7 219.7h3.8M384.8 222.2h3.8M384.8 224.8h3.8M384.8 227.3h3.8M384.8 229.9h3.8"/>
<path d="M384.8 232.4h3.8M384.8 234.9h3.8M384.8 237.5h3.8M388.6 222.1h1.3v.3h-1.3zM388.6 224.7h1.3v.2h-1.3zM388.6 227.2h1.3v.3h-1.3zM388.6 229.7h1.3v.3h-1.3zM388.6 232.3h1.3v.2h-1.3zM388.6 234.8h1.3v.3h-1.3zM388.6 237.4h1.3v.2h-1.3zM388.6 239.9h1.3v.3h-1.3zM392.4 222.1h1.3v.3h-1.3z"/>
<path d="M392.4 224.7h1.3v.2h-1.3zM392.4 227.2h1.3v.3h-1.3zM392.4 229.7h1.3v.3h-1.3zM392.4 232.3h1.3v.2h-1.3zM392.4 234.8h1.3v.3h-1.3zM392.4 237.4h1.3v.2h-1.3zM392.4 239.9h1.3v.3h-1.3zM393.7 222.2h3.8M393.7 224.8h3.8M393.7 227.3h3.8M393.7 229.9h3.8M393.7 232.4h3.8"/>
<path d="M393.7 234.9h3.8M393.7 237.5h3.8M384.8 240h3.8M393.7 240h3.8"/>
</g>
<path d="M387 199h.7M387 211.7h.7M387 224.4h.7M387 237.1h.7" fill="none" stroke="#a90000" stroke-width=".18"/>
<path d="M222.5 30.6h.8M391.2 242.3l.4 .1v.2l-.6 .1M391.6 243.1h-.4M392.2 242.4l.1-.1 .3 .1 .1 .7M392.2 242.3v.8" fill="none" stroke="#006464" stroke-width=".18"/>
<path d="M156.2 27.3h10.2v9.5h-10.2z" fill="#ffffc2"/>
<g fill="none" stroke="#840000" stroke-width=".25">
<path d="M156.2 27.3h10.2v9.5h-10.2zM177.8 32.4h2.5M177.8 33.7h2.5M188 32.4h2.5M188 33.7h2.5M196.8 32.4h2.6M196.8 33.7h2.6M222.2 32.4h2.6M222.2 33.7h2.6M231.1 32.4h2.6M231.1 33.7h2.6M248.9 32.4h2.6"/>
<path d="M248.9 33.7h2.6M256.5 32.4h2.6M256.5 33.7h2.6M265.4 32.4h2.6M265.4 33.7h2.6M274.3 32.4h2.6M274.3 33.7h2.6M292.1 32.4h2.5M292.1 33.7h2.5M308.6 32.4h2.5M308.6 33.7h2.5M317.5 32.4h2.5"/>
<path d="M317.5 33.7h2.5"/>
</g>
<g fill="none" stroke="#840000" stroke-width=".18">
<path d="M21.6 35.6h4l1.1 1.2-1.1 1.3h-4zM21.6 22.9h4l1.1 1.2-1.1 1.3h-4zM23.9 37h.9M133.3 29.2h.1M133.3 36.8h.1M133.3 29.2v3.2M133.3 33.7v3.1M153.7 29.2h2.5M153.7 31.8h2.5M161.3 36.8v3.8h1.3l-1.3 1.3-1.3-1.3h1.3M166.4 29.2h2.5M179.1 36.8v1.3h1.2l-1.2 1.3-1.3-1.3h1.3"/>
<path d="M179.1 36.8h.1M179.1 29.2v3.2M179.1 33.7v3.1M189.2 29.2h.1M189.2 36.8v1.3h1.3l-1.3 1.3-1.2-1.3h1.2M189.2 36.8h.1M189.2 26.7l-.7 1.2M189.2 26.7l.8 1.2M189.2 26.7v5.7M189.2 33.7v3.1M198.1 36.8v1.3h1.3l-1.3 1.3-1.3-1.3h1.3M198.1 36.8h.1"/>
<path d="M198.1 29.2v3.2M198.1 33.7v3.1M207 36.8h.1M207 29.2v3.2M207 33.7v3.1M215.9 36.8h.1M215.9 29.2v3.2M215.9 33.7v3.1M223.5 36.8h.1M223.5 29.2v3.2M223.5 33.7v3.1M232.4 36.8v1.3h1.3l-1.3 1.3-1.3-1.3h1.3"/>
<path d="M232.4 36.8h.1M232.4 29.2v3.2M232.4 33.7v3.1M241.3 36.8v1.3h1.3l-1.3 1.3-1.3-1.3h1.3M241.3 36.8h.1M241.3 29.2v3.2M241.3 33.7v3.1M250.2 36.8v1.3h1.3l-1.3 1.3-1.3-1.3h1.3M250.2 36.8h.1M250.2 29.2v3.2M250.2 33.7v3.1M257.8 36.8v1.3h1.3l-1.3 1.3-1.3-1.3h1.3"/>
<path d="M257.8 36.8h.1M257.8 29.2v3.2M257.8 33.7v3.1M266.7 36.8v1.3h1.3l-1.3 1.3-1.3-1.3h1.3M266.7 36.8h.1M266.7 29.2v3.2M266.7 33.7v3.1M275.6 36.8v1.3h1.3l-1.3 1.3-1.3-1.3h1.3M275.6 36.8h.1M275.6 29.2v3.2M275.6 33.7v3.1M284.5 36.8v1.3h1.2l-1.2 1.3-1.3-1.3h1.3"/>
<path d="M284.5 36.8h.1M284.5 29.2v3.2M284.5 33.7v3.1M293.4 36.8h.1M293.4 29.2v3.2M293.4 33.7v3.1M301 36.8h.1M301 29.2v3.2M301 33.7v3.1M309.9 36.8v1.3h1.2l-1.2 1.3-1.3-1.3h1.3M309.9 36.8h.1M309.9 29.2v3.2"/>
<path d="M309.9 33.7v3.1M318.8 36.8v1.3h1.2l-1.2 1.3-1.3-1.3h1.3M318.8 36.8h.1M318.8 29.2v3.2M318.8 33.7v3.1M327.7 36.8h.1M327.7 29.2v3.2M327.7 33.7v3.1M335.3 36.8h.1M335.3 29.2v3.2M335.3 33.7v3.1M344.2 36.8h.1"/>
<path d="M344.2 29.2v3.2M344.2 33.7v3.1M30.8 91.4h3.6l1.2 1.3-1.2 1.3h-3.6zM30.8 99.1h3.6l1.2 1.2-1.2 1.3h-3.6zM30.8 95.2h3.6l1.2 1.3-1.2 1.3h-3.6zM30.8 83.8h3.6l1.2 1.3-1.2 1.3h-3.6zM30.8 87.6h3.6l1.2 1.3-1.2 1.3h-3.6zM35.6 85.1h2.5M35.6 88.9h2.5M35.6 92.7h2.5M35.6 96.5h2.5M74.9 85.1h2.6"/>
<path d="M74.9 88.9h2.6M74.9 92.7h2.6M74.9 96.5h2.6M81.3 85.1h.1M25 106.7h9.4l1.2 1.3-1.2 1.2h-9.4zM30.8 102.9h3.6l1.2 1.2-1.2 1.3h-3.6zM33.7 107.8v1l-.2 .2h-.3M33.7 107.8h-.3l-.3 .2 .1 .6h.5M35.6 100.3h2.5M35.6 104.1h2.5M35.6 108h2.5M74.9 100.3h2.6"/>
<path d="M74.9 104.1h2.6M74.9 108h2.6M315.5 193h12.3l1.1 1.3-1.1 1.3h-12.3zM315.5 188h12.3l1.1 1.2-1.1 1.3h-12.3zM315.5 185.4h12.3l1.1 1.3-1.1 1.3h-12.3zM315.5 190.5h12.3l1.1 1.3-1.1 1.2h-12.3zM315.8 195.6h12l1.1 1.3-1.1 1.2h-12zM318 198.1h9.8l1.1 1.3-1.1 1.3h-9.8zM328.9 186.7h3.8M328.9 189.2h3.8M328.9 191.8h3.8M328.9 194.3h3.8"/>
<path d="M328.9 196.9h3.8M328.9 199.4h3.8M337.8 186.7h3.8M337.8 189.2h3.8M337.8 191.8h3.8M337.8 194.3h3.8M337.8 196.9h3.8M337.8 199.4h3.8M370 188h13.7l1.1 1.2-1.1 1.3h-13.7zM372.3 185.4h11.4l1.1 1.3-1.1 1.3h-11.4zM375 193h8.7l1.1 1.3-1.1 1.3h-8.7zM375 198.1h8.7l1.1 1.3-1.1 1.3h-8.7z"/>
<path d="M377.3 190.5h6.4l1.1 1.3-1.1 1.2h-6.4zM377.3 195.6h6.4l1.1 1.3-1.1 1.2h-6.4zM382.3 191.2h.7l-.4 .5M382.6 194.4l.4 .6M382.6 189.3l.4 .6M382.6 199.5l.4 .6M382.7 196.3a.79 .79 0 0 1 0 1.2M382.8 193.7l.2 .3v.3l-.2 .1M382.8 198.8l.2 .2v.3l-.2 .2M382.8 191.7l.2 .2v.3l-.2 .2M382.8 186.1l.2 .2v.3l-.7 .8h.7M382.9 188.7l.1 .2-.1 .3"/>
<path d="M384.8 186.7h3.8M384.8 189.2h3.8M384.8 191.8h3.8M384.8 194.3h3.8M384.8 196.9h3.8M384.8 199.4h3.8M393.7 186.7h3.8M393.7 189.2h3.8M393.7 191.8h3.8M393.7 194.3h3.8M393.7 196.9h3.8M393.7 199.4h3.8"/>
<path d="M315.7 218.4h12.1l1.1 1.3-1.1 1.3h-12.1zM316.8 200.7h11l1.1 1.2-1.1 1.3h-11zM319.7 215.9h8.1l1.1 1.3-1.1 1.2h-8.1zM319.7 208.3h8.1l1.1 1.3-1.1 1.2h-8.1zM320.4 213.4h7.4l1.1 1.2-1.1 1.3h-7.4zM322.6 210.8h5.2l1.1 1.3-1.1 1.3h-5.2zM326.4 214h.5l.3 .3-.2 .3-.6 .1M326.4 219.1h.5l.3 .3-.2 .3-.6 .1M326.4 211.5l.5 1.3 .4-1.3M326.6 202.2h.6M326.7 217.2l.3 .1 .2 .3-.3 .2h-.3M326.7 216.6h.5"/>
<path d="M326.7 214.7l.5 .6M326.9 201.3l.4 1.3M328.9 201.9h3.8M328.9 204.5h3.8M328.9 207h3.8M328.9 209.6h3.8M328.9 212.1h3.8M328.9 214.6h3.8M328.9 217.2h3.8M328.9 219.7h3.8M337.8 201.9h3.8M337.8 204.5h3.8"/>
<path d="M337.8 207h3.8M337.8 209.6h3.8M337.8 212.1h3.8M337.8 214.6h3.8M337.8 217.2h3.8M337.8 219.7h3.8M369 205.7h14.7l1.1 1.3-1.1 1.3h-14.7zM370.5 210.8h13.2l1.1 1.3-1.1 1.3h-13.2zM371.2 208.3h12.5l1.1 1.3-1.1 1.2h-12.5zM372.6 203.2h11.1l1.1 1.3-1.1 1.2h-11.1zM372.6 215.9h11.1l1.1 1.3-1.1 1.2h-11.1zM372.7 213.4h11l1.1 1.2-1.1 1.3h-11z"/>
<path d="M375 218.4h8.7l1.1 1.3-1.1 1.3h-8.7zM378.6 200.7h5.1l1.1 1.2-1.1 1.3h-5.1zM382.4 216.6h.8M382.6 219.8l.4 .6M382.7 214l.2 .1a.81 .81 0 0 1-.2 1.2M382.8 219.1l.2 .3v.3l-.2 .1M382.9 211.6a.9 .9 0 0 1 0 1.1M383 204.1v.9M383 205.2l.1 .1M384.8 201.9h3.8M384.8 204.5h3.8M384.8 207h3.8"/>
<path d="M384.8 209.6h3.8M384.8 212.1h3.8M384.8 214.6h3.8M384.8 217.2h3.8M384.8 219.7h3.8M393.7 201.9h3.8M393.7 204.5h3.8M393.7 207h3.8M393.7 209.6h3.8M393.7 212.1h3.8M393.7 214.6h3.8M393.7 217.2h3.8"/>
<path d="M393.7 219.7h3.8M313.3 238.8h14.5l1.1 1.2-1.1 1.3h-14.5zM314.6 226.1h13.2l1.1 1.2-1.1 1.3h-13.2zM315.5 236.2h12.3l1.1 1.3-1.1 1.3h-12.3zM316.8 228.6h11l1.1 1.3-1.1 1.2h-11zM317.8 231.1h10l1.1 1.3-1.1 1.3h-10zM317.9 221h9.9l1.1 1.2-1.1 1.3h-9.9zM320 233.7h7.8l1.1 1.2-1.1 1.3h-7.8zM322.6 223.5h5.2l1.1 1.3-1.1 1.3h-5.2zM326.4 236.9h.8l-.5 .5 .4 .1 .1 .4-.3 .3h-.3M326.4 221.7h.5l.3 .2-.2 .4h-.6M326.4 239.4h.5l.3 .3-.2 .3-.6 .1"/>
<path d="M326.9 229.3h.1a.81 .81 0 0 1-.1 1.2M327 226.8a.9 .9 0 0 1 0 1.1M327.3 224.2l-.4 1.3M328.9 222.2h3.8M328.9 224.8h3.8M328.9 227.3h3.8M328.9 229.9h3.8M328.9 232.4h3.8M328.9 234.9h3.8M328.9 237.5h3.8M337.8 222.2h3.8M337.8 224.8h3.8"/>
<path d="M337.8 227.3h3.8M337.8 229.9h3.8M337.8 232.4h3.8M337.8 234.9h3.8M337.8 237.5h3.8M369.8 238.8h13.9l1.1 1.2-1.1 1.3h-13.9zM370.4 231.1h13.3l1.1 1.3-1.1 1.3h-13.3zM372.1 236.2h11.6l1.1 1.3-1.1 1.3h-11.6zM372.6 233.7h11.1l1.1 1.2-1.1 1.3h-11.1zM372.6 228.6h11.1l1.1 1.3-1.1 1.2h-11.1zM375 223.5h8.7l1.1 1.3-1.1 1.3h-8.7zM377.3 221h6.4l1.1 1.2-1.1 1.3h-6.4z"/>
<path d="M377.3 226.1h6.4l1.1 1.2-1.1 1.3h-6.4zM382.3 239.4h.5l.2 .3-.1 .3-.6 .1M382.4 226.7h.6M382.5 237.4l.4-.1 .1 .3-.6 .1M382.5 238.1h.5M382.6 224.9l.4 .6M382.8 224.2l.2 .2v.3l-.2 .2M382.8 221.7l.2 .2-.2 .3 .2 .2v.3l-.2 .2M382.8 227.2l.2 .3v.3l-.2 .2M383 229.5v.9M383 232v.9M383 234.5v.9"/>
<path d="M383 235.7h.1M383 233.1l.1 .1M383 230.6l.1 .1M384.8 222.2h3.8M384.8 224.8h3.8M384.8 227.3h3.8M384.8 229.9h3.8M384.8 232.4h3.8M384.8 234.9h3.8M384.8 237.5h3.8M393.7 222.2h3.8M393.7 224.8h3.8"/>
<path d="M393.7 227.3h3.8M393.7 229.9h3.8M393.7 232.4h3.8M393.7 234.9h3.8M393.7 237.5h3.8M326.7 240.1l.5 .6M328.9 240h3.8M337.8 240h3.8M344.2 241.3h.1M382.6 240.1l.4 .6M384.8 240h3.8M393.7 240h3.8"/>
<path d="M400 240h.1M243.8 274.3v2.6M255.3 274.3v2.6"/>
</g>
<g fill="none" stroke="#006464" stroke-width=".18">
<path d="M138.1 23.9l.3 .8M138.4 24.7l-.3 .4M138.7 23.9l-.3 .8M168 24.7h.5l.2 .3-.1 .3-.6 .1M168.3 25.4l.4 .6M192 23.4l-.5 1.3M195.8 31.1h.7M222.5 30.6h.8M247.8 29.8h.9l-.6 1.3M282.2 31.1h.7M307.6 30.6h.8M334.2 29.8h.8l-.5 1.3"/>
<path d="M350.8 31.1h.7M53.8 79.8l.3-.1 .2 .3-.1 .5-.1 .1-.3-.1M57.4 78h.7M86.1 79.7l.3 .9M86.7 79.7l-.3 .9M48.5 89.5h.8M49.7 95.8h.8l-.5 .5M50.3 84.5l.2 .4-.2 .6M50.3 92.1l.2 .2-.1 .3-.7 .7h.8M50.3 96.4l.2 .2-.2 .4M73.5 95.8v1.3M86.4 80.6l-.3 .4"/>
<path d="M53 107.3l.9 1.2M53.9 107.3l-.9 1.2M72.8 107.3l.8 1.2M73.6 107.3l-.8 1.2M336.6 242.3l.3 .1 .1 .2-.6 .1M336.9 243.1h-.3M337.5 242.4l.2-.1 .3 .1 .1 .7M337.5 242.3v.8M391.2 242.3l.4 .1v.2l-.6 .1M391.6 243.1h-.4M392.2 242.4l.1-.1 .3 .1 .1 .7M392.2 242.3v.8"/>
</g>
<g fill="none" stroke="#840000" stroke-width="1.3">
<circle cx="243.8" cy="273" r="1.27"/>
<circle cx="255.3" cy="273" r="1.27"/>
</g>
<g fill="none" stroke="#009600" stroke-width=".18">
<path d="M133.3 29.2h20.4M151.1 29.2v2.6h2.6M168.9 29.2h175.3M77.5 85.1h3.8M77.5 88.9h3.8M341.6 196.9h2.6M341.6 199.4h2.6M341.6 191.8h2.6M341.6 194.3h2.6M341.6 189.2h2.6M341.6 186.7h2.6v54.6M397.5 186.7h2.5v53.3h-2.5"/>
<path d="M397.5 196.9h2.5M397.5 199.4h2.5M397.5 191.8h2.5M397.5 194.3h2.5M397.5 189.2h2.5M341.6 219.7h2.6M341.6 212.1h2.6M341.6 214.6h2.6M341.6 204.5h2.6M341.6 201.9h2.6M341.6 217.2h2.6M341.6 207h2.6"/>
<path d="M341.6 209.6h2.6M397.5 219.7h2.5M397.5 212.1h2.5M397.5 214.6h2.5M397.5 204.5h2.5M397.5 201.9h2.5M397.5 217.2h2.5M397.5 207h2.5M397.5 209.6h2.5M341.6 237.5h2.6M341.6 224.8h2.6M341.6 222.2h2.6"/>
<path d="M341.6 232.4h2.6M341.6 227.3h2.6M341.6 229.9h2.6M341.6 234.9h2.6M397.5 237.5h2.5M397.5 224.8h2.5M397.5 222.2h2.5M397.5 232.4h2.5M397.5 227.3h2.5M397.5 229.9h2.5M397.5 234.9h2.5M341.6 240h2.6"/>
</g>
<g fill="none" stroke="#000084" stroke-width=".18">
<path d="M384.2 19.7l1.2 1.2M385.4 19.7l-1.2 1.2M396.9 19.7l1.2 1.2M398.1 19.7l-1.2 1.2M384.2 24.8l1.2 1.2M384.2 37.5l1.2 1.2M384.2 27.3l1.2 1.2M384.2 29.9l1.2 1.2M384.2 32.4l1.2 1.2M384.2 22.3l1.2 1.2M384.2 35l1.2 1.2M385.4 35l-1.2 1.2"/>
<path d="M385.4 37.5l-1.2 1.2M385.4 32.4l-1.2 1.2M385.4 24.8l-1.2 1.2M385.4 27.3l-1.2 1.2M385.4 29.9l-1.2 1.2M385.4 22.3l-1.2 1.2M396.9 29.9l1.2 1.2M396.9 22.3l1.2 1.2M396.9 24.8l1.2 1.2M396.9 32.4l1.2 1.2M396.9 27.3l1.2 1.2M396.9 37.5l1.2 1.2"/>
<path d="M396.9 35l1.2 1.2M398.1 29.9l-1.2 1.2M398.1 22.3l-1.2 1.2M398.1 24.8l-1.2 1.2M398.1 32.4l-1.2 1.2M398.1 27.3l-1.2 1.2M398.1 37.5l-1.2 1.2M398.1 35l-1.2 1.2M384.2 50.2l1.2 1.2M384.2 57.8l1.2 1.2M384.2 52.7l1.2 1.2M384.2 55.3l1.2 1.2"/>
<path d="M384.2 42.6l1.2 1.2M384.2 47.7l1.2 1.2M384.2 40l1.2 1.2M384.2 45.1l1.2 1.2M385.4 42.6l-1.2 1.2M385.4 45.1l-1.2 1.2M385.4 40l-1.2 1.2M385.4 50.2l-1.2 1.2M385.4 52.7l-1.2 1.2M385.4 57.8l-1.2 1.2M385.4 47.7l-1.2 1.2M385.4 55.3l-1.2 1.2"/>
<path d="M396.9 52.7l1.2 1.2M396.9 40l1.2 1.2M396.9 45.1l1.2 1.2M396.9 42.6l1.2 1.2M396.9 47.7l1.2 1.2M396.9 55.3l1.2 1.2M396.9 57.8l1.2 1.2M396.9 50.2l1.2 1.2M398.1 52.7l-1.2 1.2M398.1 57.8l-1.2 1.2M398.1 50.2l-1.2 1.2M398.1 40l-1.2 1.2"/>
<path d="M398.1 45.1l-1.2 1.2M398.1 42.6l-1.2 1.2M398.1 47.7l-1.2 1.2M398.1 55.3l-1.2 1.2M384.2 78.1l1.2 1.2M384.2 75.6l1.2 1.2M384.2 73.1l1.2 1.2M384.2 65.4l1.2 1.2M384.2 68l1.2 1.2M384.2 70.5l1.2 1.2M384.2 62.9l1.2 1.2M384.2 60.4l1.2 1.2"/>
<path d="M385.4 65.4l-1.2 1.2M385.4 78.1l-1.2 1.2M385.4 75.6l-1.2 1.2M385.4 73.1l-1.2 1.2M385.4 68l-1.2 1.2M385.4 70.5l-1.2 1.2M385.4 62.9l-1.2 1.2M385.4 60.4l-1.2 1.2M396.9 73.1l1.2 1.2M396.9 65.4l1.2 1.2M396.9 62.9l1.2 1.2M396.9 70.5l1.2 1.2"/>
<path d="M396.9 68l1.2 1.2M396.9 78.1l1.2 1.2M396.9 75.6l1.2 1.2M396.9 60.4l1.2 1.2M398.1 65.4l-1.2 1.2M398.1 62.9l-1.2 1.2M398.1 75.6l-1.2 1.2M398.1 68l-1.2 1.2M398.1 70.5l-1.2 1.2M398.1 73.1l-1.2 1.2M398.1 78.1l-1.2 1.2M398.1 60.4l-1.2 1.2"/>
<path d="M76.9 95.9l1.2 1.2M76.9 92.1l1.2 1.2M76.9 99.7l1.2 1.2M78.1 95.9l-1.2 1.2M78.1 92.1l-1.2 1.2M78.1 99.7l-1.2 1.2M384.2 88.3l1.2 1.2M384.2 80.7l1.2 1.2M384.2 83.2l1.2 1.2M384.2 90.8l1.2 1.2M384.2 93.4l1.2 1.2M384.2 85.8l1.2 1.2"/>
<path d="M385.4 88.3l-1.2 1.2M385.4 80.7l-1.2 1.2M385.4 83.2l-1.2 1.2M385.4 85.8l-1.2 1.2M385.4 90.8l-1.2 1.2M385.4 93.4l-1.2 1.2M396.9 93.4l1.2 1.2M396.9 85.8l1.2 1.2M396.9 90.8l1.2 1.2M396.9 88.3l1.2 1.2M396.9 80.7l1.2 1.2M396.9 83.2l1.2 1.2"/>
<path d="M398.1 85.8l-1.2 1.2M398.1 90.8l-1.2 1.2M398.1 93.4l-1.2 1.2M398.1 88.3l-1.2 1.2M398.1 80.7l-1.2 1.2M398.1 83.2l-1.2 1.2M76.9 103.5l1.2 1.2M78.1 103.5l-1.2 1.2M384.2 104.8l1.2 1.2M384.2 112.4l1.2 1.2M384.2 102.3l1.2 1.2M384.2 107.3l1.2 1.3"/>
<path d="M384.2 109.9l1.2 1.2M384.2 115l1.2 1.2M384.2 117.5l1.2 1.2M385.4 115l-1.2 1.2M385.4 117.5l-1.2 1.2M385.4 104.8l-1.2 1.2M385.4 112.4l-1.2 1.2M385.4 102.3l-1.2 1.2M385.4 107.3l-1.2 1.3M385.4 109.9l-1.2 1.2M396.9 102.3l1.2 1.2M396.9 109.9l1.2 1.2"/>
<path d="M396.9 107.3l1.2 1.3M396.9 112.4l1.2 1.2M396.9 104.8l1.2 1.2M396.9 117.5l1.2 1.2M396.9 115l1.2 1.2M398.1 102.3l-1.2 1.2M398.1 109.9l-1.2 1.2M398.1 107.3l-1.2 1.3M398.1 112.4l-1.2 1.2M398.1 104.8l-1.2 1.2M398.1 115l-1.2 1.2M398.1 117.5l-1.2 1.2"/>
<path d="M384.2 135.3l1.2 1.2M384.2 127.7l1.2 1.2M384.2 125.1l1.2 1.2M384.2 132.7l1.2 1.3M384.2 130.2l1.2 1.2M384.2 137.8l1.2 1.2M384.2 122.6l1.2 1.2M384.2 120l1.2 1.3M385.4 122.6l-1.2 1.2M385.4 125.1l-1.2 1.2M385.4 135.3l-1.2 1.2M385.4 127.7l-1.2 1.2"/>
<path d="M385.4 132.7l-1.2 1.3M385.4 130.2l-1.2 1.2M385.4 137.8l-1.2 1.2M385.4 120l-1.2 1.3M396.9 120l1.2 1.3M396.9 137.8l1.2 1.2M396.9 135.3l1.2 1.2M396.9 130.2l1.2 1.2M396.9 132.7l1.2 1.3M396.9 122.6l1.2 1.2M396.9 125.1l1.2 1.2M396.9 127.7l1.2 1.2"/>
<path d="M398.1 122.6l-1.2 1.2M398.1 120l-1.2 1.3M398.1 137.8l-1.2 1.2M398.1 135.3l-1.2 1.2M398.1 130.2l-1.2 1.2M398.1 132.7l-1.2 1.3M398.1 125.1l-1.2 1.2M398.1 127.7l-1.2 1.2M384.2 158.1l1.2 1.3M384.2 155.6l1.2 1.2M384.2 153.1l1.2 1.2M384.2 145.4l1.2 1.3"/>
<path d="M384.2 142.9l1.2 1.2M384.2 148l1.2 1.2M384.2 150.5l1.2 1.2M384.2 140.4l1.2 1.2M385.4 158.1l-1.2 1.3M385.4 155.6l-1.2 1.2M385.4 153.1l-1.2 1.2M385.4 150.5l-1.2 1.2M385.4 148l-1.2 1.2M385.4 142.9l-1.2 1.2M385.4 145.4l-1.2 1.3M385.4 140.4l-1.2 1.2"/>
<path d="M396.9 158.1l1.2 1.3M396.9 155.6l1.2 1.2M396.9 142.9l1.2 1.2M396.9 140.4l1.2 1.2M396.9 150.5l1.2 1.2M396.9 148l1.2 1.2M396.9 153.1l1.2 1.2M396.9 145.4l1.2 1.3M398.1 142.9l-1.2 1.2M398.1 153.1l-1.2 1.2M398.1 148l-1.2 1.2M398.1 150.5l-1.2 1.2"/>
<path d="M398.1 155.6l-1.2 1.2M398.1 158.1l-1.2 1.3M398.1 140.4l-1.2 1.2M398.1 145.4l-1.2 1.3M384.2 165.8l1.2 1.2M384.2 160.7l1.2 1.2M384.2 163.2l1.2 1.2M384.2 168.3l1.2 1.2M384.2 173.4l1.2 1.2M384.2 175.9l1.2 1.2M384.2 170.8l1.2 1.3M385.4 165.8l-1.2 1.2"/>
<path d="M385.4 160.7l-1.2 1.2M385.4 163.2l-1.2 1.2M385.4 168.3l-1.2 1.2M385.4 173.4l-1.2 1.2M385.4 175.9l-1.2 1.2M385.4 170.8l-1.2 1.3M396.9 175.9l1.2 1.2M396.9 173.4l1.2 1.2M396.9 168.3l1.2 1.2M396.9 165.8l1.2 1.2M396.9 170.8l1.2 1.3M396.9 163.2l1.2 1.2"/>
<path d="M396.9 160.7l1.2 1.2M398.1 175.9l-1.2 1.2M398.1 168.3l-1.2 1.2M398.1 165.8l-1.2 1.2M398.1 173.4l-1.2 1.2M398.1 170.8l-1.2 1.3M398.1 160.7l-1.2 1.2M398.1 163.2l-1.2 1.2M328.3 206.4l1.2 1.2M328.3 203.9l1.2 1.2M329.5 206.4l-1.2 1.2M329.5 203.9l-1.2 1.2"/>
<path d="M243.2 276.3l1.2 1.2M244.4 276.3l-1.2 1.2M254.7 276.3l1.2 1.2M255.9 276.3l-1.2 1.2M264.8 276.3l1.2 1.2M266 276.3l-1.2 1.2M275 276.3l1.2 1.2M276.2 276.3l-1.2 1.2M285.1 276.3l1.3 1.2M286.4 276.3l-1.3 1.2M295.3 276.3l1.2 1.2M296.5 276.3l-1.2 1.2"/>
</g>
<path d="M76.4 96.1h.8M331.1 199h.7M387 199h.7M331.1 211.7h.7M387 211.7h.7M331.1 224.4h.7M331.1 237.1h.7M387 224.4h.7M387 237.1h.7" fill="none" stroke="#a90000" stroke-width=".18"/>
<g fill="#009600" stroke="#009600" stroke-width=".18">
<circle cx="400" cy="237.5" r=".46"/>
<circle cx="400" cy="240" r=".46"/>
<circle cx="400" cy="224.8" r=".46"/>
<circle cx="400" cy="222.2" r=".46"/>
<circle cx="400" cy="232.4" r=".46"/>
<circle cx="400" cy="227.3" r=".46"/>
<circle cx="400" cy="229.9" r=".46"/>
<circle cx="400" cy="234.9" r=".46"/>
<circle cx="400" cy="199.4" r=".46"/>
<circle cx="400" cy="196.9" r=".46"/>
<circle cx="400" cy="194.3" r=".46"/>
<circle cx="400" cy="191.8" r=".46"/>
<circle cx="400" cy="189.2" r=".46"/>
<circle cx="344.2" cy="222.2" r=".46"/>
<circle cx="344.2" cy="219.7" r=".46"/>
<circle cx="344.2" cy="209.6" r=".46"/>
<circle cx="344.2" cy="212.1" r=".46"/>
<circle cx="344.2" cy="217.2" r=".46"/>
<circle cx="344.2" cy="214.6" r=".46"/>
<circle cx="344.2" cy="224.8" r=".46"/>
<circle cx="344.2" cy="237.5" r=".46"/>
<circle cx="344.2" cy="234.9" r=".46"/>
<circle cx="344.2" cy="240" r=".46"/>
<circle cx="344.2" cy="232.4" r=".46"/>
<circle cx="344.2" cy="227.3" r=".46"/>
<circle cx="344.2" cy="229.9" r=".46"/>
<circle cx="400" cy="209.6" r=".46"/>
<circle cx="400" cy="219.7" r=".46"/>
<circle cx="400" cy="217.2" r=".46"/>
<circle cx="400" cy="201.9" r=".46"/>
<circle cx="400" cy="207" r=".46"/>
<circle cx="400" cy="204.5" r=".46"/>
<circle cx="400" cy="214.6" r=".46"/>
<circle cx="400" cy="212.1" r=".46"/>
<circle cx="344.2" cy="196.9" r=".46"/>
<circle cx="344.2" cy="199.4" r=".46"/>
<circle cx="344.2" cy="194.3" r=".46"/>
<circle cx="344.2" cy="204.5" r=".46"/>
<circle cx="344.2" cy="201.9" r=".46"/>
<circle cx="344.2" cy="207" r=".46"/>
<circle cx="344.2" cy="189.2" r=".46"/>
<circle cx="344.2" cy="191.8" r=".46"/>
<circle cx="241.3" cy="29.2" r=".46"/>
<circle cx="250.2" cy="29.2" r=".46"/>
<circle cx="257.8" cy="29.2" r=".46"/>
<circle cx="266.7" cy="29.2" r=".46"/>
<circle cx="232.4" cy="29.2" r=".46"/>
<circle cx="223.5" cy="29.2" r=".46"/>
<circle cx="133.3" cy="29.2" r=".46"/>
<circle cx="151.1" cy="29.2" r=".46"/>
<circle cx="293.4" cy="29.2" r=".46"/>
<circle cx="301" cy="29.2" r=".46"/>
<circle cx="327.7" cy="29.2" r=".46"/>
<circle cx="335.3" cy="29.2" r=".46"/>
<circle cx="284.5" cy="29.2" r=".46"/>
<circle cx="275.6" cy="29.2" r=".46"/>
<circle cx="318.8" cy="29.2" r=".46"/>
<circle cx="309.9" cy="29.2" r=".46"/>
<circle cx="207" cy="29.2" r=".46"/>
<circle cx="198.1" cy="29.2" r=".46"/>
<circle cx="179.1" cy="29.2" r=".46"/>
<circle cx="189.2" cy="29.2" r=".46"/>
<circle cx="215.9" cy="29.2" r=".46"/>
</g>
<use href="#words"/>
</svg>
